VERSION 5.7 ;
BUSBITCHARS "[]" ;
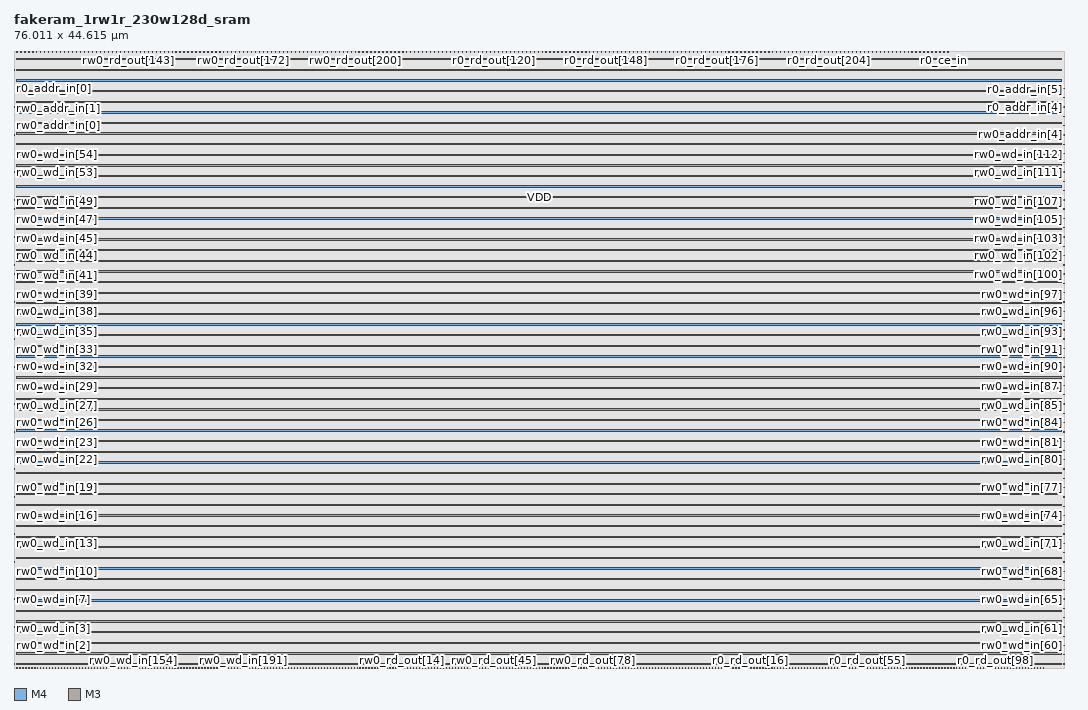
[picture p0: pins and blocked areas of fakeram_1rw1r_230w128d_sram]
MACRO fakeram_1rw1r_230w128d_sram
  FOREIGN fakeram_1rw1r_230w128d_sram 0 0 ;
  SYMMETRY X Y R90 ;
  SIZE 76.011 BY 44.615 ;
  CLASS BLOCK ;
  PIN rw0_wd_in[0]
    DIRECTION INPUT ;
    USE SIGNAL ;
    SHAPE ABUTMENT ;
    PORT
      LAYER M4 ;
      RECT 0.000 0.276 0.072 0.300 ;
    END
  END rw0_wd_in[0]
  PIN rw0_wd_in[1]
    DIRECTION INPUT ;
    USE SIGNAL ;
    SHAPE ABUTMENT ;
    PORT
      LAYER M4 ;
      RECT 0.000 0.948 0.072 0.972 ;
    END
  END rw0_wd_in[1]
  PIN rw0_wd_in[2]
    DIRECTION INPUT ;
    USE SIGNAL ;
    SHAPE ABUTMENT ;
    PORT
      LAYER M4 ;
      RECT 0.000 1.620 0.072 1.644 ;
    END
  END rw0_wd_in[2]
  PIN rw0_wd_in[3]
    DIRECTION INPUT ;
    USE SIGNAL ;
    SHAPE ABUTMENT ;
    PORT
      LAYER M4 ;
      RECT 0.000 2.292 0.072 2.316 ;
    END
  END rw0_wd_in[3]
  PIN rw0_wd_in[4]
    DIRECTION INPUT ;
    USE SIGNAL ;
    SHAPE ABUTMENT ;
    PORT
      LAYER M4 ;
      RECT 0.000 2.964 0.072 2.988 ;
    END
  END rw0_wd_in[4]
  PIN rw0_wd_in[5]
    DIRECTION INPUT ;
    USE SIGNAL ;
    SHAPE ABUTMENT ;
    PORT
      LAYER M4 ;
      RECT 0.000 3.636 0.072 3.660 ;
    END
  END rw0_wd_in[5]
  PIN rw0_wd_in[6]
    DIRECTION INPUT ;
    USE SIGNAL ;
    SHAPE ABUTMENT ;
    PORT
      LAYER M4 ;
      RECT 0.000 4.308 0.072 4.332 ;
    END
  END rw0_wd_in[6]
  PIN rw0_wd_in[7]
    DIRECTION INPUT ;
    USE SIGNAL ;
    SHAPE ABUTMENT ;
    PORT
      LAYER M4 ;
      RECT 0.000 4.980 0.072 5.004 ;
    END
  END rw0_wd_in[7]
  PIN rw0_wd_in[8]
    DIRECTION INPUT ;
    USE SIGNAL ;
    SHAPE ABUTMENT ;
    PORT
      LAYER M4 ;
      RECT 0.000 5.652 0.072 5.676 ;
    END
  END rw0_wd_in[8]
  PIN rw0_wd_in[9]
    DIRECTION INPUT ;
    USE SIGNAL ;
    SHAPE ABUTMENT ;
    PORT
      LAYER M4 ;
      RECT 0.000 6.324 0.072 6.348 ;
    END
  END rw0_wd_in[9]
  PIN rw0_wd_in[10]
    DIRECTION INPUT ;
    USE SIGNAL ;
    SHAPE ABUTMENT ;
    PORT
      LAYER M4 ;
      RECT 0.000 6.996 0.072 7.020 ;
    END
  END rw0_wd_in[10]
  PIN rw0_wd_in[11]
    DIRECTION INPUT ;
    USE SIGNAL ;
    SHAPE ABUTMENT ;
    PORT
      LAYER M4 ;
      RECT 0.000 7.668 0.072 7.692 ;
    END
  END rw0_wd_in[11]
  PIN rw0_wd_in[12]
    DIRECTION INPUT ;
    USE SIGNAL ;
    SHAPE ABUTMENT ;
    PORT
      LAYER M4 ;
      RECT 0.000 8.340 0.072 8.364 ;
    END
  END rw0_wd_in[12]
  PIN rw0_wd_in[13]
    DIRECTION INPUT ;
    USE SIGNAL ;
    SHAPE ABUTMENT ;
    PORT
      LAYER M4 ;
      RECT 0.000 9.012 0.072 9.036 ;
    END
  END rw0_wd_in[13]
  PIN rw0_wd_in[14]
    DIRECTION INPUT ;
    USE SIGNAL ;
    SHAPE ABUTMENT ;
    PORT
      LAYER M4 ;
      RECT 0.000 9.684 0.072 9.708 ;
    END
  END rw0_wd_in[14]
  PIN rw0_wd_in[15]
    DIRECTION INPUT ;
    USE SIGNAL ;
    SHAPE ABUTMENT ;
    PORT
      LAYER M4 ;
      RECT 0.000 10.356 0.072 10.380 ;
    END
  END rw0_wd_in[15]
  PIN rw0_wd_in[16]
    DIRECTION INPUT ;
    USE SIGNAL ;
    SHAPE ABUTMENT ;
    PORT
      LAYER M4 ;
      RECT 0.000 11.028 0.072 11.052 ;
    END
  END rw0_wd_in[16]
  PIN rw0_wd_in[17]
    DIRECTION INPUT ;
    USE SIGNAL ;
    SHAPE ABUTMENT ;
    PORT
      LAYER M4 ;
      RECT 0.000 11.700 0.072 11.724 ;
    END
  END rw0_wd_in[17]
  PIN rw0_wd_in[18]
    DIRECTION INPUT ;
    USE SIGNAL ;
    SHAPE ABUTMENT ;
    PORT
      LAYER M4 ;
      RECT 0.000 12.372 0.072 12.396 ;
    END
  END rw0_wd_in[18]
  PIN rw0_wd_in[19]
    DIRECTION INPUT ;
    USE SIGNAL ;
    SHAPE ABUTMENT ;
    PORT
      LAYER M4 ;
      RECT 0.000 13.044 0.072 13.068 ;
    END
  END rw0_wd_in[19]
  PIN rw0_wd_in[20]
    DIRECTION INPUT ;
    USE SIGNAL ;
    SHAPE ABUTMENT ;
    PORT
      LAYER M4 ;
      RECT 0.000 13.716 0.072 13.740 ;
    END
  END rw0_wd_in[20]
  PIN rw0_wd_in[21]
    DIRECTION INPUT ;
    USE SIGNAL ;
    SHAPE ABUTMENT ;
    PORT
      LAYER M4 ;
      RECT 0.000 14.388 0.072 14.412 ;
    END
  END rw0_wd_in[21]
  PIN rw0_wd_in[22]
    DIRECTION INPUT ;
    USE SIGNAL ;
    SHAPE ABUTMENT ;
    PORT
      LAYER M4 ;
      RECT 0.000 15.060 0.072 15.084 ;
    END
  END rw0_wd_in[22]
  PIN rw0_wd_in[23]
    DIRECTION INPUT ;
    USE SIGNAL ;
    SHAPE ABUTMENT ;
    PORT
      LAYER M4 ;
      RECT 0.000 15.732 0.072 15.756 ;
    END
  END rw0_wd_in[23]
  PIN rw0_wd_in[24]
    DIRECTION INPUT ;
    USE SIGNAL ;
    SHAPE ABUTMENT ;
    PORT
      LAYER M4 ;
      RECT 0.000 16.404 0.072 16.428 ;
    END
  END rw0_wd_in[24]
  PIN rw0_wd_in[25]
    DIRECTION INPUT ;
    USE SIGNAL ;
    SHAPE ABUTMENT ;
    PORT
      LAYER M4 ;
      RECT 0.000 17.076 0.072 17.100 ;
    END
  END rw0_wd_in[25]
  PIN rw0_wd_in[26]
    DIRECTION INPUT ;
    USE SIGNAL ;
    SHAPE ABUTMENT ;
    PORT
      LAYER M4 ;
      RECT 0.000 17.748 0.072 17.772 ;
    END
  END rw0_wd_in[26]
  PIN rw0_wd_in[27]
    DIRECTION INPUT ;
    USE SIGNAL ;
    SHAPE ABUTMENT ;
    PORT
      LAYER M4 ;
      RECT 0.000 18.420 0.072 18.444 ;
    END
  END rw0_wd_in[27]
  PIN rw0_wd_in[28]
    DIRECTION INPUT ;
    USE SIGNAL ;
    SHAPE ABUTMENT ;
    PORT
      LAYER M4 ;
      RECT 0.000 19.092 0.072 19.116 ;
    END
  END rw0_wd_in[28]
  PIN rw0_wd_in[29]
    DIRECTION INPUT ;
    USE SIGNAL ;
    SHAPE ABUTMENT ;
    PORT
      LAYER M4 ;
      RECT 0.000 19.764 0.072 19.788 ;
    END
  END rw0_wd_in[29]
  PIN rw0_wd_in[30]
    DIRECTION INPUT ;
    USE SIGNAL ;
    SHAPE ABUTMENT ;
    PORT
      LAYER M4 ;
      RECT 0.000 20.436 0.072 20.460 ;
    END
  END rw0_wd_in[30]
  PIN rw0_wd_in[31]
    DIRECTION INPUT ;
    USE SIGNAL ;
    SHAPE ABUTMENT ;
    PORT
      LAYER M4 ;
      RECT 0.000 21.108 0.072 21.132 ;
    END
  END rw0_wd_in[31]
  PIN rw0_wd_in[32]
    DIRECTION INPUT ;
    USE SIGNAL ;
    SHAPE ABUTMENT ;
    PORT
      LAYER M4 ;
      RECT 0.000 21.780 0.072 21.804 ;
    END
  END rw0_wd_in[32]
  PIN rw0_wd_in[33]
    DIRECTION INPUT ;
    USE SIGNAL ;
    SHAPE ABUTMENT ;
    PORT
      LAYER M4 ;
      RECT 0.000 22.452 0.072 22.476 ;
    END
  END rw0_wd_in[33]
  PIN rw0_wd_in[34]
    DIRECTION INPUT ;
    USE SIGNAL ;
    SHAPE ABUTMENT ;
    PORT
      LAYER M4 ;
      RECT 0.000 23.124 0.072 23.148 ;
    END
  END rw0_wd_in[34]
  PIN rw0_wd_in[35]
    DIRECTION INPUT ;
    USE SIGNAL ;
    SHAPE ABUTMENT ;
    PORT
      LAYER M4 ;
      RECT 0.000 23.796 0.072 23.820 ;
    END
  END rw0_wd_in[35]
  PIN rw0_wd_in[36]
    DIRECTION INPUT ;
    USE SIGNAL ;
    SHAPE ABUTMENT ;
    PORT
      LAYER M4 ;
      RECT 0.000 24.468 0.072 24.492 ;
    END
  END rw0_wd_in[36]
  PIN rw0_wd_in[37]
    DIRECTION INPUT ;
    USE SIGNAL ;
    SHAPE ABUTMENT ;
    PORT
      LAYER M4 ;
      RECT 0.000 25.140 0.072 25.164 ;
    END
  END rw0_wd_in[37]
  PIN rw0_wd_in[38]
    DIRECTION INPUT ;
    USE SIGNAL ;
    SHAPE ABUTMENT ;
    PORT
      LAYER M4 ;
      RECT 0.000 25.812 0.072 25.836 ;
    END
  END rw0_wd_in[38]
  PIN rw0_wd_in[39]
    DIRECTION INPUT ;
    USE SIGNAL ;
    SHAPE ABUTMENT ;
    PORT
      LAYER M4 ;
      RECT 0.000 26.484 0.072 26.508 ;
    END
  END rw0_wd_in[39]
  PIN rw0_wd_in[40]
    DIRECTION INPUT ;
    USE SIGNAL ;
    SHAPE ABUTMENT ;
    PORT
      LAYER M4 ;
      RECT 0.000 27.156 0.072 27.180 ;
    END
  END rw0_wd_in[40]
  PIN rw0_wd_in[41]
    DIRECTION INPUT ;
    USE SIGNAL ;
    SHAPE ABUTMENT ;
    PORT
      LAYER M4 ;
      RECT 0.000 27.828 0.072 27.852 ;
    END
  END rw0_wd_in[41]
  PIN rw0_wd_in[42]
    DIRECTION INPUT ;
    USE SIGNAL ;
    SHAPE ABUTMENT ;
    PORT
      LAYER M4 ;
      RECT 0.000 28.500 0.072 28.524 ;
    END
  END rw0_wd_in[42]
  PIN rw0_wd_in[43]
    DIRECTION INPUT ;
    USE SIGNAL ;
    SHAPE ABUTMENT ;
    PORT
      LAYER M4 ;
      RECT 0.000 29.172 0.072 29.196 ;
    END
  END rw0_wd_in[43]
  PIN rw0_wd_in[44]
    DIRECTION INPUT ;
    USE SIGNAL ;
    SHAPE ABUTMENT ;
    PORT
      LAYER M4 ;
      RECT 0.000 29.844 0.072 29.868 ;
    END
  END rw0_wd_in[44]
  PIN rw0_wd_in[45]
    DIRECTION INPUT ;
    USE SIGNAL ;
    SHAPE ABUTMENT ;
    PORT
      LAYER M4 ;
      RECT 0.000 30.516 0.072 30.540 ;
    END
  END rw0_wd_in[45]
  PIN rw0_wd_in[46]
    DIRECTION INPUT ;
    USE SIGNAL ;
    SHAPE ABUTMENT ;
    PORT
      LAYER M4 ;
      RECT 0.000 31.188 0.072 31.212 ;
    END
  END rw0_wd_in[46]
  PIN rw0_wd_in[47]
    DIRECTION INPUT ;
    USE SIGNAL ;
    SHAPE ABUTMENT ;
    PORT
      LAYER M4 ;
      RECT 0.000 31.860 0.072 31.884 ;
    END
  END rw0_wd_in[47]
  PIN rw0_wd_in[48]
    DIRECTION INPUT ;
    USE SIGNAL ;
    SHAPE ABUTMENT ;
    PORT
      LAYER M4 ;
      RECT 0.000 32.532 0.072 32.556 ;
    END
  END rw0_wd_in[48]
  PIN rw0_wd_in[49]
    DIRECTION INPUT ;
    USE SIGNAL ;
    SHAPE ABUTMENT ;
    PORT
      LAYER M4 ;
      RECT 0.000 33.204 0.072 33.228 ;
    END
  END rw0_wd_in[49]
  PIN rw0_wd_in[50]
    DIRECTION INPUT ;
    USE SIGNAL ;
    SHAPE ABUTMENT ;
    PORT
      LAYER M4 ;
      RECT 0.000 33.876 0.072 33.900 ;
    END
  END rw0_wd_in[50]
  PIN rw0_wd_in[51]
    DIRECTION INPUT ;
    USE SIGNAL ;
    SHAPE ABUTMENT ;
    PORT
      LAYER M4 ;
      RECT 0.000 34.548 0.072 34.572 ;
    END
  END rw0_wd_in[51]
  PIN rw0_wd_in[52]
    DIRECTION INPUT ;
    USE SIGNAL ;
    SHAPE ABUTMENT ;
    PORT
      LAYER M4 ;
      RECT 0.000 35.220 0.072 35.244 ;
    END
  END rw0_wd_in[52]
  PIN rw0_wd_in[53]
    DIRECTION INPUT ;
    USE SIGNAL ;
    SHAPE ABUTMENT ;
    PORT
      LAYER M4 ;
      RECT 0.000 35.892 0.072 35.916 ;
    END
  END rw0_wd_in[53]
  PIN rw0_wd_in[54]
    DIRECTION INPUT ;
    USE SIGNAL ;
    SHAPE ABUTMENT ;
    PORT
      LAYER M4 ;
      RECT 0.000 36.564 0.072 36.588 ;
    END
  END rw0_wd_in[54]
  PIN rw0_wd_in[55]
    DIRECTION INPUT ;
    USE SIGNAL ;
    SHAPE ABUTMENT ;
    PORT
      LAYER M4 ;
      RECT 0.000 37.236 0.072 37.260 ;
    END
  END rw0_wd_in[55]
  PIN rw0_wd_in[56]
    DIRECTION INPUT ;
    USE SIGNAL ;
    SHAPE ABUTMENT ;
    PORT
      LAYER M4 ;
      RECT 0.000 37.908 0.072 37.932 ;
    END
  END rw0_wd_in[56]
  PIN rw0_wd_in[57]
    DIRECTION INPUT ;
    USE SIGNAL ;
    SHAPE ABUTMENT ;
    PORT
      LAYER M4 ;
      RECT 0.000 38.580 0.072 38.604 ;
    END
  END rw0_wd_in[57]
  PIN rw0_wd_in[58]
    DIRECTION INPUT ;
    USE SIGNAL ;
    SHAPE ABUTMENT ;
    PORT
      LAYER M4 ;
      RECT 75.939 0.276 76.011 0.300 ;
    END
  END rw0_wd_in[58]
  PIN rw0_wd_in[59]
    DIRECTION INPUT ;
    USE SIGNAL ;
    SHAPE ABUTMENT ;
    PORT
      LAYER M4 ;
      RECT 75.939 0.948 76.011 0.972 ;
    END
  END rw0_wd_in[59]
  PIN rw0_wd_in[60]
    DIRECTION INPUT ;
    USE SIGNAL ;
    SHAPE ABUTMENT ;
    PORT
      LAYER M4 ;
      RECT 75.939 1.620 76.011 1.644 ;
    END
  END rw0_wd_in[60]
  PIN rw0_wd_in[61]
    DIRECTION INPUT ;
    USE SIGNAL ;
    SHAPE ABUTMENT ;
    PORT
      LAYER M4 ;
      RECT 75.939 2.292 76.011 2.316 ;
    END
  END rw0_wd_in[61]
  PIN rw0_wd_in[62]
    DIRECTION INPUT ;
    USE SIGNAL ;
    SHAPE ABUTMENT ;
    PORT
      LAYER M4 ;
      RECT 75.939 2.964 76.011 2.988 ;
    END
  END rw0_wd_in[62]
  PIN rw0_wd_in[63]
    DIRECTION INPUT ;
    USE SIGNAL ;
    SHAPE ABUTMENT ;
    PORT
      LAYER M4 ;
      RECT 75.939 3.636 76.011 3.660 ;
    END
  END rw0_wd_in[63]
  PIN rw0_wd_in[64]
    DIRECTION INPUT ;
    USE SIGNAL ;
    SHAPE ABUTMENT ;
    PORT
      LAYER M4 ;
      RECT 75.939 4.308 76.011 4.332 ;
    END
  END rw0_wd_in[64]
  PIN rw0_wd_in[65]
    DIRECTION INPUT ;
    USE SIGNAL ;
    SHAPE ABUTMENT ;
    PORT
      LAYER M4 ;
      RECT 75.939 4.980 76.011 5.004 ;
    END
  END rw0_wd_in[65]
  PIN rw0_wd_in[66]
    DIRECTION INPUT ;
    USE SIGNAL ;
    SHAPE ABUTMENT ;
    PORT
      LAYER M4 ;
      RECT 75.939 5.652 76.011 5.676 ;
    END
  END rw0_wd_in[66]
  PIN rw0_wd_in[67]
    DIRECTION INPUT ;
    USE SIGNAL ;
    SHAPE ABUTMENT ;
    PORT
      LAYER M4 ;
      RECT 75.939 6.324 76.011 6.348 ;
    END
  END rw0_wd_in[67]
  PIN rw0_wd_in[68]
    DIRECTION INPUT ;
    USE SIGNAL ;
    SHAPE ABUTMENT ;
    PORT
      LAYER M4 ;
      RECT 75.939 6.996 76.011 7.020 ;
    END
  END rw0_wd_in[68]
  PIN rw0_wd_in[69]
    DIRECTION INPUT ;
    USE SIGNAL ;
    SHAPE ABUTMENT ;
    PORT
      LAYER M4 ;
      RECT 75.939 7.668 76.011 7.692 ;
    END
  END rw0_wd_in[69]
  PIN rw0_wd_in[70]
    DIRECTION INPUT ;
    USE SIGNAL ;
    SHAPE ABUTMENT ;
    PORT
      LAYER M4 ;
      RECT 75.939 8.340 76.011 8.364 ;
    END
  END rw0_wd_in[70]
  PIN rw0_wd_in[71]
    DIRECTION INPUT ;
    USE SIGNAL ;
    SHAPE ABUTMENT ;
    PORT
      LAYER M4 ;
      RECT 75.939 9.012 76.011 9.036 ;
    END
  END rw0_wd_in[71]
  PIN rw0_wd_in[72]
    DIRECTION INPUT ;
    USE SIGNAL ;
    SHAPE ABUTMENT ;
    PORT
      LAYER M4 ;
      RECT 75.939 9.684 76.011 9.708 ;
    END
  END rw0_wd_in[72]
  PIN rw0_wd_in[73]
    DIRECTION INPUT ;
    USE SIGNAL ;
    SHAPE ABUTMENT ;
    PORT
      LAYER M4 ;
      RECT 75.939 10.356 76.011 10.380 ;
    END
  END rw0_wd_in[73]
  PIN rw0_wd_in[74]
    DIRECTION INPUT ;
    USE SIGNAL ;
    SHAPE ABUTMENT ;
    PORT
      LAYER M4 ;
      RECT 75.939 11.028 76.011 11.052 ;
    END
  END rw0_wd_in[74]
  PIN rw0_wd_in[75]
    DIRECTION INPUT ;
    USE SIGNAL ;
    SHAPE ABUTMENT ;
    PORT
      LAYER M4 ;
      RECT 75.939 11.700 76.011 11.724 ;
    END
  END rw0_wd_in[75]
  PIN rw0_wd_in[76]
    DIRECTION INPUT ;
    USE SIGNAL ;
    SHAPE ABUTMENT ;
    PORT
      LAYER M4 ;
      RECT 75.939 12.372 76.011 12.396 ;
    END
  END rw0_wd_in[76]
  PIN rw0_wd_in[77]
    DIRECTION INPUT ;
    USE SIGNAL ;
    SHAPE ABUTMENT ;
    PORT
      LAYER M4 ;
      RECT 75.939 13.044 76.011 13.068 ;
    END
  END rw0_wd_in[77]
  PIN rw0_wd_in[78]
    DIRECTION INPUT ;
    USE SIGNAL ;
    SHAPE ABUTMENT ;
    PORT
      LAYER M4 ;
      RECT 75.939 13.716 76.011 13.740 ;
    END
  END rw0_wd_in[78]
  PIN rw0_wd_in[79]
    DIRECTION INPUT ;
    USE SIGNAL ;
    SHAPE ABUTMENT ;
    PORT
      LAYER M4 ;
      RECT 75.939 14.388 76.011 14.412 ;
    END
  END rw0_wd_in[79]
  PIN rw0_wd_in[80]
    DIRECTION INPUT ;
    USE SIGNAL ;
    SHAPE ABUTMENT ;
    PORT
      LAYER M4 ;
      RECT 75.939 15.060 76.011 15.084 ;
    END
  END rw0_wd_in[80]
  PIN rw0_wd_in[81]
    DIRECTION INPUT ;
    USE SIGNAL ;
    SHAPE ABUTMENT ;
    PORT
      LAYER M4 ;
      RECT 75.939 15.732 76.011 15.756 ;
    END
  END rw0_wd_in[81]
  PIN rw0_wd_in[82]
    DIRECTION INPUT ;
    USE SIGNAL ;
    SHAPE ABUTMENT ;
    PORT
      LAYER M4 ;
      RECT 75.939 16.404 76.011 16.428 ;
    END
  END rw0_wd_in[82]
  PIN rw0_wd_in[83]
    DIRECTION INPUT ;
    USE SIGNAL ;
    SHAPE ABUTMENT ;
    PORT
      LAYER M4 ;
      RECT 75.939 17.076 76.011 17.100 ;
    END
  END rw0_wd_in[83]
  PIN rw0_wd_in[84]
    DIRECTION INPUT ;
    USE SIGNAL ;
    SHAPE ABUTMENT ;
    PORT
      LAYER M4 ;
      RECT 75.939 17.748 76.011 17.772 ;
    END
  END rw0_wd_in[84]
  PIN rw0_wd_in[85]
    DIRECTION INPUT ;
    USE SIGNAL ;
    SHAPE ABUTMENT ;
    PORT
      LAYER M4 ;
      RECT 75.939 18.420 76.011 18.444 ;
    END
  END rw0_wd_in[85]
  PIN rw0_wd_in[86]
    DIRECTION INPUT ;
    USE SIGNAL ;
    SHAPE ABUTMENT ;
    PORT
      LAYER M4 ;
      RECT 75.939 19.092 76.011 19.116 ;
    END
  END rw0_wd_in[86]
  PIN rw0_wd_in[87]
    DIRECTION INPUT ;
    USE SIGNAL ;
    SHAPE ABUTMENT ;
    PORT
      LAYER M4 ;
      RECT 75.939 19.764 76.011 19.788 ;
    END
  END rw0_wd_in[87]
  PIN rw0_wd_in[88]
    DIRECTION INPUT ;
    USE SIGNAL ;
    SHAPE ABUTMENT ;
    PORT
      LAYER M4 ;
      RECT 75.939 20.436 76.011 20.460 ;
    END
  END rw0_wd_in[88]
  PIN rw0_wd_in[89]
    DIRECTION INPUT ;
    USE SIGNAL ;
    SHAPE ABUTMENT ;
    PORT
      LAYER M4 ;
      RECT 75.939 21.108 76.011 21.132 ;
    END
  END rw0_wd_in[89]
  PIN rw0_wd_in[90]
    DIRECTION INPUT ;
    USE SIGNAL ;
    SHAPE ABUTMENT ;
    PORT
      LAYER M4 ;
      RECT 75.939 21.780 76.011 21.804 ;
    END
  END rw0_wd_in[90]
  PIN rw0_wd_in[91]
    DIRECTION INPUT ;
    USE SIGNAL ;
    SHAPE ABUTMENT ;
    PORT
      LAYER M4 ;
      RECT 75.939 22.452 76.011 22.476 ;
    END
  END rw0_wd_in[91]
  PIN rw0_wd_in[92]
    DIRECTION INPUT ;
    USE SIGNAL ;
    SHAPE ABUTMENT ;
    PORT
      LAYER M4 ;
      RECT 75.939 23.124 76.011 23.148 ;
    END
  END rw0_wd_in[92]
  PIN rw0_wd_in[93]
    DIRECTION INPUT ;
    USE SIGNAL ;
    SHAPE ABUTMENT ;
    PORT
      LAYER M4 ;
      RECT 75.939 23.796 76.011 23.820 ;
    END
  END rw0_wd_in[93]
  PIN rw0_wd_in[94]
    DIRECTION INPUT ;
    USE SIGNAL ;
    SHAPE ABUTMENT ;
    PORT
      LAYER M4 ;
      RECT 75.939 24.468 76.011 24.492 ;
    END
  END rw0_wd_in[94]
  PIN rw0_wd_in[95]
    DIRECTION INPUT ;
    USE SIGNAL ;
    SHAPE ABUTMENT ;
    PORT
      LAYER M4 ;
      RECT 75.939 25.140 76.011 25.164 ;
    END
  END rw0_wd_in[95]
  PIN rw0_wd_in[96]
    DIRECTION INPUT ;
    USE SIGNAL ;
    SHAPE ABUTMENT ;
    PORT
      LAYER M4 ;
      RECT 75.939 25.812 76.011 25.836 ;
    END
  END rw0_wd_in[96]
  PIN rw0_wd_in[97]
    DIRECTION INPUT ;
    USE SIGNAL ;
    SHAPE ABUTMENT ;
    PORT
      LAYER M4 ;
      RECT 75.939 26.484 76.011 26.508 ;
    END
  END rw0_wd_in[97]
  PIN rw0_wd_in[98]
    DIRECTION INPUT ;
    USE SIGNAL ;
    SHAPE ABUTMENT ;
    PORT
      LAYER M4 ;
      RECT 75.939 27.156 76.011 27.180 ;
    END
  END rw0_wd_in[98]
  PIN rw0_wd_in[99]
    DIRECTION INPUT ;
    USE SIGNAL ;
    SHAPE ABUTMENT ;
    PORT
      LAYER M4 ;
      RECT 75.939 27.828 76.011 27.852 ;
    END
  END rw0_wd_in[99]
  PIN rw0_wd_in[100]
    DIRECTION INPUT ;
    USE SIGNAL ;
    SHAPE ABUTMENT ;
    PORT
      LAYER M4 ;
      RECT 75.939 28.500 76.011 28.524 ;
    END
  END rw0_wd_in[100]
  PIN rw0_wd_in[101]
    DIRECTION INPUT ;
    USE SIGNAL ;
    SHAPE ABUTMENT ;
    PORT
      LAYER M4 ;
      RECT 75.939 29.172 76.011 29.196 ;
    END
  END rw0_wd_in[101]
  PIN rw0_wd_in[102]
    DIRECTION INPUT ;
    USE SIGNAL ;
    SHAPE ABUTMENT ;
    PORT
      LAYER M4 ;
      RECT 75.939 29.844 76.011 29.868 ;
    END
  END rw0_wd_in[102]
  PIN rw0_wd_in[103]
    DIRECTION INPUT ;
    USE SIGNAL ;
    SHAPE ABUTMENT ;
    PORT
      LAYER M4 ;
      RECT 75.939 30.516 76.011 30.540 ;
    END
  END rw0_wd_in[103]
  PIN rw0_wd_in[104]
    DIRECTION INPUT ;
    USE SIGNAL ;
    SHAPE ABUTMENT ;
    PORT
      LAYER M4 ;
      RECT 75.939 31.188 76.011 31.212 ;
    END
  END rw0_wd_in[104]
  PIN rw0_wd_in[105]
    DIRECTION INPUT ;
    USE SIGNAL ;
    SHAPE ABUTMENT ;
    PORT
      LAYER M4 ;
      RECT 75.939 31.860 76.011 31.884 ;
    END
  END rw0_wd_in[105]
  PIN rw0_wd_in[106]
    DIRECTION INPUT ;
    USE SIGNAL ;
    SHAPE ABUTMENT ;
    PORT
      LAYER M4 ;
      RECT 75.939 32.532 76.011 32.556 ;
    END
  END rw0_wd_in[106]
  PIN rw0_wd_in[107]
    DIRECTION INPUT ;
    USE SIGNAL ;
    SHAPE ABUTMENT ;
    PORT
      LAYER M4 ;
      RECT 75.939 33.204 76.011 33.228 ;
    END
  END rw0_wd_in[107]
  PIN rw0_wd_in[108]
    DIRECTION INPUT ;
    USE SIGNAL ;
    SHAPE ABUTMENT ;
    PORT
      LAYER M4 ;
      RECT 75.939 33.876 76.011 33.900 ;
    END
  END rw0_wd_in[108]
  PIN rw0_wd_in[109]
    DIRECTION INPUT ;
    USE SIGNAL ;
    SHAPE ABUTMENT ;
    PORT
      LAYER M4 ;
      RECT 75.939 34.548 76.011 34.572 ;
    END
  END rw0_wd_in[109]
  PIN rw0_wd_in[110]
    DIRECTION INPUT ;
    USE SIGNAL ;
    SHAPE ABUTMENT ;
    PORT
      LAYER M4 ;
      RECT 75.939 35.220 76.011 35.244 ;
    END
  END rw0_wd_in[110]
  PIN rw0_wd_in[111]
    DIRECTION INPUT ;
    USE SIGNAL ;
    SHAPE ABUTMENT ;
    PORT
      LAYER M4 ;
      RECT 75.939 35.892 76.011 35.916 ;
    END
  END rw0_wd_in[111]
  PIN rw0_wd_in[112]
    DIRECTION INPUT ;
    USE SIGNAL ;
    SHAPE ABUTMENT ;
    PORT
      LAYER M4 ;
      RECT 75.939 36.564 76.011 36.588 ;
    END
  END rw0_wd_in[112]
  PIN rw0_wd_in[113]
    DIRECTION INPUT ;
    USE SIGNAL ;
    SHAPE ABUTMENT ;
    PORT
      LAYER M4 ;
      RECT 75.939 37.236 76.011 37.260 ;
    END
  END rw0_wd_in[113]
  PIN rw0_wd_in[114]
    DIRECTION INPUT ;
    USE SIGNAL ;
    SHAPE ABUTMENT ;
    PORT
      LAYER M4 ;
      RECT 75.939 37.908 76.011 37.932 ;
    END
  END rw0_wd_in[114]
  PIN rw0_wd_in[115]
    DIRECTION OUTPUT ;
    USE SIGNAL ;
    SHAPE ABUTMENT ;
    PORT
      LAYER M3 ;
      RECT 0.207 0.000 0.225 0.054 ;
    END
  END rw0_wd_in[115]
  PIN rw0_wd_in[116]
    DIRECTION OUTPUT ;
    USE SIGNAL ;
    SHAPE ABUTMENT ;
    PORT
      LAYER M3 ;
      RECT 0.423 0.000 0.441 0.054 ;
    END
  END rw0_wd_in[116]
  PIN rw0_wd_in[117]
    DIRECTION OUTPUT ;
    USE SIGNAL ;
    SHAPE ABUTMENT ;
    PORT
      LAYER M3 ;
      RECT 0.639 0.000 0.657 0.054 ;
    END
  END rw0_wd_in[117]
  PIN rw0_wd_in[118]
    DIRECTION OUTPUT ;
    USE SIGNAL ;
    SHAPE ABUTMENT ;
    PORT
      LAYER M3 ;
      RECT 0.855 0.000 0.873 0.054 ;
    END
  END rw0_wd_in[118]
  PIN rw0_wd_in[119]
    DIRECTION OUTPUT ;
    USE SIGNAL ;
    SHAPE ABUTMENT ;
    PORT
      LAYER M3 ;
      RECT 1.071 0.000 1.089 0.054 ;
    END
  END rw0_wd_in[119]
  PIN rw0_wd_in[120]
    DIRECTION OUTPUT ;
    USE SIGNAL ;
    SHAPE ABUTMENT ;
    PORT
      LAYER M3 ;
      RECT 1.287 0.000 1.305 0.054 ;
    END
  END rw0_wd_in[120]
  PIN rw0_wd_in[121]
    DIRECTION OUTPUT ;
    USE SIGNAL ;
    SHAPE ABUTMENT ;
    PORT
      LAYER M3 ;
      RECT 1.503 0.000 1.521 0.054 ;
    END
  END rw0_wd_in[121]
  PIN rw0_wd_in[122]
    DIRECTION OUTPUT ;
    USE SIGNAL ;
    SHAPE ABUTMENT ;
    PORT
      LAYER M3 ;
      RECT 1.719 0.000 1.737 0.054 ;
    END
  END rw0_wd_in[122]
  PIN rw0_wd_in[123]
    DIRECTION OUTPUT ;
    USE SIGNAL ;
    SHAPE ABUTMENT ;
    PORT
      LAYER M3 ;
      RECT 1.935 0.000 1.953 0.054 ;
    END
  END rw0_wd_in[123]
  PIN rw0_wd_in[124]
    DIRECTION OUTPUT ;
    USE SIGNAL ;
    SHAPE ABUTMENT ;
    PORT
      LAYER M3 ;
      RECT 2.151 0.000 2.169 0.054 ;
    END
  END rw0_wd_in[124]
  PIN rw0_wd_in[125]
    DIRECTION OUTPUT ;
    USE SIGNAL ;
    SHAPE ABUTMENT ;
    PORT
      LAYER M3 ;
      RECT 2.367 0.000 2.385 0.054 ;
    END
  END rw0_wd_in[125]
  PIN rw0_wd_in[126]
    DIRECTION OUTPUT ;
    USE SIGNAL ;
    SHAPE ABUTMENT ;
    PORT
      LAYER M3 ;
      RECT 2.583 0.000 2.601 0.054 ;
    END
  END rw0_wd_in[126]
  PIN rw0_wd_in[127]
    DIRECTION OUTPUT ;
    USE SIGNAL ;
    SHAPE ABUTMENT ;
    PORT
      LAYER M3 ;
      RECT 2.799 0.000 2.817 0.054 ;
    END
  END rw0_wd_in[127]
  PIN rw0_wd_in[128]
    DIRECTION OUTPUT ;
    USE SIGNAL ;
    SHAPE ABUTMENT ;
    PORT
      LAYER M3 ;
      RECT 3.015 0.000 3.033 0.054 ;
    END
  END rw0_wd_in[128]
  PIN rw0_wd_in[129]
    DIRECTION OUTPUT ;
    USE SIGNAL ;
    SHAPE ABUTMENT ;
    PORT
      LAYER M3 ;
      RECT 3.231 0.000 3.249 0.054 ;
    END
  END rw0_wd_in[129]
  PIN rw0_wd_in[130]
    DIRECTION OUTPUT ;
    USE SIGNAL ;
    SHAPE ABUTMENT ;
    PORT
      LAYER M3 ;
      RECT 3.447 0.000 3.465 0.054 ;
    END
  END rw0_wd_in[130]
  PIN rw0_wd_in[131]
    DIRECTION OUTPUT ;
    USE SIGNAL ;
    SHAPE ABUTMENT ;
    PORT
      LAYER M3 ;
      RECT 3.663 0.000 3.681 0.054 ;
    END
  END rw0_wd_in[131]
  PIN rw0_wd_in[132]
    DIRECTION OUTPUT ;
    USE SIGNAL ;
    SHAPE ABUTMENT ;
    PORT
      LAYER M3 ;
      RECT 3.879 0.000 3.897 0.054 ;
    END
  END rw0_wd_in[132]
  PIN rw0_wd_in[133]
    DIRECTION OUTPUT ;
    USE SIGNAL ;
    SHAPE ABUTMENT ;
    PORT
      LAYER M3 ;
      RECT 4.095 0.000 4.113 0.054 ;
    END
  END rw0_wd_in[133]
  PIN rw0_wd_in[134]
    DIRECTION OUTPUT ;
    USE SIGNAL ;
    SHAPE ABUTMENT ;
    PORT
      LAYER M3 ;
      RECT 4.311 0.000 4.329 0.054 ;
    END
  END rw0_wd_in[134]
  PIN rw0_wd_in[135]
    DIRECTION OUTPUT ;
    USE SIGNAL ;
    SHAPE ABUTMENT ;
    PORT
      LAYER M3 ;
      RECT 4.527 0.000 4.545 0.054 ;
    END
  END rw0_wd_in[135]
  PIN rw0_wd_in[136]
    DIRECTION OUTPUT ;
    USE SIGNAL ;
    SHAPE ABUTMENT ;
    PORT
      LAYER M3 ;
      RECT 4.743 0.000 4.761 0.054 ;
    END
  END rw0_wd_in[136]
  PIN rw0_wd_in[137]
    DIRECTION OUTPUT ;
    USE SIGNAL ;
    SHAPE ABUTMENT ;
    PORT
      LAYER M3 ;
      RECT 4.959 0.000 4.977 0.054 ;
    END
  END rw0_wd_in[137]
  PIN rw0_wd_in[138]
    DIRECTION OUTPUT ;
    USE SIGNAL ;
    SHAPE ABUTMENT ;
    PORT
      LAYER M3 ;
      RECT 5.175 0.000 5.193 0.054 ;
    END
  END rw0_wd_in[138]
  PIN rw0_wd_in[139]
    DIRECTION OUTPUT ;
    USE SIGNAL ;
    SHAPE ABUTMENT ;
    PORT
      LAYER M3 ;
      RECT 5.391 0.000 5.409 0.054 ;
    END
  END rw0_wd_in[139]
  PIN rw0_wd_in[140]
    DIRECTION OUTPUT ;
    USE SIGNAL ;
    SHAPE ABUTMENT ;
    PORT
      LAYER M3 ;
      RECT 5.607 0.000 5.625 0.054 ;
    END
  END rw0_wd_in[140]
  PIN rw0_wd_in[141]
    DIRECTION OUTPUT ;
    USE SIGNAL ;
    SHAPE ABUTMENT ;
    PORT
      LAYER M3 ;
      RECT 5.823 0.000 5.841 0.054 ;
    END
  END rw0_wd_in[141]
  PIN rw0_wd_in[142]
    DIRECTION OUTPUT ;
    USE SIGNAL ;
    SHAPE ABUTMENT ;
    PORT
      LAYER M3 ;
      RECT 6.039 0.000 6.057 0.054 ;
    END
  END rw0_wd_in[142]
  PIN rw0_wd_in[143]
    DIRECTION OUTPUT ;
    USE SIGNAL ;
    SHAPE ABUTMENT ;
    PORT
      LAYER M3 ;
      RECT 6.255 0.000 6.273 0.054 ;
    END
  END rw0_wd_in[143]
  PIN rw0_wd_in[144]
    DIRECTION OUTPUT ;
    USE SIGNAL ;
    SHAPE ABUTMENT ;
    PORT
      LAYER M3 ;
      RECT 6.471 0.000 6.489 0.054 ;
    END
  END rw0_wd_in[144]
  PIN rw0_wd_in[145]
    DIRECTION OUTPUT ;
    USE SIGNAL ;
    SHAPE ABUTMENT ;
    PORT
      LAYER M3 ;
      RECT 6.687 0.000 6.705 0.054 ;
    END
  END rw0_wd_in[145]
  PIN rw0_wd_in[146]
    DIRECTION OUTPUT ;
    USE SIGNAL ;
    SHAPE ABUTMENT ;
    PORT
      LAYER M3 ;
      RECT 6.903 0.000 6.921 0.054 ;
    END
  END rw0_wd_in[146]
  PIN rw0_wd_in[147]
    DIRECTION OUTPUT ;
    USE SIGNAL ;
    SHAPE ABUTMENT ;
    PORT
      LAYER M3 ;
      RECT 7.119 0.000 7.137 0.054 ;
    END
  END rw0_wd_in[147]
  PIN rw0_wd_in[148]
    DIRECTION OUTPUT ;
    USE SIGNAL ;
    SHAPE ABUTMENT ;
    PORT
      LAYER M3 ;
      RECT 7.335 0.000 7.353 0.054 ;
    END
  END rw0_wd_in[148]
  PIN rw0_wd_in[149]
    DIRECTION OUTPUT ;
    USE SIGNAL ;
    SHAPE ABUTMENT ;
    PORT
      LAYER M3 ;
      RECT 7.551 0.000 7.569 0.054 ;
    END
  END rw0_wd_in[149]
  PIN rw0_wd_in[150]
    DIRECTION OUTPUT ;
    USE SIGNAL ;
    SHAPE ABUTMENT ;
    PORT
      LAYER M3 ;
      RECT 7.767 0.000 7.785 0.054 ;
    END
  END rw0_wd_in[150]
  PIN rw0_wd_in[151]
    DIRECTION OUTPUT ;
    USE SIGNAL ;
    SHAPE ABUTMENT ;
    PORT
      LAYER M3 ;
      RECT 7.983 0.000 8.001 0.054 ;
    END
  END rw0_wd_in[151]
  PIN rw0_wd_in[152]
    DIRECTION OUTPUT ;
    USE SIGNAL ;
    SHAPE ABUTMENT ;
    PORT
      LAYER M3 ;
      RECT 8.199 0.000 8.217 0.054 ;
    END
  END rw0_wd_in[152]
  PIN rw0_wd_in[153]
    DIRECTION OUTPUT ;
    USE SIGNAL ;
    SHAPE ABUTMENT ;
    PORT
      LAYER M3 ;
      RECT 8.415 0.000 8.433 0.054 ;
    END
  END rw0_wd_in[153]
  PIN rw0_wd_in[154]
    DIRECTION OUTPUT ;
    USE SIGNAL ;
    SHAPE ABUTMENT ;
    PORT
      LAYER M3 ;
      RECT 8.631 0.000 8.649 0.054 ;
    END
  END rw0_wd_in[154]
  PIN rw0_wd_in[155]
    DIRECTION OUTPUT ;
    USE SIGNAL ;
    SHAPE ABUTMENT ;
    PORT
      LAYER M3 ;
      RECT 8.847 0.000 8.865 0.054 ;
    END
  END rw0_wd_in[155]
  PIN rw0_wd_in[156]
    DIRECTION OUTPUT ;
    USE SIGNAL ;
    SHAPE ABUTMENT ;
    PORT
      LAYER M3 ;
      RECT 9.063 0.000 9.081 0.054 ;
    END
  END rw0_wd_in[156]
  PIN rw0_wd_in[157]
    DIRECTION OUTPUT ;
    USE SIGNAL ;
    SHAPE ABUTMENT ;
    PORT
      LAYER M3 ;
      RECT 9.279 0.000 9.297 0.054 ;
    END
  END rw0_wd_in[157]
  PIN rw0_wd_in[158]
    DIRECTION OUTPUT ;
    USE SIGNAL ;
    SHAPE ABUTMENT ;
    PORT
      LAYER M3 ;
      RECT 9.495 0.000 9.513 0.054 ;
    END
  END rw0_wd_in[158]
  PIN rw0_wd_in[159]
    DIRECTION OUTPUT ;
    USE SIGNAL ;
    SHAPE ABUTMENT ;
    PORT
      LAYER M3 ;
      RECT 9.711 0.000 9.729 0.054 ;
    END
  END rw0_wd_in[159]
  PIN rw0_wd_in[160]
    DIRECTION OUTPUT ;
    USE SIGNAL ;
    SHAPE ABUTMENT ;
    PORT
      LAYER M3 ;
      RECT 9.927 0.000 9.945 0.054 ;
    END
  END rw0_wd_in[160]
  PIN rw0_wd_in[161]
    DIRECTION OUTPUT ;
    USE SIGNAL ;
    SHAPE ABUTMENT ;
    PORT
      LAYER M3 ;
      RECT 10.143 0.000 10.161 0.054 ;
    END
  END rw0_wd_in[161]
  PIN rw0_wd_in[162]
    DIRECTION OUTPUT ;
    USE SIGNAL ;
    SHAPE ABUTMENT ;
    PORT
      LAYER M3 ;
      RECT 10.359 0.000 10.377 0.054 ;
    END
  END rw0_wd_in[162]
  PIN rw0_wd_in[163]
    DIRECTION OUTPUT ;
    USE SIGNAL ;
    SHAPE ABUTMENT ;
    PORT
      LAYER M3 ;
      RECT 10.575 0.000 10.593 0.054 ;
    END
  END rw0_wd_in[163]
  PIN rw0_wd_in[164]
    DIRECTION OUTPUT ;
    USE SIGNAL ;
    SHAPE ABUTMENT ;
    PORT
      LAYER M3 ;
      RECT 10.791 0.000 10.809 0.054 ;
    END
  END rw0_wd_in[164]
  PIN rw0_wd_in[165]
    DIRECTION OUTPUT ;
    USE SIGNAL ;
    SHAPE ABUTMENT ;
    PORT
      LAYER M3 ;
      RECT 11.007 0.000 11.025 0.054 ;
    END
  END rw0_wd_in[165]
  PIN rw0_wd_in[166]
    DIRECTION OUTPUT ;
    USE SIGNAL ;
    SHAPE ABUTMENT ;
    PORT
      LAYER M3 ;
      RECT 11.223 0.000 11.241 0.054 ;
    END
  END rw0_wd_in[166]
  PIN rw0_wd_in[167]
    DIRECTION OUTPUT ;
    USE SIGNAL ;
    SHAPE ABUTMENT ;
    PORT
      LAYER M3 ;
      RECT 11.439 0.000 11.457 0.054 ;
    END
  END rw0_wd_in[167]
  PIN rw0_wd_in[168]
    DIRECTION OUTPUT ;
    USE SIGNAL ;
    SHAPE ABUTMENT ;
    PORT
      LAYER M3 ;
      RECT 11.655 0.000 11.673 0.054 ;
    END
  END rw0_wd_in[168]
  PIN rw0_wd_in[169]
    DIRECTION OUTPUT ;
    USE SIGNAL ;
    SHAPE ABUTMENT ;
    PORT
      LAYER M3 ;
      RECT 11.871 0.000 11.889 0.054 ;
    END
  END rw0_wd_in[169]
  PIN rw0_wd_in[170]
    DIRECTION OUTPUT ;
    USE SIGNAL ;
    SHAPE ABUTMENT ;
    PORT
      LAYER M3 ;
      RECT 12.087 0.000 12.105 0.054 ;
    END
  END rw0_wd_in[170]
  PIN rw0_wd_in[171]
    DIRECTION OUTPUT ;
    USE SIGNAL ;
    SHAPE ABUTMENT ;
    PORT
      LAYER M3 ;
      RECT 12.303 0.000 12.321 0.054 ;
    END
  END rw0_wd_in[171]
  PIN rw0_wd_in[172]
    DIRECTION OUTPUT ;
    USE SIGNAL ;
    SHAPE ABUTMENT ;
    PORT
      LAYER M3 ;
      RECT 12.519 0.000 12.537 0.054 ;
    END
  END rw0_wd_in[172]
  PIN rw0_wd_in[173]
    DIRECTION OUTPUT ;
    USE SIGNAL ;
    SHAPE ABUTMENT ;
    PORT
      LAYER M3 ;
      RECT 12.735 0.000 12.753 0.054 ;
    END
  END rw0_wd_in[173]
  PIN rw0_wd_in[174]
    DIRECTION OUTPUT ;
    USE SIGNAL ;
    SHAPE ABUTMENT ;
    PORT
      LAYER M3 ;
      RECT 12.951 0.000 12.969 0.054 ;
    END
  END rw0_wd_in[174]
  PIN rw0_wd_in[175]
    DIRECTION OUTPUT ;
    USE SIGNAL ;
    SHAPE ABUTMENT ;
    PORT
      LAYER M3 ;
      RECT 13.167 0.000 13.185 0.054 ;
    END
  END rw0_wd_in[175]
  PIN rw0_wd_in[176]
    DIRECTION OUTPUT ;
    USE SIGNAL ;
    SHAPE ABUTMENT ;
    PORT
      LAYER M3 ;
      RECT 13.383 0.000 13.401 0.054 ;
    END
  END rw0_wd_in[176]
  PIN rw0_wd_in[177]
    DIRECTION OUTPUT ;
    USE SIGNAL ;
    SHAPE ABUTMENT ;
    PORT
      LAYER M3 ;
      RECT 13.599 0.000 13.617 0.054 ;
    END
  END rw0_wd_in[177]
  PIN rw0_wd_in[178]
    DIRECTION OUTPUT ;
    USE SIGNAL ;
    SHAPE ABUTMENT ;
    PORT
      LAYER M3 ;
      RECT 13.815 0.000 13.833 0.054 ;
    END
  END rw0_wd_in[178]
  PIN rw0_wd_in[179]
    DIRECTION OUTPUT ;
    USE SIGNAL ;
    SHAPE ABUTMENT ;
    PORT
      LAYER M3 ;
      RECT 14.031 0.000 14.049 0.054 ;
    END
  END rw0_wd_in[179]
  PIN rw0_wd_in[180]
    DIRECTION OUTPUT ;
    USE SIGNAL ;
    SHAPE ABUTMENT ;
    PORT
      LAYER M3 ;
      RECT 14.247 0.000 14.265 0.054 ;
    END
  END rw0_wd_in[180]
  PIN rw0_wd_in[181]
    DIRECTION OUTPUT ;
    USE SIGNAL ;
    SHAPE ABUTMENT ;
    PORT
      LAYER M3 ;
      RECT 14.463 0.000 14.481 0.054 ;
    END
  END rw0_wd_in[181]
  PIN rw0_wd_in[182]
    DIRECTION OUTPUT ;
    USE SIGNAL ;
    SHAPE ABUTMENT ;
    PORT
      LAYER M3 ;
      RECT 14.679 0.000 14.697 0.054 ;
    END
  END rw0_wd_in[182]
  PIN rw0_wd_in[183]
    DIRECTION OUTPUT ;
    USE SIGNAL ;
    SHAPE ABUTMENT ;
    PORT
      LAYER M3 ;
      RECT 14.895 0.000 14.913 0.054 ;
    END
  END rw0_wd_in[183]
  PIN rw0_wd_in[184]
    DIRECTION OUTPUT ;
    USE SIGNAL ;
    SHAPE ABUTMENT ;
    PORT
      LAYER M3 ;
      RECT 15.111 0.000 15.129 0.054 ;
    END
  END rw0_wd_in[184]
  PIN rw0_wd_in[185]
    DIRECTION OUTPUT ;
    USE SIGNAL ;
    SHAPE ABUTMENT ;
    PORT
      LAYER M3 ;
      RECT 15.327 0.000 15.345 0.054 ;
    END
  END rw0_wd_in[185]
  PIN rw0_wd_in[186]
    DIRECTION OUTPUT ;
    USE SIGNAL ;
    SHAPE ABUTMENT ;
    PORT
      LAYER M3 ;
      RECT 15.543 0.000 15.561 0.054 ;
    END
  END rw0_wd_in[186]
  PIN rw0_wd_in[187]
    DIRECTION OUTPUT ;
    USE SIGNAL ;
    SHAPE ABUTMENT ;
    PORT
      LAYER M3 ;
      RECT 15.759 0.000 15.777 0.054 ;
    END
  END rw0_wd_in[187]
  PIN rw0_wd_in[188]
    DIRECTION OUTPUT ;
    USE SIGNAL ;
    SHAPE ABUTMENT ;
    PORT
      LAYER M3 ;
      RECT 15.975 0.000 15.993 0.054 ;
    END
  END rw0_wd_in[188]
  PIN rw0_wd_in[189]
    DIRECTION OUTPUT ;
    USE SIGNAL ;
    SHAPE ABUTMENT ;
    PORT
      LAYER M3 ;
      RECT 16.191 0.000 16.209 0.054 ;
    END
  END rw0_wd_in[189]
  PIN rw0_wd_in[190]
    DIRECTION OUTPUT ;
    USE SIGNAL ;
    SHAPE ABUTMENT ;
    PORT
      LAYER M3 ;
      RECT 16.407 0.000 16.425 0.054 ;
    END
  END rw0_wd_in[190]
  PIN rw0_wd_in[191]
    DIRECTION OUTPUT ;
    USE SIGNAL ;
    SHAPE ABUTMENT ;
    PORT
      LAYER M3 ;
      RECT 16.623 0.000 16.641 0.054 ;
    END
  END rw0_wd_in[191]
  PIN rw0_wd_in[192]
    DIRECTION OUTPUT ;
    USE SIGNAL ;
    SHAPE ABUTMENT ;
    PORT
      LAYER M3 ;
      RECT 16.839 0.000 16.857 0.054 ;
    END
  END rw0_wd_in[192]
  PIN rw0_wd_in[193]
    DIRECTION OUTPUT ;
    USE SIGNAL ;
    SHAPE ABUTMENT ;
    PORT
      LAYER M3 ;
      RECT 17.055 0.000 17.073 0.054 ;
    END
  END rw0_wd_in[193]
  PIN rw0_wd_in[194]
    DIRECTION OUTPUT ;
    USE SIGNAL ;
    SHAPE ABUTMENT ;
    PORT
      LAYER M3 ;
      RECT 17.271 0.000 17.289 0.054 ;
    END
  END rw0_wd_in[194]
  PIN rw0_wd_in[195]
    DIRECTION OUTPUT ;
    USE SIGNAL ;
    SHAPE ABUTMENT ;
    PORT
      LAYER M3 ;
      RECT 17.487 0.000 17.505 0.054 ;
    END
  END rw0_wd_in[195]
  PIN rw0_wd_in[196]
    DIRECTION OUTPUT ;
    USE SIGNAL ;
    SHAPE ABUTMENT ;
    PORT
      LAYER M3 ;
      RECT 17.703 0.000 17.721 0.054 ;
    END
  END rw0_wd_in[196]
  PIN rw0_wd_in[197]
    DIRECTION OUTPUT ;
    USE SIGNAL ;
    SHAPE ABUTMENT ;
    PORT
      LAYER M3 ;
      RECT 17.919 0.000 17.937 0.054 ;
    END
  END rw0_wd_in[197]
  PIN rw0_wd_in[198]
    DIRECTION OUTPUT ;
    USE SIGNAL ;
    SHAPE ABUTMENT ;
    PORT
      LAYER M3 ;
      RECT 18.135 0.000 18.153 0.054 ;
    END
  END rw0_wd_in[198]
  PIN rw0_wd_in[199]
    DIRECTION OUTPUT ;
    USE SIGNAL ;
    SHAPE ABUTMENT ;
    PORT
      LAYER M3 ;
      RECT 18.351 0.000 18.369 0.054 ;
    END
  END rw0_wd_in[199]
  PIN rw0_wd_in[200]
    DIRECTION OUTPUT ;
    USE SIGNAL ;
    SHAPE ABUTMENT ;
    PORT
      LAYER M3 ;
      RECT 18.567 0.000 18.585 0.054 ;
    END
  END rw0_wd_in[200]
  PIN rw0_wd_in[201]
    DIRECTION OUTPUT ;
    USE SIGNAL ;
    SHAPE ABUTMENT ;
    PORT
      LAYER M3 ;
      RECT 18.783 0.000 18.801 0.054 ;
    END
  END rw0_wd_in[201]
  PIN rw0_wd_in[202]
    DIRECTION OUTPUT ;
    USE SIGNAL ;
    SHAPE ABUTMENT ;
    PORT
      LAYER M3 ;
      RECT 18.999 0.000 19.017 0.054 ;
    END
  END rw0_wd_in[202]
  PIN rw0_wd_in[203]
    DIRECTION OUTPUT ;
    USE SIGNAL ;
    SHAPE ABUTMENT ;
    PORT
      LAYER M3 ;
      RECT 19.215 0.000 19.233 0.054 ;
    END
  END rw0_wd_in[203]
  PIN rw0_wd_in[204]
    DIRECTION OUTPUT ;
    USE SIGNAL ;
    SHAPE ABUTMENT ;
    PORT
      LAYER M3 ;
      RECT 19.431 0.000 19.449 0.054 ;
    END
  END rw0_wd_in[204]
  PIN rw0_wd_in[205]
    DIRECTION OUTPUT ;
    USE SIGNAL ;
    SHAPE ABUTMENT ;
    PORT
      LAYER M3 ;
      RECT 19.647 0.000 19.665 0.054 ;
    END
  END rw0_wd_in[205]
  PIN rw0_wd_in[206]
    DIRECTION OUTPUT ;
    USE SIGNAL ;
    SHAPE ABUTMENT ;
    PORT
      LAYER M3 ;
      RECT 19.863 0.000 19.881 0.054 ;
    END
  END rw0_wd_in[206]
  PIN rw0_wd_in[207]
    DIRECTION OUTPUT ;
    USE SIGNAL ;
    SHAPE ABUTMENT ;
    PORT
      LAYER M3 ;
      RECT 20.079 0.000 20.097 0.054 ;
    END
  END rw0_wd_in[207]
  PIN rw0_wd_in[208]
    DIRECTION OUTPUT ;
    USE SIGNAL ;
    SHAPE ABUTMENT ;
    PORT
      LAYER M3 ;
      RECT 20.295 0.000 20.313 0.054 ;
    END
  END rw0_wd_in[208]
  PIN rw0_wd_in[209]
    DIRECTION OUTPUT ;
    USE SIGNAL ;
    SHAPE ABUTMENT ;
    PORT
      LAYER M3 ;
      RECT 20.511 0.000 20.529 0.054 ;
    END
  END rw0_wd_in[209]
  PIN rw0_wd_in[210]
    DIRECTION OUTPUT ;
    USE SIGNAL ;
    SHAPE ABUTMENT ;
    PORT
      LAYER M3 ;
      RECT 20.727 0.000 20.745 0.054 ;
    END
  END rw0_wd_in[210]
  PIN rw0_wd_in[211]
    DIRECTION OUTPUT ;
    USE SIGNAL ;
    SHAPE ABUTMENT ;
    PORT
      LAYER M3 ;
      RECT 20.943 0.000 20.961 0.054 ;
    END
  END rw0_wd_in[211]
  PIN rw0_wd_in[212]
    DIRECTION OUTPUT ;
    USE SIGNAL ;
    SHAPE ABUTMENT ;
    PORT
      LAYER M3 ;
      RECT 21.159 0.000 21.177 0.054 ;
    END
  END rw0_wd_in[212]
  PIN rw0_wd_in[213]
    DIRECTION OUTPUT ;
    USE SIGNAL ;
    SHAPE ABUTMENT ;
    PORT
      LAYER M3 ;
      RECT 21.375 0.000 21.393 0.054 ;
    END
  END rw0_wd_in[213]
  PIN rw0_wd_in[214]
    DIRECTION OUTPUT ;
    USE SIGNAL ;
    SHAPE ABUTMENT ;
    PORT
      LAYER M3 ;
      RECT 21.591 0.000 21.609 0.054 ;
    END
  END rw0_wd_in[214]
  PIN rw0_wd_in[215]
    DIRECTION OUTPUT ;
    USE SIGNAL ;
    SHAPE ABUTMENT ;
    PORT
      LAYER M3 ;
      RECT 21.807 0.000 21.825 0.054 ;
    END
  END rw0_wd_in[215]
  PIN rw0_wd_in[216]
    DIRECTION OUTPUT ;
    USE SIGNAL ;
    SHAPE ABUTMENT ;
    PORT
      LAYER M3 ;
      RECT 22.023 0.000 22.041 0.054 ;
    END
  END rw0_wd_in[216]
  PIN rw0_wd_in[217]
    DIRECTION OUTPUT ;
    USE SIGNAL ;
    SHAPE ABUTMENT ;
    PORT
      LAYER M3 ;
      RECT 22.239 0.000 22.257 0.054 ;
    END
  END rw0_wd_in[217]
  PIN rw0_wd_in[218]
    DIRECTION OUTPUT ;
    USE SIGNAL ;
    SHAPE ABUTMENT ;
    PORT
      LAYER M3 ;
      RECT 22.455 0.000 22.473 0.054 ;
    END
  END rw0_wd_in[218]
  PIN rw0_wd_in[219]
    DIRECTION OUTPUT ;
    USE SIGNAL ;
    SHAPE ABUTMENT ;
    PORT
      LAYER M3 ;
      RECT 22.671 0.000 22.689 0.054 ;
    END
  END rw0_wd_in[219]
  PIN rw0_wd_in[220]
    DIRECTION OUTPUT ;
    USE SIGNAL ;
    SHAPE ABUTMENT ;
    PORT
      LAYER M3 ;
      RECT 22.887 0.000 22.905 0.054 ;
    END
  END rw0_wd_in[220]
  PIN rw0_wd_in[221]
    DIRECTION OUTPUT ;
    USE SIGNAL ;
    SHAPE ABUTMENT ;
    PORT
      LAYER M3 ;
      RECT 23.103 0.000 23.121 0.054 ;
    END
  END rw0_wd_in[221]
  PIN rw0_wd_in[222]
    DIRECTION OUTPUT ;
    USE SIGNAL ;
    SHAPE ABUTMENT ;
    PORT
      LAYER M3 ;
      RECT 23.319 0.000 23.337 0.054 ;
    END
  END rw0_wd_in[222]
  PIN rw0_wd_in[223]
    DIRECTION OUTPUT ;
    USE SIGNAL ;
    SHAPE ABUTMENT ;
    PORT
      LAYER M3 ;
      RECT 23.535 0.000 23.553 0.054 ;
    END
  END rw0_wd_in[223]
  PIN rw0_wd_in[224]
    DIRECTION OUTPUT ;
    USE SIGNAL ;
    SHAPE ABUTMENT ;
    PORT
      LAYER M3 ;
      RECT 23.751 0.000 23.769 0.054 ;
    END
  END rw0_wd_in[224]
  PIN rw0_wd_in[225]
    DIRECTION OUTPUT ;
    USE SIGNAL ;
    SHAPE ABUTMENT ;
    PORT
      LAYER M3 ;
      RECT 23.967 0.000 23.985 0.054 ;
    END
  END rw0_wd_in[225]
  PIN rw0_wd_in[226]
    DIRECTION OUTPUT ;
    USE SIGNAL ;
    SHAPE ABUTMENT ;
    PORT
      LAYER M3 ;
      RECT 24.183 0.000 24.201 0.054 ;
    END
  END rw0_wd_in[226]
  PIN rw0_wd_in[227]
    DIRECTION OUTPUT ;
    USE SIGNAL ;
    SHAPE ABUTMENT ;
    PORT
      LAYER M3 ;
      RECT 24.399 0.000 24.417 0.054 ;
    END
  END rw0_wd_in[227]
  PIN rw0_wd_in[228]
    DIRECTION OUTPUT ;
    USE SIGNAL ;
    SHAPE ABUTMENT ;
    PORT
      LAYER M3 ;
      RECT 24.615 0.000 24.633 0.054 ;
    END
  END rw0_wd_in[228]
  PIN rw0_wd_in[229]
    DIRECTION OUTPUT ;
    USE SIGNAL ;
    SHAPE ABUTMENT ;
    PORT
      LAYER M3 ;
      RECT 24.831 0.000 24.849 0.054 ;
    END
  END rw0_wd_in[229]
  PIN rw0_rd_out[0]
    DIRECTION OUTPUT ;
    USE SIGNAL ;
    SHAPE ABUTMENT ;
    PORT
      LAYER M3 ;
      RECT 25.047 0.000 25.065 0.054 ;
    END
  END rw0_rd_out[0]
  PIN rw0_rd_out[1]
    DIRECTION OUTPUT ;
    USE SIGNAL ;
    SHAPE ABUTMENT ;
    PORT
      LAYER M3 ;
      RECT 25.263 0.000 25.281 0.054 ;
    END
  END rw0_rd_out[1]
  PIN rw0_rd_out[2]
    DIRECTION OUTPUT ;
    USE SIGNAL ;
    SHAPE ABUTMENT ;
    PORT
      LAYER M3 ;
      RECT 25.479 0.000 25.497 0.054 ;
    END
  END rw0_rd_out[2]
  PIN rw0_rd_out[3]
    DIRECTION OUTPUT ;
    USE SIGNAL ;
    SHAPE ABUTMENT ;
    PORT
      LAYER M3 ;
      RECT 25.695 0.000 25.713 0.054 ;
    END
  END rw0_rd_out[3]
  PIN rw0_rd_out[4]
    DIRECTION OUTPUT ;
    USE SIGNAL ;
    SHAPE ABUTMENT ;
    PORT
      LAYER M3 ;
      RECT 25.911 0.000 25.929 0.054 ;
    END
  END rw0_rd_out[4]
  PIN rw0_rd_out[5]
    DIRECTION OUTPUT ;
    USE SIGNAL ;
    SHAPE ABUTMENT ;
    PORT
      LAYER M3 ;
      RECT 26.127 0.000 26.145 0.054 ;
    END
  END rw0_rd_out[5]
  PIN rw0_rd_out[6]
    DIRECTION OUTPUT ;
    USE SIGNAL ;
    SHAPE ABUTMENT ;
    PORT
      LAYER M3 ;
      RECT 26.343 0.000 26.361 0.054 ;
    END
  END rw0_rd_out[6]
  PIN rw0_rd_out[7]
    DIRECTION OUTPUT ;
    USE SIGNAL ;
    SHAPE ABUTMENT ;
    PORT
      LAYER M3 ;
      RECT 26.559 0.000 26.577 0.054 ;
    END
  END rw0_rd_out[7]
  PIN rw0_rd_out[8]
    DIRECTION OUTPUT ;
    USE SIGNAL ;
    SHAPE ABUTMENT ;
    PORT
      LAYER M3 ;
      RECT 26.775 0.000 26.793 0.054 ;
    END
  END rw0_rd_out[8]
  PIN rw0_rd_out[9]
    DIRECTION OUTPUT ;
    USE SIGNAL ;
    SHAPE ABUTMENT ;
    PORT
      LAYER M3 ;
      RECT 26.991 0.000 27.009 0.054 ;
    END
  END rw0_rd_out[9]
  PIN rw0_rd_out[10]
    DIRECTION OUTPUT ;
    USE SIGNAL ;
    SHAPE ABUTMENT ;
    PORT
      LAYER M3 ;
      RECT 27.207 0.000 27.225 0.054 ;
    END
  END rw0_rd_out[10]
  PIN rw0_rd_out[11]
    DIRECTION OUTPUT ;
    USE SIGNAL ;
    SHAPE ABUTMENT ;
    PORT
      LAYER M3 ;
      RECT 27.423 0.000 27.441 0.054 ;
    END
  END rw0_rd_out[11]
  PIN rw0_rd_out[12]
    DIRECTION OUTPUT ;
    USE SIGNAL ;
    SHAPE ABUTMENT ;
    PORT
      LAYER M3 ;
      RECT 27.639 0.000 27.657 0.054 ;
    END
  END rw0_rd_out[12]
  PIN rw0_rd_out[13]
    DIRECTION OUTPUT ;
    USE SIGNAL ;
    SHAPE ABUTMENT ;
    PORT
      LAYER M3 ;
      RECT 27.855 0.000 27.873 0.054 ;
    END
  END rw0_rd_out[13]
  PIN rw0_rd_out[14]
    DIRECTION OUTPUT ;
    USE SIGNAL ;
    SHAPE ABUTMENT ;
    PORT
      LAYER M3 ;
      RECT 28.071 0.000 28.089 0.054 ;
    END
  END rw0_rd_out[14]
  PIN rw0_rd_out[15]
    DIRECTION OUTPUT ;
    USE SIGNAL ;
    SHAPE ABUTMENT ;
    PORT
      LAYER M3 ;
      RECT 28.287 0.000 28.305 0.054 ;
    END
  END rw0_rd_out[15]
  PIN rw0_rd_out[16]
    DIRECTION OUTPUT ;
    USE SIGNAL ;
    SHAPE ABUTMENT ;
    PORT
      LAYER M3 ;
      RECT 28.503 0.000 28.521 0.054 ;
    END
  END rw0_rd_out[16]
  PIN rw0_rd_out[17]
    DIRECTION OUTPUT ;
    USE SIGNAL ;
    SHAPE ABUTMENT ;
    PORT
      LAYER M3 ;
      RECT 28.719 0.000 28.737 0.054 ;
    END
  END rw0_rd_out[17]
  PIN rw0_rd_out[18]
    DIRECTION OUTPUT ;
    USE SIGNAL ;
    SHAPE ABUTMENT ;
    PORT
      LAYER M3 ;
      RECT 28.935 0.000 28.953 0.054 ;
    END
  END rw0_rd_out[18]
  PIN rw0_rd_out[19]
    DIRECTION OUTPUT ;
    USE SIGNAL ;
    SHAPE ABUTMENT ;
    PORT
      LAYER M3 ;
      RECT 29.151 0.000 29.169 0.054 ;
    END
  END rw0_rd_out[19]
  PIN rw0_rd_out[20]
    DIRECTION OUTPUT ;
    USE SIGNAL ;
    SHAPE ABUTMENT ;
    PORT
      LAYER M3 ;
      RECT 29.367 0.000 29.385 0.054 ;
    END
  END rw0_rd_out[20]
  PIN rw0_rd_out[21]
    DIRECTION OUTPUT ;
    USE SIGNAL ;
    SHAPE ABUTMENT ;
    PORT
      LAYER M3 ;
      RECT 29.583 0.000 29.601 0.054 ;
    END
  END rw0_rd_out[21]
  PIN rw0_rd_out[22]
    DIRECTION OUTPUT ;
    USE SIGNAL ;
    SHAPE ABUTMENT ;
    PORT
      LAYER M3 ;
      RECT 29.799 0.000 29.817 0.054 ;
    END
  END rw0_rd_out[22]
  PIN rw0_rd_out[23]
    DIRECTION OUTPUT ;
    USE SIGNAL ;
    SHAPE ABUTMENT ;
    PORT
      LAYER M3 ;
      RECT 30.015 0.000 30.033 0.054 ;
    END
  END rw0_rd_out[23]
  PIN rw0_rd_out[24]
    DIRECTION OUTPUT ;
    USE SIGNAL ;
    SHAPE ABUTMENT ;
    PORT
      LAYER M3 ;
      RECT 30.231 0.000 30.249 0.054 ;
    END
  END rw0_rd_out[24]
  PIN rw0_rd_out[25]
    DIRECTION OUTPUT ;
    USE SIGNAL ;
    SHAPE ABUTMENT ;
    PORT
      LAYER M3 ;
      RECT 30.447 0.000 30.465 0.054 ;
    END
  END rw0_rd_out[25]
  PIN rw0_rd_out[26]
    DIRECTION OUTPUT ;
    USE SIGNAL ;
    SHAPE ABUTMENT ;
    PORT
      LAYER M3 ;
      RECT 30.663 0.000 30.681 0.054 ;
    END
  END rw0_rd_out[26]
  PIN rw0_rd_out[27]
    DIRECTION OUTPUT ;
    USE SIGNAL ;
    SHAPE ABUTMENT ;
    PORT
      LAYER M3 ;
      RECT 30.879 0.000 30.897 0.054 ;
    END
  END rw0_rd_out[27]
  PIN rw0_rd_out[28]
    DIRECTION OUTPUT ;
    USE SIGNAL ;
    SHAPE ABUTMENT ;
    PORT
      LAYER M3 ;
      RECT 31.095 0.000 31.113 0.054 ;
    END
  END rw0_rd_out[28]
  PIN rw0_rd_out[29]
    DIRECTION OUTPUT ;
    USE SIGNAL ;
    SHAPE ABUTMENT ;
    PORT
      LAYER M3 ;
      RECT 31.311 0.000 31.329 0.054 ;
    END
  END rw0_rd_out[29]
  PIN rw0_rd_out[30]
    DIRECTION OUTPUT ;
    USE SIGNAL ;
    SHAPE ABUTMENT ;
    PORT
      LAYER M3 ;
      RECT 31.527 0.000 31.545 0.054 ;
    END
  END rw0_rd_out[30]
  PIN rw0_rd_out[31]
    DIRECTION OUTPUT ;
    USE SIGNAL ;
    SHAPE ABUTMENT ;
    PORT
      LAYER M3 ;
      RECT 31.743 0.000 31.761 0.054 ;
    END
  END rw0_rd_out[31]
  PIN rw0_rd_out[32]
    DIRECTION OUTPUT ;
    USE SIGNAL ;
    SHAPE ABUTMENT ;
    PORT
      LAYER M3 ;
      RECT 31.959 0.000 31.977 0.054 ;
    END
  END rw0_rd_out[32]
  PIN rw0_rd_out[33]
    DIRECTION OUTPUT ;
    USE SIGNAL ;
    SHAPE ABUTMENT ;
    PORT
      LAYER M3 ;
      RECT 32.175 0.000 32.193 0.054 ;
    END
  END rw0_rd_out[33]
  PIN rw0_rd_out[34]
    DIRECTION OUTPUT ;
    USE SIGNAL ;
    SHAPE ABUTMENT ;
    PORT
      LAYER M3 ;
      RECT 32.391 0.000 32.409 0.054 ;
    END
  END rw0_rd_out[34]
  PIN rw0_rd_out[35]
    DIRECTION OUTPUT ;
    USE SIGNAL ;
    SHAPE ABUTMENT ;
    PORT
      LAYER M3 ;
      RECT 32.607 0.000 32.625 0.054 ;
    END
  END rw0_rd_out[35]
  PIN rw0_rd_out[36]
    DIRECTION OUTPUT ;
    USE SIGNAL ;
    SHAPE ABUTMENT ;
    PORT
      LAYER M3 ;
      RECT 32.823 0.000 32.841 0.054 ;
    END
  END rw0_rd_out[36]
  PIN rw0_rd_out[37]
    DIRECTION OUTPUT ;
    USE SIGNAL ;
    SHAPE ABUTMENT ;
    PORT
      LAYER M3 ;
      RECT 33.039 0.000 33.057 0.054 ;
    END
  END rw0_rd_out[37]
  PIN rw0_rd_out[38]
    DIRECTION OUTPUT ;
    USE SIGNAL ;
    SHAPE ABUTMENT ;
    PORT
      LAYER M3 ;
      RECT 33.255 0.000 33.273 0.054 ;
    END
  END rw0_rd_out[38]
  PIN rw0_rd_out[39]
    DIRECTION OUTPUT ;
    USE SIGNAL ;
    SHAPE ABUTMENT ;
    PORT
      LAYER M3 ;
      RECT 33.471 0.000 33.489 0.054 ;
    END
  END rw0_rd_out[39]
  PIN rw0_rd_out[40]
    DIRECTION OUTPUT ;
    USE SIGNAL ;
    SHAPE ABUTMENT ;
    PORT
      LAYER M3 ;
      RECT 33.687 0.000 33.705 0.054 ;
    END
  END rw0_rd_out[40]
  PIN rw0_rd_out[41]
    DIRECTION OUTPUT ;
    USE SIGNAL ;
    SHAPE ABUTMENT ;
    PORT
      LAYER M3 ;
      RECT 33.903 0.000 33.921 0.054 ;
    END
  END rw0_rd_out[41]
  PIN rw0_rd_out[42]
    DIRECTION OUTPUT ;
    USE SIGNAL ;
    SHAPE ABUTMENT ;
    PORT
      LAYER M3 ;
      RECT 34.119 0.000 34.137 0.054 ;
    END
  END rw0_rd_out[42]
  PIN rw0_rd_out[43]
    DIRECTION OUTPUT ;
    USE SIGNAL ;
    SHAPE ABUTMENT ;
    PORT
      LAYER M3 ;
      RECT 34.335 0.000 34.353 0.054 ;
    END
  END rw0_rd_out[43]
  PIN rw0_rd_out[44]
    DIRECTION OUTPUT ;
    USE SIGNAL ;
    SHAPE ABUTMENT ;
    PORT
      LAYER M3 ;
      RECT 34.551 0.000 34.569 0.054 ;
    END
  END rw0_rd_out[44]
  PIN rw0_rd_out[45]
    DIRECTION OUTPUT ;
    USE SIGNAL ;
    SHAPE ABUTMENT ;
    PORT
      LAYER M3 ;
      RECT 34.767 0.000 34.785 0.054 ;
    END
  END rw0_rd_out[45]
  PIN rw0_rd_out[46]
    DIRECTION OUTPUT ;
    USE SIGNAL ;
    SHAPE ABUTMENT ;
    PORT
      LAYER M3 ;
      RECT 34.983 0.000 35.001 0.054 ;
    END
  END rw0_rd_out[46]
  PIN rw0_rd_out[47]
    DIRECTION OUTPUT ;
    USE SIGNAL ;
    SHAPE ABUTMENT ;
    PORT
      LAYER M3 ;
      RECT 35.199 0.000 35.217 0.054 ;
    END
  END rw0_rd_out[47]
  PIN rw0_rd_out[48]
    DIRECTION OUTPUT ;
    USE SIGNAL ;
    SHAPE ABUTMENT ;
    PORT
      LAYER M3 ;
      RECT 35.415 0.000 35.433 0.054 ;
    END
  END rw0_rd_out[48]
  PIN rw0_rd_out[49]
    DIRECTION OUTPUT ;
    USE SIGNAL ;
    SHAPE ABUTMENT ;
    PORT
      LAYER M3 ;
      RECT 35.631 0.000 35.649 0.054 ;
    END
  END rw0_rd_out[49]
  PIN rw0_rd_out[50]
    DIRECTION OUTPUT ;
    USE SIGNAL ;
    SHAPE ABUTMENT ;
    PORT
      LAYER M3 ;
      RECT 35.847 0.000 35.865 0.054 ;
    END
  END rw0_rd_out[50]
  PIN rw0_rd_out[51]
    DIRECTION OUTPUT ;
    USE SIGNAL ;
    SHAPE ABUTMENT ;
    PORT
      LAYER M3 ;
      RECT 36.063 0.000 36.081 0.054 ;
    END
  END rw0_rd_out[51]
  PIN rw0_rd_out[52]
    DIRECTION OUTPUT ;
    USE SIGNAL ;
    SHAPE ABUTMENT ;
    PORT
      LAYER M3 ;
      RECT 36.279 0.000 36.297 0.054 ;
    END
  END rw0_rd_out[52]
  PIN rw0_rd_out[53]
    DIRECTION OUTPUT ;
    USE SIGNAL ;
    SHAPE ABUTMENT ;
    PORT
      LAYER M3 ;
      RECT 36.495 0.000 36.513 0.054 ;
    END
  END rw0_rd_out[53]
  PIN rw0_rd_out[54]
    DIRECTION OUTPUT ;
    USE SIGNAL ;
    SHAPE ABUTMENT ;
    PORT
      LAYER M3 ;
      RECT 36.711 0.000 36.729 0.054 ;
    END
  END rw0_rd_out[54]
  PIN rw0_rd_out[55]
    DIRECTION OUTPUT ;
    USE SIGNAL ;
    SHAPE ABUTMENT ;
    PORT
      LAYER M3 ;
      RECT 36.927 0.000 36.945 0.054 ;
    END
  END rw0_rd_out[55]
  PIN rw0_rd_out[56]
    DIRECTION OUTPUT ;
    USE SIGNAL ;
    SHAPE ABUTMENT ;
    PORT
      LAYER M3 ;
      RECT 37.143 0.000 37.161 0.054 ;
    END
  END rw0_rd_out[56]
  PIN rw0_rd_out[57]
    DIRECTION OUTPUT ;
    USE SIGNAL ;
    SHAPE ABUTMENT ;
    PORT
      LAYER M3 ;
      RECT 37.359 0.000 37.377 0.054 ;
    END
  END rw0_rd_out[57]
  PIN rw0_rd_out[58]
    DIRECTION OUTPUT ;
    USE SIGNAL ;
    SHAPE ABUTMENT ;
    PORT
      LAYER M3 ;
      RECT 37.575 0.000 37.593 0.054 ;
    END
  END rw0_rd_out[58]
  PIN rw0_rd_out[59]
    DIRECTION OUTPUT ;
    USE SIGNAL ;
    SHAPE ABUTMENT ;
    PORT
      LAYER M3 ;
      RECT 37.791 0.000 37.809 0.054 ;
    END
  END rw0_rd_out[59]
  PIN rw0_rd_out[60]
    DIRECTION OUTPUT ;
    USE SIGNAL ;
    SHAPE ABUTMENT ;
    PORT
      LAYER M3 ;
      RECT 38.007 0.000 38.025 0.054 ;
    END
  END rw0_rd_out[60]
  PIN rw0_rd_out[61]
    DIRECTION OUTPUT ;
    USE SIGNAL ;
    SHAPE ABUTMENT ;
    PORT
      LAYER M3 ;
      RECT 38.223 0.000 38.241 0.054 ;
    END
  END rw0_rd_out[61]
  PIN rw0_rd_out[62]
    DIRECTION OUTPUT ;
    USE SIGNAL ;
    SHAPE ABUTMENT ;
    PORT
      LAYER M3 ;
      RECT 38.439 0.000 38.457 0.054 ;
    END
  END rw0_rd_out[62]
  PIN rw0_rd_out[63]
    DIRECTION OUTPUT ;
    USE SIGNAL ;
    SHAPE ABUTMENT ;
    PORT
      LAYER M3 ;
      RECT 38.655 0.000 38.673 0.054 ;
    END
  END rw0_rd_out[63]
  PIN rw0_rd_out[64]
    DIRECTION OUTPUT ;
    USE SIGNAL ;
    SHAPE ABUTMENT ;
    PORT
      LAYER M3 ;
      RECT 38.871 0.000 38.889 0.054 ;
    END
  END rw0_rd_out[64]
  PIN rw0_rd_out[65]
    DIRECTION OUTPUT ;
    USE SIGNAL ;
    SHAPE ABUTMENT ;
    PORT
      LAYER M3 ;
      RECT 39.087 0.000 39.105 0.054 ;
    END
  END rw0_rd_out[65]
  PIN rw0_rd_out[66]
    DIRECTION OUTPUT ;
    USE SIGNAL ;
    SHAPE ABUTMENT ;
    PORT
      LAYER M3 ;
      RECT 39.303 0.000 39.321 0.054 ;
    END
  END rw0_rd_out[66]
  PIN rw0_rd_out[67]
    DIRECTION OUTPUT ;
    USE SIGNAL ;
    SHAPE ABUTMENT ;
    PORT
      LAYER M3 ;
      RECT 39.519 0.000 39.537 0.054 ;
    END
  END rw0_rd_out[67]
  PIN rw0_rd_out[68]
    DIRECTION OUTPUT ;
    USE SIGNAL ;
    SHAPE ABUTMENT ;
    PORT
      LAYER M3 ;
      RECT 39.735 0.000 39.753 0.054 ;
    END
  END rw0_rd_out[68]
  PIN rw0_rd_out[69]
    DIRECTION OUTPUT ;
    USE SIGNAL ;
    SHAPE ABUTMENT ;
    PORT
      LAYER M3 ;
      RECT 39.951 0.000 39.969 0.054 ;
    END
  END rw0_rd_out[69]
  PIN rw0_rd_out[70]
    DIRECTION OUTPUT ;
    USE SIGNAL ;
    SHAPE ABUTMENT ;
    PORT
      LAYER M3 ;
      RECT 40.167 0.000 40.185 0.054 ;
    END
  END rw0_rd_out[70]
  PIN rw0_rd_out[71]
    DIRECTION OUTPUT ;
    USE SIGNAL ;
    SHAPE ABUTMENT ;
    PORT
      LAYER M3 ;
      RECT 40.383 0.000 40.401 0.054 ;
    END
  END rw0_rd_out[71]
  PIN rw0_rd_out[72]
    DIRECTION OUTPUT ;
    USE SIGNAL ;
    SHAPE ABUTMENT ;
    PORT
      LAYER M3 ;
      RECT 40.599 0.000 40.617 0.054 ;
    END
  END rw0_rd_out[72]
  PIN rw0_rd_out[73]
    DIRECTION OUTPUT ;
    USE SIGNAL ;
    SHAPE ABUTMENT ;
    PORT
      LAYER M3 ;
      RECT 40.815 0.000 40.833 0.054 ;
    END
  END rw0_rd_out[73]
  PIN rw0_rd_out[74]
    DIRECTION OUTPUT ;
    USE SIGNAL ;
    SHAPE ABUTMENT ;
    PORT
      LAYER M3 ;
      RECT 41.031 0.000 41.049 0.054 ;
    END
  END rw0_rd_out[74]
  PIN rw0_rd_out[75]
    DIRECTION OUTPUT ;
    USE SIGNAL ;
    SHAPE ABUTMENT ;
    PORT
      LAYER M3 ;
      RECT 41.247 0.000 41.265 0.054 ;
    END
  END rw0_rd_out[75]
  PIN rw0_rd_out[76]
    DIRECTION OUTPUT ;
    USE SIGNAL ;
    SHAPE ABUTMENT ;
    PORT
      LAYER M3 ;
      RECT 41.463 0.000 41.481 0.054 ;
    END
  END rw0_rd_out[76]
  PIN rw0_rd_out[77]
    DIRECTION OUTPUT ;
    USE SIGNAL ;
    SHAPE ABUTMENT ;
    PORT
      LAYER M3 ;
      RECT 41.679 0.000 41.697 0.054 ;
    END
  END rw0_rd_out[77]
  PIN rw0_rd_out[78]
    DIRECTION OUTPUT ;
    USE SIGNAL ;
    SHAPE ABUTMENT ;
    PORT
      LAYER M3 ;
      RECT 41.895 0.000 41.913 0.054 ;
    END
  END rw0_rd_out[78]
  PIN rw0_rd_out[79]
    DIRECTION OUTPUT ;
    USE SIGNAL ;
    SHAPE ABUTMENT ;
    PORT
      LAYER M3 ;
      RECT 42.111 0.000 42.129 0.054 ;
    END
  END rw0_rd_out[79]
  PIN rw0_rd_out[80]
    DIRECTION OUTPUT ;
    USE SIGNAL ;
    SHAPE ABUTMENT ;
    PORT
      LAYER M3 ;
      RECT 42.327 0.000 42.345 0.054 ;
    END
  END rw0_rd_out[80]
  PIN rw0_rd_out[81]
    DIRECTION OUTPUT ;
    USE SIGNAL ;
    SHAPE ABUTMENT ;
    PORT
      LAYER M3 ;
      RECT 42.543 0.000 42.561 0.054 ;
    END
  END rw0_rd_out[81]
  PIN rw0_rd_out[82]
    DIRECTION OUTPUT ;
    USE SIGNAL ;
    SHAPE ABUTMENT ;
    PORT
      LAYER M3 ;
      RECT 42.759 0.000 42.777 0.054 ;
    END
  END rw0_rd_out[82]
  PIN rw0_rd_out[83]
    DIRECTION OUTPUT ;
    USE SIGNAL ;
    SHAPE ABUTMENT ;
    PORT
      LAYER M3 ;
      RECT 42.975 0.000 42.993 0.054 ;
    END
  END rw0_rd_out[83]
  PIN rw0_rd_out[84]
    DIRECTION OUTPUT ;
    USE SIGNAL ;
    SHAPE ABUTMENT ;
    PORT
      LAYER M3 ;
      RECT 43.191 0.000 43.209 0.054 ;
    END
  END rw0_rd_out[84]
  PIN rw0_rd_out[85]
    DIRECTION OUTPUT ;
    USE SIGNAL ;
    SHAPE ABUTMENT ;
    PORT
      LAYER M3 ;
      RECT 43.407 0.000 43.425 0.054 ;
    END
  END rw0_rd_out[85]
  PIN rw0_rd_out[86]
    DIRECTION OUTPUT ;
    USE SIGNAL ;
    SHAPE ABUTMENT ;
    PORT
      LAYER M3 ;
      RECT 43.623 0.000 43.641 0.054 ;
    END
  END rw0_rd_out[86]
  PIN rw0_rd_out[87]
    DIRECTION OUTPUT ;
    USE SIGNAL ;
    SHAPE ABUTMENT ;
    PORT
      LAYER M3 ;
      RECT 43.839 0.000 43.857 0.054 ;
    END
  END rw0_rd_out[87]
  PIN rw0_rd_out[88]
    DIRECTION OUTPUT ;
    USE SIGNAL ;
    SHAPE ABUTMENT ;
    PORT
      LAYER M3 ;
      RECT 44.055 0.000 44.073 0.054 ;
    END
  END rw0_rd_out[88]
  PIN rw0_rd_out[89]
    DIRECTION OUTPUT ;
    USE SIGNAL ;
    SHAPE ABUTMENT ;
    PORT
      LAYER M3 ;
      RECT 44.271 0.000 44.289 0.054 ;
    END
  END rw0_rd_out[89]
  PIN rw0_rd_out[90]
    DIRECTION OUTPUT ;
    USE SIGNAL ;
    SHAPE ABUTMENT ;
    PORT
      LAYER M3 ;
      RECT 44.487 0.000 44.505 0.054 ;
    END
  END rw0_rd_out[90]
  PIN rw0_rd_out[91]
    DIRECTION OUTPUT ;
    USE SIGNAL ;
    SHAPE ABUTMENT ;
    PORT
      LAYER M3 ;
      RECT 44.703 0.000 44.721 0.054 ;
    END
  END rw0_rd_out[91]
  PIN rw0_rd_out[92]
    DIRECTION OUTPUT ;
    USE SIGNAL ;
    SHAPE ABUTMENT ;
    PORT
      LAYER M3 ;
      RECT 44.919 0.000 44.937 0.054 ;
    END
  END rw0_rd_out[92]
  PIN rw0_rd_out[93]
    DIRECTION OUTPUT ;
    USE SIGNAL ;
    SHAPE ABUTMENT ;
    PORT
      LAYER M3 ;
      RECT 45.135 0.000 45.153 0.054 ;
    END
  END rw0_rd_out[93]
  PIN rw0_rd_out[94]
    DIRECTION OUTPUT ;
    USE SIGNAL ;
    SHAPE ABUTMENT ;
    PORT
      LAYER M3 ;
      RECT 45.351 0.000 45.369 0.054 ;
    END
  END rw0_rd_out[94]
  PIN rw0_rd_out[95]
    DIRECTION OUTPUT ;
    USE SIGNAL ;
    SHAPE ABUTMENT ;
    PORT
      LAYER M3 ;
      RECT 45.567 0.000 45.585 0.054 ;
    END
  END rw0_rd_out[95]
  PIN rw0_rd_out[96]
    DIRECTION OUTPUT ;
    USE SIGNAL ;
    SHAPE ABUTMENT ;
    PORT
      LAYER M3 ;
      RECT 45.783 0.000 45.801 0.054 ;
    END
  END rw0_rd_out[96]
  PIN rw0_rd_out[97]
    DIRECTION OUTPUT ;
    USE SIGNAL ;
    SHAPE ABUTMENT ;
    PORT
      LAYER M3 ;
      RECT 45.999 0.000 46.017 0.054 ;
    END
  END rw0_rd_out[97]
  PIN rw0_rd_out[98]
    DIRECTION OUTPUT ;
    USE SIGNAL ;
    SHAPE ABUTMENT ;
    PORT
      LAYER M3 ;
      RECT 46.215 0.000 46.233 0.054 ;
    END
  END rw0_rd_out[98]
  PIN rw0_rd_out[99]
    DIRECTION OUTPUT ;
    USE SIGNAL ;
    SHAPE ABUTMENT ;
    PORT
      LAYER M3 ;
      RECT 46.431 0.000 46.449 0.054 ;
    END
  END rw0_rd_out[99]
  PIN rw0_rd_out[100]
    DIRECTION OUTPUT ;
    USE SIGNAL ;
    SHAPE ABUTMENT ;
    PORT
      LAYER M3 ;
      RECT 46.647 0.000 46.665 0.054 ;
    END
  END rw0_rd_out[100]
  PIN rw0_rd_out[101]
    DIRECTION OUTPUT ;
    USE SIGNAL ;
    SHAPE ABUTMENT ;
    PORT
      LAYER M3 ;
      RECT 46.863 0.000 46.881 0.054 ;
    END
  END rw0_rd_out[101]
  PIN rw0_rd_out[102]
    DIRECTION OUTPUT ;
    USE SIGNAL ;
    SHAPE ABUTMENT ;
    PORT
      LAYER M3 ;
      RECT 47.079 0.000 47.097 0.054 ;
    END
  END rw0_rd_out[102]
  PIN rw0_rd_out[103]
    DIRECTION OUTPUT ;
    USE SIGNAL ;
    SHAPE ABUTMENT ;
    PORT
      LAYER M3 ;
      RECT 47.295 0.000 47.313 0.054 ;
    END
  END rw0_rd_out[103]
  PIN rw0_rd_out[104]
    DIRECTION OUTPUT ;
    USE SIGNAL ;
    SHAPE ABUTMENT ;
    PORT
      LAYER M3 ;
      RECT 47.511 0.000 47.529 0.054 ;
    END
  END rw0_rd_out[104]
  PIN rw0_rd_out[105]
    DIRECTION OUTPUT ;
    USE SIGNAL ;
    SHAPE ABUTMENT ;
    PORT
      LAYER M3 ;
      RECT 47.727 0.000 47.745 0.054 ;
    END
  END rw0_rd_out[105]
  PIN rw0_rd_out[106]
    DIRECTION OUTPUT ;
    USE SIGNAL ;
    SHAPE ABUTMENT ;
    PORT
      LAYER M3 ;
      RECT 47.943 0.000 47.961 0.054 ;
    END
  END rw0_rd_out[106]
  PIN rw0_rd_out[107]
    DIRECTION OUTPUT ;
    USE SIGNAL ;
    SHAPE ABUTMENT ;
    PORT
      LAYER M3 ;
      RECT 48.159 0.000 48.177 0.054 ;
    END
  END rw0_rd_out[107]
  PIN rw0_rd_out[108]
    DIRECTION OUTPUT ;
    USE SIGNAL ;
    SHAPE ABUTMENT ;
    PORT
      LAYER M3 ;
      RECT 48.375 0.000 48.393 0.054 ;
    END
  END rw0_rd_out[108]
  PIN rw0_rd_out[109]
    DIRECTION OUTPUT ;
    USE SIGNAL ;
    SHAPE ABUTMENT ;
    PORT
      LAYER M3 ;
      RECT 48.591 0.000 48.609 0.054 ;
    END
  END rw0_rd_out[109]
  PIN rw0_rd_out[110]
    DIRECTION OUTPUT ;
    USE SIGNAL ;
    SHAPE ABUTMENT ;
    PORT
      LAYER M3 ;
      RECT 48.807 0.000 48.825 0.054 ;
    END
  END rw0_rd_out[110]
  PIN rw0_rd_out[111]
    DIRECTION OUTPUT ;
    USE SIGNAL ;
    SHAPE ABUTMENT ;
    PORT
      LAYER M3 ;
      RECT 49.023 0.000 49.041 0.054 ;
    END
  END rw0_rd_out[111]
  PIN rw0_rd_out[112]
    DIRECTION OUTPUT ;
    USE SIGNAL ;
    SHAPE ABUTMENT ;
    PORT
      LAYER M3 ;
      RECT 49.239 0.000 49.257 0.054 ;
    END
  END rw0_rd_out[112]
  PIN rw0_rd_out[113]
    DIRECTION OUTPUT ;
    USE SIGNAL ;
    SHAPE ABUTMENT ;
    PORT
      LAYER M3 ;
      RECT 49.455 0.000 49.473 0.054 ;
    END
  END rw0_rd_out[113]
  PIN rw0_rd_out[114]
    DIRECTION OUTPUT ;
    USE SIGNAL ;
    SHAPE ABUTMENT ;
    PORT
      LAYER M3 ;
      RECT 49.671 0.000 49.689 0.054 ;
    END
  END rw0_rd_out[114]
  PIN rw0_rd_out[115]
    DIRECTION OUTPUT ;
    USE SIGNAL ;
    SHAPE ABUTMENT ;
    PORT
      LAYER M3 ;
      RECT 0.207 44.561 0.225 44.615 ;
    END
  END rw0_rd_out[115]
  PIN rw0_rd_out[116]
    DIRECTION OUTPUT ;
    USE SIGNAL ;
    SHAPE ABUTMENT ;
    PORT
      LAYER M3 ;
      RECT 0.495 44.561 0.513 44.615 ;
    END
  END rw0_rd_out[116]
  PIN rw0_rd_out[117]
    DIRECTION OUTPUT ;
    USE SIGNAL ;
    SHAPE ABUTMENT ;
    PORT
      LAYER M3 ;
      RECT 0.783 44.561 0.801 44.615 ;
    END
  END rw0_rd_out[117]
  PIN rw0_rd_out[118]
    DIRECTION OUTPUT ;
    USE SIGNAL ;
    SHAPE ABUTMENT ;
    PORT
      LAYER M3 ;
      RECT 1.071 44.561 1.089 44.615 ;
    END
  END rw0_rd_out[118]
  PIN rw0_rd_out[119]
    DIRECTION OUTPUT ;
    USE SIGNAL ;
    SHAPE ABUTMENT ;
    PORT
      LAYER M3 ;
      RECT 1.359 44.561 1.377 44.615 ;
    END
  END rw0_rd_out[119]
  PIN rw0_rd_out[120]
    DIRECTION OUTPUT ;
    USE SIGNAL ;
    SHAPE ABUTMENT ;
    PORT
      LAYER M3 ;
      RECT 1.647 44.561 1.665 44.615 ;
    END
  END rw0_rd_out[120]
  PIN rw0_rd_out[121]
    DIRECTION OUTPUT ;
    USE SIGNAL ;
    SHAPE ABUTMENT ;
    PORT
      LAYER M3 ;
      RECT 1.935 44.561 1.953 44.615 ;
    END
  END rw0_rd_out[121]
  PIN rw0_rd_out[122]
    DIRECTION OUTPUT ;
    USE SIGNAL ;
    SHAPE ABUTMENT ;
    PORT
      LAYER M3 ;
      RECT 2.223 44.561 2.241 44.615 ;
    END
  END rw0_rd_out[122]
  PIN rw0_rd_out[123]
    DIRECTION OUTPUT ;
    USE SIGNAL ;
    SHAPE ABUTMENT ;
    PORT
      LAYER M3 ;
      RECT 2.511 44.561 2.529 44.615 ;
    END
  END rw0_rd_out[123]
  PIN rw0_rd_out[124]
    DIRECTION OUTPUT ;
    USE SIGNAL ;
    SHAPE ABUTMENT ;
    PORT
      LAYER M3 ;
      RECT 2.799 44.561 2.817 44.615 ;
    END
  END rw0_rd_out[124]
  PIN rw0_rd_out[125]
    DIRECTION OUTPUT ;
    USE SIGNAL ;
    SHAPE ABUTMENT ;
    PORT
      LAYER M3 ;
      RECT 3.087 44.561 3.105 44.615 ;
    END
  END rw0_rd_out[125]
  PIN rw0_rd_out[126]
    DIRECTION OUTPUT ;
    USE SIGNAL ;
    SHAPE ABUTMENT ;
    PORT
      LAYER M3 ;
      RECT 3.375 44.561 3.393 44.615 ;
    END
  END rw0_rd_out[126]
  PIN rw0_rd_out[127]
    DIRECTION OUTPUT ;
    USE SIGNAL ;
    SHAPE ABUTMENT ;
    PORT
      LAYER M3 ;
      RECT 3.663 44.561 3.681 44.615 ;
    END
  END rw0_rd_out[127]
  PIN rw0_rd_out[128]
    DIRECTION OUTPUT ;
    USE SIGNAL ;
    SHAPE ABUTMENT ;
    PORT
      LAYER M3 ;
      RECT 3.951 44.561 3.969 44.615 ;
    END
  END rw0_rd_out[128]
  PIN rw0_rd_out[129]
    DIRECTION OUTPUT ;
    USE SIGNAL ;
    SHAPE ABUTMENT ;
    PORT
      LAYER M3 ;
      RECT 4.239 44.561 4.257 44.615 ;
    END
  END rw0_rd_out[129]
  PIN rw0_rd_out[130]
    DIRECTION OUTPUT ;
    USE SIGNAL ;
    SHAPE ABUTMENT ;
    PORT
      LAYER M3 ;
      RECT 4.527 44.561 4.545 44.615 ;
    END
  END rw0_rd_out[130]
  PIN rw0_rd_out[131]
    DIRECTION OUTPUT ;
    USE SIGNAL ;
    SHAPE ABUTMENT ;
    PORT
      LAYER M3 ;
      RECT 4.815 44.561 4.833 44.615 ;
    END
  END rw0_rd_out[131]
  PIN rw0_rd_out[132]
    DIRECTION OUTPUT ;
    USE SIGNAL ;
    SHAPE ABUTMENT ;
    PORT
      LAYER M3 ;
      RECT 5.103 44.561 5.121 44.615 ;
    END
  END rw0_rd_out[132]
  PIN rw0_rd_out[133]
    DIRECTION OUTPUT ;
    USE SIGNAL ;
    SHAPE ABUTMENT ;
    PORT
      LAYER M3 ;
      RECT 5.391 44.561 5.409 44.615 ;
    END
  END rw0_rd_out[133]
  PIN rw0_rd_out[134]
    DIRECTION OUTPUT ;
    USE SIGNAL ;
    SHAPE ABUTMENT ;
    PORT
      LAYER M3 ;
      RECT 5.679 44.561 5.697 44.615 ;
    END
  END rw0_rd_out[134]
  PIN rw0_rd_out[135]
    DIRECTION OUTPUT ;
    USE SIGNAL ;
    SHAPE ABUTMENT ;
    PORT
      LAYER M3 ;
      RECT 5.967 44.561 5.985 44.615 ;
    END
  END rw0_rd_out[135]
  PIN rw0_rd_out[136]
    DIRECTION OUTPUT ;
    USE SIGNAL ;
    SHAPE ABUTMENT ;
    PORT
      LAYER M3 ;
      RECT 6.255 44.561 6.273 44.615 ;
    END
  END rw0_rd_out[136]
  PIN rw0_rd_out[137]
    DIRECTION OUTPUT ;
    USE SIGNAL ;
    SHAPE ABUTMENT ;
    PORT
      LAYER M3 ;
      RECT 6.543 44.561 6.561 44.615 ;
    END
  END rw0_rd_out[137]
  PIN rw0_rd_out[138]
    DIRECTION OUTPUT ;
    USE SIGNAL ;
    SHAPE ABUTMENT ;
    PORT
      LAYER M3 ;
      RECT 6.831 44.561 6.849 44.615 ;
    END
  END rw0_rd_out[138]
  PIN rw0_rd_out[139]
    DIRECTION OUTPUT ;
    USE SIGNAL ;
    SHAPE ABUTMENT ;
    PORT
      LAYER M3 ;
      RECT 7.119 44.561 7.137 44.615 ;
    END
  END rw0_rd_out[139]
  PIN rw0_rd_out[140]
    DIRECTION OUTPUT ;
    USE SIGNAL ;
    SHAPE ABUTMENT ;
    PORT
      LAYER M3 ;
      RECT 7.407 44.561 7.425 44.615 ;
    END
  END rw0_rd_out[140]
  PIN rw0_rd_out[141]
    DIRECTION OUTPUT ;
    USE SIGNAL ;
    SHAPE ABUTMENT ;
    PORT
      LAYER M3 ;
      RECT 7.695 44.561 7.713 44.615 ;
    END
  END rw0_rd_out[141]
  PIN rw0_rd_out[142]
    DIRECTION OUTPUT ;
    USE SIGNAL ;
    SHAPE ABUTMENT ;
    PORT
      LAYER M3 ;
      RECT 7.983 44.561 8.001 44.615 ;
    END
  END rw0_rd_out[142]
  PIN rw0_rd_out[143]
    DIRECTION OUTPUT ;
    USE SIGNAL ;
    SHAPE ABUTMENT ;
    PORT
      LAYER M3 ;
      RECT 8.271 44.561 8.289 44.615 ;
    END
  END rw0_rd_out[143]
  PIN rw0_rd_out[144]
    DIRECTION OUTPUT ;
    USE SIGNAL ;
    SHAPE ABUTMENT ;
    PORT
      LAYER M3 ;
      RECT 8.559 44.561 8.577 44.615 ;
    END
  END rw0_rd_out[144]
  PIN rw0_rd_out[145]
    DIRECTION OUTPUT ;
    USE SIGNAL ;
    SHAPE ABUTMENT ;
    PORT
      LAYER M3 ;
      RECT 8.847 44.561 8.865 44.615 ;
    END
  END rw0_rd_out[145]
  PIN rw0_rd_out[146]
    DIRECTION OUTPUT ;
    USE SIGNAL ;
    SHAPE ABUTMENT ;
    PORT
      LAYER M3 ;
      RECT 9.135 44.561 9.153 44.615 ;
    END
  END rw0_rd_out[146]
  PIN rw0_rd_out[147]
    DIRECTION OUTPUT ;
    USE SIGNAL ;
    SHAPE ABUTMENT ;
    PORT
      LAYER M3 ;
      RECT 9.423 44.561 9.441 44.615 ;
    END
  END rw0_rd_out[147]
  PIN rw0_rd_out[148]
    DIRECTION OUTPUT ;
    USE SIGNAL ;
    SHAPE ABUTMENT ;
    PORT
      LAYER M3 ;
      RECT 9.711 44.561 9.729 44.615 ;
    END
  END rw0_rd_out[148]
  PIN rw0_rd_out[149]
    DIRECTION OUTPUT ;
    USE SIGNAL ;
    SHAPE ABUTMENT ;
    PORT
      LAYER M3 ;
      RECT 9.999 44.561 10.017 44.615 ;
    END
  END rw0_rd_out[149]
  PIN rw0_rd_out[150]
    DIRECTION OUTPUT ;
    USE SIGNAL ;
    SHAPE ABUTMENT ;
    PORT
      LAYER M3 ;
      RECT 10.287 44.561 10.305 44.615 ;
    END
  END rw0_rd_out[150]
  PIN rw0_rd_out[151]
    DIRECTION OUTPUT ;
    USE SIGNAL ;
    SHAPE ABUTMENT ;
    PORT
      LAYER M3 ;
      RECT 10.575 44.561 10.593 44.615 ;
    END
  END rw0_rd_out[151]
  PIN rw0_rd_out[152]
    DIRECTION OUTPUT ;
    USE SIGNAL ;
    SHAPE ABUTMENT ;
    PORT
      LAYER M3 ;
      RECT 10.863 44.561 10.881 44.615 ;
    END
  END rw0_rd_out[152]
  PIN rw0_rd_out[153]
    DIRECTION OUTPUT ;
    USE SIGNAL ;
    SHAPE ABUTMENT ;
    PORT
      LAYER M3 ;
      RECT 11.151 44.561 11.169 44.615 ;
    END
  END rw0_rd_out[153]
  PIN rw0_rd_out[154]
    DIRECTION OUTPUT ;
    USE SIGNAL ;
    SHAPE ABUTMENT ;
    PORT
      LAYER M3 ;
      RECT 11.439 44.561 11.457 44.615 ;
    END
  END rw0_rd_out[154]
  PIN rw0_rd_out[155]
    DIRECTION OUTPUT ;
    USE SIGNAL ;
    SHAPE ABUTMENT ;
    PORT
      LAYER M3 ;
      RECT 11.727 44.561 11.745 44.615 ;
    END
  END rw0_rd_out[155]
  PIN rw0_rd_out[156]
    DIRECTION OUTPUT ;
    USE SIGNAL ;
    SHAPE ABUTMENT ;
    PORT
      LAYER M3 ;
      RECT 12.015 44.561 12.033 44.615 ;
    END
  END rw0_rd_out[156]
  PIN rw0_rd_out[157]
    DIRECTION OUTPUT ;
    USE SIGNAL ;
    SHAPE ABUTMENT ;
    PORT
      LAYER M3 ;
      RECT 12.303 44.561 12.321 44.615 ;
    END
  END rw0_rd_out[157]
  PIN rw0_rd_out[158]
    DIRECTION OUTPUT ;
    USE SIGNAL ;
    SHAPE ABUTMENT ;
    PORT
      LAYER M3 ;
      RECT 12.591 44.561 12.609 44.615 ;
    END
  END rw0_rd_out[158]
  PIN rw0_rd_out[159]
    DIRECTION OUTPUT ;
    USE SIGNAL ;
    SHAPE ABUTMENT ;
    PORT
      LAYER M3 ;
      RECT 12.879 44.561 12.897 44.615 ;
    END
  END rw0_rd_out[159]
  PIN rw0_rd_out[160]
    DIRECTION OUTPUT ;
    USE SIGNAL ;
    SHAPE ABUTMENT ;
    PORT
      LAYER M3 ;
      RECT 13.167 44.561 13.185 44.615 ;
    END
  END rw0_rd_out[160]
  PIN rw0_rd_out[161]
    DIRECTION OUTPUT ;
    USE SIGNAL ;
    SHAPE ABUTMENT ;
    PORT
      LAYER M3 ;
      RECT 13.455 44.561 13.473 44.615 ;
    END
  END rw0_rd_out[161]
  PIN rw0_rd_out[162]
    DIRECTION OUTPUT ;
    USE SIGNAL ;
    SHAPE ABUTMENT ;
    PORT
      LAYER M3 ;
      RECT 13.743 44.561 13.761 44.615 ;
    END
  END rw0_rd_out[162]
  PIN rw0_rd_out[163]
    DIRECTION OUTPUT ;
    USE SIGNAL ;
    SHAPE ABUTMENT ;
    PORT
      LAYER M3 ;
      RECT 14.031 44.561 14.049 44.615 ;
    END
  END rw0_rd_out[163]
  PIN rw0_rd_out[164]
    DIRECTION OUTPUT ;
    USE SIGNAL ;
    SHAPE ABUTMENT ;
    PORT
      LAYER M3 ;
      RECT 14.319 44.561 14.337 44.615 ;
    END
  END rw0_rd_out[164]
  PIN rw0_rd_out[165]
    DIRECTION OUTPUT ;
    USE SIGNAL ;
    SHAPE ABUTMENT ;
    PORT
      LAYER M3 ;
      RECT 14.607 44.561 14.625 44.615 ;
    END
  END rw0_rd_out[165]
  PIN rw0_rd_out[166]
    DIRECTION OUTPUT ;
    USE SIGNAL ;
    SHAPE ABUTMENT ;
    PORT
      LAYER M3 ;
      RECT 14.895 44.561 14.913 44.615 ;
    END
  END rw0_rd_out[166]
  PIN rw0_rd_out[167]
    DIRECTION OUTPUT ;
    USE SIGNAL ;
    SHAPE ABUTMENT ;
    PORT
      LAYER M3 ;
      RECT 15.183 44.561 15.201 44.615 ;
    END
  END rw0_rd_out[167]
  PIN rw0_rd_out[168]
    DIRECTION OUTPUT ;
    USE SIGNAL ;
    SHAPE ABUTMENT ;
    PORT
      LAYER M3 ;
      RECT 15.471 44.561 15.489 44.615 ;
    END
  END rw0_rd_out[168]
  PIN rw0_rd_out[169]
    DIRECTION OUTPUT ;
    USE SIGNAL ;
    SHAPE ABUTMENT ;
    PORT
      LAYER M3 ;
      RECT 15.759 44.561 15.777 44.615 ;
    END
  END rw0_rd_out[169]
  PIN rw0_rd_out[170]
    DIRECTION OUTPUT ;
    USE SIGNAL ;
    SHAPE ABUTMENT ;
    PORT
      LAYER M3 ;
      RECT 16.047 44.561 16.065 44.615 ;
    END
  END rw0_rd_out[170]
  PIN rw0_rd_out[171]
    DIRECTION OUTPUT ;
    USE SIGNAL ;
    SHAPE ABUTMENT ;
    PORT
      LAYER M3 ;
      RECT 16.335 44.561 16.353 44.615 ;
    END
  END rw0_rd_out[171]
  PIN rw0_rd_out[172]
    DIRECTION OUTPUT ;
    USE SIGNAL ;
    SHAPE ABUTMENT ;
    PORT
      LAYER M3 ;
      RECT 16.623 44.561 16.641 44.615 ;
    END
  END rw0_rd_out[172]
  PIN rw0_rd_out[173]
    DIRECTION OUTPUT ;
    USE SIGNAL ;
    SHAPE ABUTMENT ;
    PORT
      LAYER M3 ;
      RECT 16.911 44.561 16.929 44.615 ;
    END
  END rw0_rd_out[173]
  PIN rw0_rd_out[174]
    DIRECTION OUTPUT ;
    USE SIGNAL ;
    SHAPE ABUTMENT ;
    PORT
      LAYER M3 ;
      RECT 17.199 44.561 17.217 44.615 ;
    END
  END rw0_rd_out[174]
  PIN rw0_rd_out[175]
    DIRECTION OUTPUT ;
    USE SIGNAL ;
    SHAPE ABUTMENT ;
    PORT
      LAYER M3 ;
      RECT 17.487 44.561 17.505 44.615 ;
    END
  END rw0_rd_out[175]
  PIN rw0_rd_out[176]
    DIRECTION OUTPUT ;
    USE SIGNAL ;
    SHAPE ABUTMENT ;
    PORT
      LAYER M3 ;
      RECT 17.775 44.561 17.793 44.615 ;
    END
  END rw0_rd_out[176]
  PIN rw0_rd_out[177]
    DIRECTION OUTPUT ;
    USE SIGNAL ;
    SHAPE ABUTMENT ;
    PORT
      LAYER M3 ;
      RECT 18.063 44.561 18.081 44.615 ;
    END
  END rw0_rd_out[177]
  PIN rw0_rd_out[178]
    DIRECTION OUTPUT ;
    USE SIGNAL ;
    SHAPE ABUTMENT ;
    PORT
      LAYER M3 ;
      RECT 18.351 44.561 18.369 44.615 ;
    END
  END rw0_rd_out[178]
  PIN rw0_rd_out[179]
    DIRECTION OUTPUT ;
    USE SIGNAL ;
    SHAPE ABUTMENT ;
    PORT
      LAYER M3 ;
      RECT 18.639 44.561 18.657 44.615 ;
    END
  END rw0_rd_out[179]
  PIN rw0_rd_out[180]
    DIRECTION OUTPUT ;
    USE SIGNAL ;
    SHAPE ABUTMENT ;
    PORT
      LAYER M3 ;
      RECT 18.927 44.561 18.945 44.615 ;
    END
  END rw0_rd_out[180]
  PIN rw0_rd_out[181]
    DIRECTION OUTPUT ;
    USE SIGNAL ;
    SHAPE ABUTMENT ;
    PORT
      LAYER M3 ;
      RECT 19.215 44.561 19.233 44.615 ;
    END
  END rw0_rd_out[181]
  PIN rw0_rd_out[182]
    DIRECTION OUTPUT ;
    USE SIGNAL ;
    SHAPE ABUTMENT ;
    PORT
      LAYER M3 ;
      RECT 19.503 44.561 19.521 44.615 ;
    END
  END rw0_rd_out[182]
  PIN rw0_rd_out[183]
    DIRECTION OUTPUT ;
    USE SIGNAL ;
    SHAPE ABUTMENT ;
    PORT
      LAYER M3 ;
      RECT 19.791 44.561 19.809 44.615 ;
    END
  END rw0_rd_out[183]
  PIN rw0_rd_out[184]
    DIRECTION OUTPUT ;
    USE SIGNAL ;
    SHAPE ABUTMENT ;
    PORT
      LAYER M3 ;
      RECT 20.079 44.561 20.097 44.615 ;
    END
  END rw0_rd_out[184]
  PIN rw0_rd_out[185]
    DIRECTION OUTPUT ;
    USE SIGNAL ;
    SHAPE ABUTMENT ;
    PORT
      LAYER M3 ;
      RECT 20.367 44.561 20.385 44.615 ;
    END
  END rw0_rd_out[185]
  PIN rw0_rd_out[186]
    DIRECTION OUTPUT ;
    USE SIGNAL ;
    SHAPE ABUTMENT ;
    PORT
      LAYER M3 ;
      RECT 20.655 44.561 20.673 44.615 ;
    END
  END rw0_rd_out[186]
  PIN rw0_rd_out[187]
    DIRECTION OUTPUT ;
    USE SIGNAL ;
    SHAPE ABUTMENT ;
    PORT
      LAYER M3 ;
      RECT 20.943 44.561 20.961 44.615 ;
    END
  END rw0_rd_out[187]
  PIN rw0_rd_out[188]
    DIRECTION OUTPUT ;
    USE SIGNAL ;
    SHAPE ABUTMENT ;
    PORT
      LAYER M3 ;
      RECT 21.231 44.561 21.249 44.615 ;
    END
  END rw0_rd_out[188]
  PIN rw0_rd_out[189]
    DIRECTION OUTPUT ;
    USE SIGNAL ;
    SHAPE ABUTMENT ;
    PORT
      LAYER M3 ;
      RECT 21.519 44.561 21.537 44.615 ;
    END
  END rw0_rd_out[189]
  PIN rw0_rd_out[190]
    DIRECTION OUTPUT ;
    USE SIGNAL ;
    SHAPE ABUTMENT ;
    PORT
      LAYER M3 ;
      RECT 21.807 44.561 21.825 44.615 ;
    END
  END rw0_rd_out[190]
  PIN rw0_rd_out[191]
    DIRECTION OUTPUT ;
    USE SIGNAL ;
    SHAPE ABUTMENT ;
    PORT
      LAYER M3 ;
      RECT 22.095 44.561 22.113 44.615 ;
    END
  END rw0_rd_out[191]
  PIN rw0_rd_out[192]
    DIRECTION OUTPUT ;
    USE SIGNAL ;
    SHAPE ABUTMENT ;
    PORT
      LAYER M3 ;
      RECT 22.383 44.561 22.401 44.615 ;
    END
  END rw0_rd_out[192]
  PIN rw0_rd_out[193]
    DIRECTION OUTPUT ;
    USE SIGNAL ;
    SHAPE ABUTMENT ;
    PORT
      LAYER M3 ;
      RECT 22.671 44.561 22.689 44.615 ;
    END
  END rw0_rd_out[193]
  PIN rw0_rd_out[194]
    DIRECTION OUTPUT ;
    USE SIGNAL ;
    SHAPE ABUTMENT ;
    PORT
      LAYER M3 ;
      RECT 22.959 44.561 22.977 44.615 ;
    END
  END rw0_rd_out[194]
  PIN rw0_rd_out[195]
    DIRECTION OUTPUT ;
    USE SIGNAL ;
    SHAPE ABUTMENT ;
    PORT
      LAYER M3 ;
      RECT 23.247 44.561 23.265 44.615 ;
    END
  END rw0_rd_out[195]
  PIN rw0_rd_out[196]
    DIRECTION OUTPUT ;
    USE SIGNAL ;
    SHAPE ABUTMENT ;
    PORT
      LAYER M3 ;
      RECT 23.535 44.561 23.553 44.615 ;
    END
  END rw0_rd_out[196]
  PIN rw0_rd_out[197]
    DIRECTION OUTPUT ;
    USE SIGNAL ;
    SHAPE ABUTMENT ;
    PORT
      LAYER M3 ;
      RECT 23.823 44.561 23.841 44.615 ;
    END
  END rw0_rd_out[197]
  PIN rw0_rd_out[198]
    DIRECTION OUTPUT ;
    USE SIGNAL ;
    SHAPE ABUTMENT ;
    PORT
      LAYER M3 ;
      RECT 24.111 44.561 24.129 44.615 ;
    END
  END rw0_rd_out[198]
  PIN rw0_rd_out[199]
    DIRECTION OUTPUT ;
    USE SIGNAL ;
    SHAPE ABUTMENT ;
    PORT
      LAYER M3 ;
      RECT 24.399 44.561 24.417 44.615 ;
    END
  END rw0_rd_out[199]
  PIN rw0_rd_out[200]
    DIRECTION OUTPUT ;
    USE SIGNAL ;
    SHAPE ABUTMENT ;
    PORT
      LAYER M3 ;
      RECT 24.687 44.561 24.705 44.615 ;
    END
  END rw0_rd_out[200]
  PIN rw0_rd_out[201]
    DIRECTION OUTPUT ;
    USE SIGNAL ;
    SHAPE ABUTMENT ;
    PORT
      LAYER M3 ;
      RECT 24.975 44.561 24.993 44.615 ;
    END
  END rw0_rd_out[201]
  PIN rw0_rd_out[202]
    DIRECTION OUTPUT ;
    USE SIGNAL ;
    SHAPE ABUTMENT ;
    PORT
      LAYER M3 ;
      RECT 25.263 44.561 25.281 44.615 ;
    END
  END rw0_rd_out[202]
  PIN rw0_rd_out[203]
    DIRECTION OUTPUT ;
    USE SIGNAL ;
    SHAPE ABUTMENT ;
    PORT
      LAYER M3 ;
      RECT 25.551 44.561 25.569 44.615 ;
    END
  END rw0_rd_out[203]
  PIN rw0_rd_out[204]
    DIRECTION OUTPUT ;
    USE SIGNAL ;
    SHAPE ABUTMENT ;
    PORT
      LAYER M3 ;
      RECT 25.839 44.561 25.857 44.615 ;
    END
  END rw0_rd_out[204]
  PIN rw0_rd_out[205]
    DIRECTION OUTPUT ;
    USE SIGNAL ;
    SHAPE ABUTMENT ;
    PORT
      LAYER M3 ;
      RECT 26.127 44.561 26.145 44.615 ;
    END
  END rw0_rd_out[205]
  PIN rw0_rd_out[206]
    DIRECTION OUTPUT ;
    USE SIGNAL ;
    SHAPE ABUTMENT ;
    PORT
      LAYER M3 ;
      RECT 26.415 44.561 26.433 44.615 ;
    END
  END rw0_rd_out[206]
  PIN rw0_rd_out[207]
    DIRECTION OUTPUT ;
    USE SIGNAL ;
    SHAPE ABUTMENT ;
    PORT
      LAYER M3 ;
      RECT 26.703 44.561 26.721 44.615 ;
    END
  END rw0_rd_out[207]
  PIN rw0_rd_out[208]
    DIRECTION OUTPUT ;
    USE SIGNAL ;
    SHAPE ABUTMENT ;
    PORT
      LAYER M3 ;
      RECT 26.991 44.561 27.009 44.615 ;
    END
  END rw0_rd_out[208]
  PIN rw0_rd_out[209]
    DIRECTION OUTPUT ;
    USE SIGNAL ;
    SHAPE ABUTMENT ;
    PORT
      LAYER M3 ;
      RECT 27.279 44.561 27.297 44.615 ;
    END
  END rw0_rd_out[209]
  PIN rw0_rd_out[210]
    DIRECTION OUTPUT ;
    USE SIGNAL ;
    SHAPE ABUTMENT ;
    PORT
      LAYER M3 ;
      RECT 27.567 44.561 27.585 44.615 ;
    END
  END rw0_rd_out[210]
  PIN rw0_rd_out[211]
    DIRECTION OUTPUT ;
    USE SIGNAL ;
    SHAPE ABUTMENT ;
    PORT
      LAYER M3 ;
      RECT 27.855 44.561 27.873 44.615 ;
    END
  END rw0_rd_out[211]
  PIN rw0_rd_out[212]
    DIRECTION OUTPUT ;
    USE SIGNAL ;
    SHAPE ABUTMENT ;
    PORT
      LAYER M3 ;
      RECT 28.143 44.561 28.161 44.615 ;
    END
  END rw0_rd_out[212]
  PIN rw0_rd_out[213]
    DIRECTION OUTPUT ;
    USE SIGNAL ;
    SHAPE ABUTMENT ;
    PORT
      LAYER M3 ;
      RECT 28.431 44.561 28.449 44.615 ;
    END
  END rw0_rd_out[213]
  PIN rw0_rd_out[214]
    DIRECTION OUTPUT ;
    USE SIGNAL ;
    SHAPE ABUTMENT ;
    PORT
      LAYER M3 ;
      RECT 28.719 44.561 28.737 44.615 ;
    END
  END rw0_rd_out[214]
  PIN rw0_rd_out[215]
    DIRECTION OUTPUT ;
    USE SIGNAL ;
    SHAPE ABUTMENT ;
    PORT
      LAYER M3 ;
      RECT 29.007 44.561 29.025 44.615 ;
    END
  END rw0_rd_out[215]
  PIN rw0_rd_out[216]
    DIRECTION OUTPUT ;
    USE SIGNAL ;
    SHAPE ABUTMENT ;
    PORT
      LAYER M3 ;
      RECT 29.295 44.561 29.313 44.615 ;
    END
  END rw0_rd_out[216]
  PIN rw0_rd_out[217]
    DIRECTION OUTPUT ;
    USE SIGNAL ;
    SHAPE ABUTMENT ;
    PORT
      LAYER M3 ;
      RECT 29.583 44.561 29.601 44.615 ;
    END
  END rw0_rd_out[217]
  PIN rw0_rd_out[218]
    DIRECTION OUTPUT ;
    USE SIGNAL ;
    SHAPE ABUTMENT ;
    PORT
      LAYER M3 ;
      RECT 29.871 44.561 29.889 44.615 ;
    END
  END rw0_rd_out[218]
  PIN rw0_rd_out[219]
    DIRECTION OUTPUT ;
    USE SIGNAL ;
    SHAPE ABUTMENT ;
    PORT
      LAYER M3 ;
      RECT 30.159 44.561 30.177 44.615 ;
    END
  END rw0_rd_out[219]
  PIN rw0_rd_out[220]
    DIRECTION OUTPUT ;
    USE SIGNAL ;
    SHAPE ABUTMENT ;
    PORT
      LAYER M3 ;
      RECT 30.447 44.561 30.465 44.615 ;
    END
  END rw0_rd_out[220]
  PIN rw0_rd_out[221]
    DIRECTION OUTPUT ;
    USE SIGNAL ;
    SHAPE ABUTMENT ;
    PORT
      LAYER M3 ;
      RECT 30.735 44.561 30.753 44.615 ;
    END
  END rw0_rd_out[221]
  PIN rw0_rd_out[222]
    DIRECTION OUTPUT ;
    USE SIGNAL ;
    SHAPE ABUTMENT ;
    PORT
      LAYER M3 ;
      RECT 31.023 44.561 31.041 44.615 ;
    END
  END rw0_rd_out[222]
  PIN rw0_rd_out[223]
    DIRECTION OUTPUT ;
    USE SIGNAL ;
    SHAPE ABUTMENT ;
    PORT
      LAYER M3 ;
      RECT 31.311 44.561 31.329 44.615 ;
    END
  END rw0_rd_out[223]
  PIN rw0_rd_out[224]
    DIRECTION OUTPUT ;
    USE SIGNAL ;
    SHAPE ABUTMENT ;
    PORT
      LAYER M3 ;
      RECT 31.599 44.561 31.617 44.615 ;
    END
  END rw0_rd_out[224]
  PIN rw0_rd_out[225]
    DIRECTION OUTPUT ;
    USE SIGNAL ;
    SHAPE ABUTMENT ;
    PORT
      LAYER M3 ;
      RECT 31.887 44.561 31.905 44.615 ;
    END
  END rw0_rd_out[225]
  PIN rw0_rd_out[226]
    DIRECTION OUTPUT ;
    USE SIGNAL ;
    SHAPE ABUTMENT ;
    PORT
      LAYER M3 ;
      RECT 32.175 44.561 32.193 44.615 ;
    END
  END rw0_rd_out[226]
  PIN rw0_rd_out[227]
    DIRECTION OUTPUT ;
    USE SIGNAL ;
    SHAPE ABUTMENT ;
    PORT
      LAYER M3 ;
      RECT 32.463 44.561 32.481 44.615 ;
    END
  END rw0_rd_out[227]
  PIN rw0_rd_out[228]
    DIRECTION OUTPUT ;
    USE SIGNAL ;
    SHAPE ABUTMENT ;
    PORT
      LAYER M3 ;
      RECT 32.751 44.561 32.769 44.615 ;
    END
  END rw0_rd_out[228]
  PIN rw0_rd_out[229]
    DIRECTION OUTPUT ;
    USE SIGNAL ;
    SHAPE ABUTMENT ;
    PORT
      LAYER M3 ;
      RECT 33.039 44.561 33.057 44.615 ;
    END
  END rw0_rd_out[229]
  PIN r0_rd_out[0]
    DIRECTION OUTPUT ;
    USE SIGNAL ;
    SHAPE ABUTMENT ;
    PORT
      LAYER M3 ;
      RECT 49.887 0.000 49.905 0.054 ;
    END
  END r0_rd_out[0]
  PIN r0_rd_out[1]
    DIRECTION OUTPUT ;
    USE SIGNAL ;
    SHAPE ABUTMENT ;
    PORT
      LAYER M3 ;
      RECT 50.103 0.000 50.121 0.054 ;
    END
  END r0_rd_out[1]
  PIN r0_rd_out[2]
    DIRECTION OUTPUT ;
    USE SIGNAL ;
    SHAPE ABUTMENT ;
    PORT
      LAYER M3 ;
      RECT 50.319 0.000 50.337 0.054 ;
    END
  END r0_rd_out[2]
  PIN r0_rd_out[3]
    DIRECTION OUTPUT ;
    USE SIGNAL ;
    SHAPE ABUTMENT ;
    PORT
      LAYER M3 ;
      RECT 50.535 0.000 50.553 0.054 ;
    END
  END r0_rd_out[3]
  PIN r0_rd_out[4]
    DIRECTION OUTPUT ;
    USE SIGNAL ;
    SHAPE ABUTMENT ;
    PORT
      LAYER M3 ;
      RECT 50.751 0.000 50.769 0.054 ;
    END
  END r0_rd_out[4]
  PIN r0_rd_out[5]
    DIRECTION OUTPUT ;
    USE SIGNAL ;
    SHAPE ABUTMENT ;
    PORT
      LAYER M3 ;
      RECT 50.967 0.000 50.985 0.054 ;
    END
  END r0_rd_out[5]
  PIN r0_rd_out[6]
    DIRECTION OUTPUT ;
    USE SIGNAL ;
    SHAPE ABUTMENT ;
    PORT
      LAYER M3 ;
      RECT 51.183 0.000 51.201 0.054 ;
    END
  END r0_rd_out[6]
  PIN r0_rd_out[7]
    DIRECTION OUTPUT ;
    USE SIGNAL ;
    SHAPE ABUTMENT ;
    PORT
      LAYER M3 ;
      RECT 51.399 0.000 51.417 0.054 ;
    END
  END r0_rd_out[7]
  PIN r0_rd_out[8]
    DIRECTION OUTPUT ;
    USE SIGNAL ;
    SHAPE ABUTMENT ;
    PORT
      LAYER M3 ;
      RECT 51.615 0.000 51.633 0.054 ;
    END
  END r0_rd_out[8]
  PIN r0_rd_out[9]
    DIRECTION OUTPUT ;
    USE SIGNAL ;
    SHAPE ABUTMENT ;
    PORT
      LAYER M3 ;
      RECT 51.831 0.000 51.849 0.054 ;
    END
  END r0_rd_out[9]
  PIN r0_rd_out[10]
    DIRECTION OUTPUT ;
    USE SIGNAL ;
    SHAPE ABUTMENT ;
    PORT
      LAYER M3 ;
      RECT 52.047 0.000 52.065 0.054 ;
    END
  END r0_rd_out[10]
  PIN r0_rd_out[11]
    DIRECTION OUTPUT ;
    USE SIGNAL ;
    SHAPE ABUTMENT ;
    PORT
      LAYER M3 ;
      RECT 52.263 0.000 52.281 0.054 ;
    END
  END r0_rd_out[11]
  PIN r0_rd_out[12]
    DIRECTION OUTPUT ;
    USE SIGNAL ;
    SHAPE ABUTMENT ;
    PORT
      LAYER M3 ;
      RECT 52.479 0.000 52.497 0.054 ;
    END
  END r0_rd_out[12]
  PIN r0_rd_out[13]
    DIRECTION OUTPUT ;
    USE SIGNAL ;
    SHAPE ABUTMENT ;
    PORT
      LAYER M3 ;
      RECT 52.695 0.000 52.713 0.054 ;
    END
  END r0_rd_out[13]
  PIN r0_rd_out[14]
    DIRECTION OUTPUT ;
    USE SIGNAL ;
    SHAPE ABUTMENT ;
    PORT
      LAYER M3 ;
      RECT 52.911 0.000 52.929 0.054 ;
    END
  END r0_rd_out[14]
  PIN r0_rd_out[15]
    DIRECTION OUTPUT ;
    USE SIGNAL ;
    SHAPE ABUTMENT ;
    PORT
      LAYER M3 ;
      RECT 53.127 0.000 53.145 0.054 ;
    END
  END r0_rd_out[15]
  PIN r0_rd_out[16]
    DIRECTION OUTPUT ;
    USE SIGNAL ;
    SHAPE ABUTMENT ;
    PORT
      LAYER M3 ;
      RECT 53.343 0.000 53.361 0.054 ;
    END
  END r0_rd_out[16]
  PIN r0_rd_out[17]
    DIRECTION OUTPUT ;
    USE SIGNAL ;
    SHAPE ABUTMENT ;
    PORT
      LAYER M3 ;
      RECT 53.559 0.000 53.577 0.054 ;
    END
  END r0_rd_out[17]
  PIN r0_rd_out[18]
    DIRECTION OUTPUT ;
    USE SIGNAL ;
    SHAPE ABUTMENT ;
    PORT
      LAYER M3 ;
      RECT 53.775 0.000 53.793 0.054 ;
    END
  END r0_rd_out[18]
  PIN r0_rd_out[19]
    DIRECTION OUTPUT ;
    USE SIGNAL ;
    SHAPE ABUTMENT ;
    PORT
      LAYER M3 ;
      RECT 53.991 0.000 54.009 0.054 ;
    END
  END r0_rd_out[19]
  PIN r0_rd_out[20]
    DIRECTION OUTPUT ;
    USE SIGNAL ;
    SHAPE ABUTMENT ;
    PORT
      LAYER M3 ;
      RECT 54.207 0.000 54.225 0.054 ;
    END
  END r0_rd_out[20]
  PIN r0_rd_out[21]
    DIRECTION OUTPUT ;
    USE SIGNAL ;
    SHAPE ABUTMENT ;
    PORT
      LAYER M3 ;
      RECT 54.423 0.000 54.441 0.054 ;
    END
  END r0_rd_out[21]
  PIN r0_rd_out[22]
    DIRECTION OUTPUT ;
    USE SIGNAL ;
    SHAPE ABUTMENT ;
    PORT
      LAYER M3 ;
      RECT 54.639 0.000 54.657 0.054 ;
    END
  END r0_rd_out[22]
  PIN r0_rd_out[23]
    DIRECTION OUTPUT ;
    USE SIGNAL ;
    SHAPE ABUTMENT ;
    PORT
      LAYER M3 ;
      RECT 54.855 0.000 54.873 0.054 ;
    END
  END r0_rd_out[23]
  PIN r0_rd_out[24]
    DIRECTION OUTPUT ;
    USE SIGNAL ;
    SHAPE ABUTMENT ;
    PORT
      LAYER M3 ;
      RECT 55.071 0.000 55.089 0.054 ;
    END
  END r0_rd_out[24]
  PIN r0_rd_out[25]
    DIRECTION OUTPUT ;
    USE SIGNAL ;
    SHAPE ABUTMENT ;
    PORT
      LAYER M3 ;
      RECT 55.287 0.000 55.305 0.054 ;
    END
  END r0_rd_out[25]
  PIN r0_rd_out[26]
    DIRECTION OUTPUT ;
    USE SIGNAL ;
    SHAPE ABUTMENT ;
    PORT
      LAYER M3 ;
      RECT 55.503 0.000 55.521 0.054 ;
    END
  END r0_rd_out[26]
  PIN r0_rd_out[27]
    DIRECTION OUTPUT ;
    USE SIGNAL ;
    SHAPE ABUTMENT ;
    PORT
      LAYER M3 ;
      RECT 55.719 0.000 55.737 0.054 ;
    END
  END r0_rd_out[27]
  PIN r0_rd_out[28]
    DIRECTION OUTPUT ;
    USE SIGNAL ;
    SHAPE ABUTMENT ;
    PORT
      LAYER M3 ;
      RECT 55.935 0.000 55.953 0.054 ;
    END
  END r0_rd_out[28]
  PIN r0_rd_out[29]
    DIRECTION OUTPUT ;
    USE SIGNAL ;
    SHAPE ABUTMENT ;
    PORT
      LAYER M3 ;
      RECT 56.151 0.000 56.169 0.054 ;
    END
  END r0_rd_out[29]
  PIN r0_rd_out[30]
    DIRECTION OUTPUT ;
    USE SIGNAL ;
    SHAPE ABUTMENT ;
    PORT
      LAYER M3 ;
      RECT 56.367 0.000 56.385 0.054 ;
    END
  END r0_rd_out[30]
  PIN r0_rd_out[31]
    DIRECTION OUTPUT ;
    USE SIGNAL ;
    SHAPE ABUTMENT ;
    PORT
      LAYER M3 ;
      RECT 56.583 0.000 56.601 0.054 ;
    END
  END r0_rd_out[31]
  PIN r0_rd_out[32]
    DIRECTION OUTPUT ;
    USE SIGNAL ;
    SHAPE ABUTMENT ;
    PORT
      LAYER M3 ;
      RECT 56.799 0.000 56.817 0.054 ;
    END
  END r0_rd_out[32]
  PIN r0_rd_out[33]
    DIRECTION OUTPUT ;
    USE SIGNAL ;
    SHAPE ABUTMENT ;
    PORT
      LAYER M3 ;
      RECT 57.015 0.000 57.033 0.054 ;
    END
  END r0_rd_out[33]
  PIN r0_rd_out[34]
    DIRECTION OUTPUT ;
    USE SIGNAL ;
    SHAPE ABUTMENT ;
    PORT
      LAYER M3 ;
      RECT 57.231 0.000 57.249 0.054 ;
    END
  END r0_rd_out[34]
  PIN r0_rd_out[35]
    DIRECTION OUTPUT ;
    USE SIGNAL ;
    SHAPE ABUTMENT ;
    PORT
      LAYER M3 ;
      RECT 57.447 0.000 57.465 0.054 ;
    END
  END r0_rd_out[35]
  PIN r0_rd_out[36]
    DIRECTION OUTPUT ;
    USE SIGNAL ;
    SHAPE ABUTMENT ;
    PORT
      LAYER M3 ;
      RECT 57.663 0.000 57.681 0.054 ;
    END
  END r0_rd_out[36]
  PIN r0_rd_out[37]
    DIRECTION OUTPUT ;
    USE SIGNAL ;
    SHAPE ABUTMENT ;
    PORT
      LAYER M3 ;
      RECT 57.879 0.000 57.897 0.054 ;
    END
  END r0_rd_out[37]
  PIN r0_rd_out[38]
    DIRECTION OUTPUT ;
    USE SIGNAL ;
    SHAPE ABUTMENT ;
    PORT
      LAYER M3 ;
      RECT 58.095 0.000 58.113 0.054 ;
    END
  END r0_rd_out[38]
  PIN r0_rd_out[39]
    DIRECTION OUTPUT ;
    USE SIGNAL ;
    SHAPE ABUTMENT ;
    PORT
      LAYER M3 ;
      RECT 58.311 0.000 58.329 0.054 ;
    END
  END r0_rd_out[39]
  PIN r0_rd_out[40]
    DIRECTION OUTPUT ;
    USE SIGNAL ;
    SHAPE ABUTMENT ;
    PORT
      LAYER M3 ;
      RECT 58.527 0.000 58.545 0.054 ;
    END
  END r0_rd_out[40]
  PIN r0_rd_out[41]
    DIRECTION OUTPUT ;
    USE SIGNAL ;
    SHAPE ABUTMENT ;
    PORT
      LAYER M3 ;
      RECT 58.743 0.000 58.761 0.054 ;
    END
  END r0_rd_out[41]
  PIN r0_rd_out[42]
    DIRECTION OUTPUT ;
    USE SIGNAL ;
    SHAPE ABUTMENT ;
    PORT
      LAYER M3 ;
      RECT 58.959 0.000 58.977 0.054 ;
    END
  END r0_rd_out[42]
  PIN r0_rd_out[43]
    DIRECTION OUTPUT ;
    USE SIGNAL ;
    SHAPE ABUTMENT ;
    PORT
      LAYER M3 ;
      RECT 59.175 0.000 59.193 0.054 ;
    END
  END r0_rd_out[43]
  PIN r0_rd_out[44]
    DIRECTION OUTPUT ;
    USE SIGNAL ;
    SHAPE ABUTMENT ;
    PORT
      LAYER M3 ;
      RECT 59.391 0.000 59.409 0.054 ;
    END
  END r0_rd_out[44]
  PIN r0_rd_out[45]
    DIRECTION OUTPUT ;
    USE SIGNAL ;
    SHAPE ABUTMENT ;
    PORT
      LAYER M3 ;
      RECT 59.607 0.000 59.625 0.054 ;
    END
  END r0_rd_out[45]
  PIN r0_rd_out[46]
    DIRECTION OUTPUT ;
    USE SIGNAL ;
    SHAPE ABUTMENT ;
    PORT
      LAYER M3 ;
      RECT 59.823 0.000 59.841 0.054 ;
    END
  END r0_rd_out[46]
  PIN r0_rd_out[47]
    DIRECTION OUTPUT ;
    USE SIGNAL ;
    SHAPE ABUTMENT ;
    PORT
      LAYER M3 ;
      RECT 60.039 0.000 60.057 0.054 ;
    END
  END r0_rd_out[47]
  PIN r0_rd_out[48]
    DIRECTION OUTPUT ;
    USE SIGNAL ;
    SHAPE ABUTMENT ;
    PORT
      LAYER M3 ;
      RECT 60.255 0.000 60.273 0.054 ;
    END
  END r0_rd_out[48]
  PIN r0_rd_out[49]
    DIRECTION OUTPUT ;
    USE SIGNAL ;
    SHAPE ABUTMENT ;
    PORT
      LAYER M3 ;
      RECT 60.471 0.000 60.489 0.054 ;
    END
  END r0_rd_out[49]
  PIN r0_rd_out[50]
    DIRECTION OUTPUT ;
    USE SIGNAL ;
    SHAPE ABUTMENT ;
    PORT
      LAYER M3 ;
      RECT 60.687 0.000 60.705 0.054 ;
    END
  END r0_rd_out[50]
  PIN r0_rd_out[51]
    DIRECTION OUTPUT ;
    USE SIGNAL ;
    SHAPE ABUTMENT ;
    PORT
      LAYER M3 ;
      RECT 60.903 0.000 60.921 0.054 ;
    END
  END r0_rd_out[51]
  PIN r0_rd_out[52]
    DIRECTION OUTPUT ;
    USE SIGNAL ;
    SHAPE ABUTMENT ;
    PORT
      LAYER M3 ;
      RECT 61.119 0.000 61.137 0.054 ;
    END
  END r0_rd_out[52]
  PIN r0_rd_out[53]
    DIRECTION OUTPUT ;
    USE SIGNAL ;
    SHAPE ABUTMENT ;
    PORT
      LAYER M3 ;
      RECT 61.335 0.000 61.353 0.054 ;
    END
  END r0_rd_out[53]
  PIN r0_rd_out[54]
    DIRECTION OUTPUT ;
    USE SIGNAL ;
    SHAPE ABUTMENT ;
    PORT
      LAYER M3 ;
      RECT 61.551 0.000 61.569 0.054 ;
    END
  END r0_rd_out[54]
  PIN r0_rd_out[55]
    DIRECTION OUTPUT ;
    USE SIGNAL ;
    SHAPE ABUTMENT ;
    PORT
      LAYER M3 ;
      RECT 61.767 0.000 61.785 0.054 ;
    END
  END r0_rd_out[55]
  PIN r0_rd_out[56]
    DIRECTION OUTPUT ;
    USE SIGNAL ;
    SHAPE ABUTMENT ;
    PORT
      LAYER M3 ;
      RECT 61.983 0.000 62.001 0.054 ;
    END
  END r0_rd_out[56]
  PIN r0_rd_out[57]
    DIRECTION OUTPUT ;
    USE SIGNAL ;
    SHAPE ABUTMENT ;
    PORT
      LAYER M3 ;
      RECT 62.199 0.000 62.217 0.054 ;
    END
  END r0_rd_out[57]
  PIN r0_rd_out[58]
    DIRECTION OUTPUT ;
    USE SIGNAL ;
    SHAPE ABUTMENT ;
    PORT
      LAYER M3 ;
      RECT 62.415 0.000 62.433 0.054 ;
    END
  END r0_rd_out[58]
  PIN r0_rd_out[59]
    DIRECTION OUTPUT ;
    USE SIGNAL ;
    SHAPE ABUTMENT ;
    PORT
      LAYER M3 ;
      RECT 62.631 0.000 62.649 0.054 ;
    END
  END r0_rd_out[59]
  PIN r0_rd_out[60]
    DIRECTION OUTPUT ;
    USE SIGNAL ;
    SHAPE ABUTMENT ;
    PORT
      LAYER M3 ;
      RECT 62.847 0.000 62.865 0.054 ;
    END
  END r0_rd_out[60]
  PIN r0_rd_out[61]
    DIRECTION OUTPUT ;
    USE SIGNAL ;
    SHAPE ABUTMENT ;
    PORT
      LAYER M3 ;
      RECT 63.063 0.000 63.081 0.054 ;
    END
  END r0_rd_out[61]
  PIN r0_rd_out[62]
    DIRECTION OUTPUT ;
    USE SIGNAL ;
    SHAPE ABUTMENT ;
    PORT
      LAYER M3 ;
      RECT 63.279 0.000 63.297 0.054 ;
    END
  END r0_rd_out[62]
  PIN r0_rd_out[63]
    DIRECTION OUTPUT ;
    USE SIGNAL ;
    SHAPE ABUTMENT ;
    PORT
      LAYER M3 ;
      RECT 63.495 0.000 63.513 0.054 ;
    END
  END r0_rd_out[63]
  PIN r0_rd_out[64]
    DIRECTION OUTPUT ;
    USE SIGNAL ;
    SHAPE ABUTMENT ;
    PORT
      LAYER M3 ;
      RECT 63.711 0.000 63.729 0.054 ;
    END
  END r0_rd_out[64]
  PIN r0_rd_out[65]
    DIRECTION OUTPUT ;
    USE SIGNAL ;
    SHAPE ABUTMENT ;
    PORT
      LAYER M3 ;
      RECT 63.927 0.000 63.945 0.054 ;
    END
  END r0_rd_out[65]
  PIN r0_rd_out[66]
    DIRECTION OUTPUT ;
    USE SIGNAL ;
    SHAPE ABUTMENT ;
    PORT
      LAYER M3 ;
      RECT 64.143 0.000 64.161 0.054 ;
    END
  END r0_rd_out[66]
  PIN r0_rd_out[67]
    DIRECTION OUTPUT ;
    USE SIGNAL ;
    SHAPE ABUTMENT ;
    PORT
      LAYER M3 ;
      RECT 64.359 0.000 64.377 0.054 ;
    END
  END r0_rd_out[67]
  PIN r0_rd_out[68]
    DIRECTION OUTPUT ;
    USE SIGNAL ;
    SHAPE ABUTMENT ;
    PORT
      LAYER M3 ;
      RECT 64.575 0.000 64.593 0.054 ;
    END
  END r0_rd_out[68]
  PIN r0_rd_out[69]
    DIRECTION OUTPUT ;
    USE SIGNAL ;
    SHAPE ABUTMENT ;
    PORT
      LAYER M3 ;
      RECT 64.791 0.000 64.809 0.054 ;
    END
  END r0_rd_out[69]
  PIN r0_rd_out[70]
    DIRECTION OUTPUT ;
    USE SIGNAL ;
    SHAPE ABUTMENT ;
    PORT
      LAYER M3 ;
      RECT 65.007 0.000 65.025 0.054 ;
    END
  END r0_rd_out[70]
  PIN r0_rd_out[71]
    DIRECTION OUTPUT ;
    USE SIGNAL ;
    SHAPE ABUTMENT ;
    PORT
      LAYER M3 ;
      RECT 65.223 0.000 65.241 0.054 ;
    END
  END r0_rd_out[71]
  PIN r0_rd_out[72]
    DIRECTION OUTPUT ;
    USE SIGNAL ;
    SHAPE ABUTMENT ;
    PORT
      LAYER M3 ;
      RECT 65.439 0.000 65.457 0.054 ;
    END
  END r0_rd_out[72]
  PIN r0_rd_out[73]
    DIRECTION OUTPUT ;
    USE SIGNAL ;
    SHAPE ABUTMENT ;
    PORT
      LAYER M3 ;
      RECT 65.655 0.000 65.673 0.054 ;
    END
  END r0_rd_out[73]
  PIN r0_rd_out[74]
    DIRECTION OUTPUT ;
    USE SIGNAL ;
    SHAPE ABUTMENT ;
    PORT
      LAYER M3 ;
      RECT 65.871 0.000 65.889 0.054 ;
    END
  END r0_rd_out[74]
  PIN r0_rd_out[75]
    DIRECTION OUTPUT ;
    USE SIGNAL ;
    SHAPE ABUTMENT ;
    PORT
      LAYER M3 ;
      RECT 66.087 0.000 66.105 0.054 ;
    END
  END r0_rd_out[75]
  PIN r0_rd_out[76]
    DIRECTION OUTPUT ;
    USE SIGNAL ;
    SHAPE ABUTMENT ;
    PORT
      LAYER M3 ;
      RECT 66.303 0.000 66.321 0.054 ;
    END
  END r0_rd_out[76]
  PIN r0_rd_out[77]
    DIRECTION OUTPUT ;
    USE SIGNAL ;
    SHAPE ABUTMENT ;
    PORT
      LAYER M3 ;
      RECT 66.519 0.000 66.537 0.054 ;
    END
  END r0_rd_out[77]
  PIN r0_rd_out[78]
    DIRECTION OUTPUT ;
    USE SIGNAL ;
    SHAPE ABUTMENT ;
    PORT
      LAYER M3 ;
      RECT 66.735 0.000 66.753 0.054 ;
    END
  END r0_rd_out[78]
  PIN r0_rd_out[79]
    DIRECTION OUTPUT ;
    USE SIGNAL ;
    SHAPE ABUTMENT ;
    PORT
      LAYER M3 ;
      RECT 66.951 0.000 66.969 0.054 ;
    END
  END r0_rd_out[79]
  PIN r0_rd_out[80]
    DIRECTION OUTPUT ;
    USE SIGNAL ;
    SHAPE ABUTMENT ;
    PORT
      LAYER M3 ;
      RECT 67.167 0.000 67.185 0.054 ;
    END
  END r0_rd_out[80]
  PIN r0_rd_out[81]
    DIRECTION OUTPUT ;
    USE SIGNAL ;
    SHAPE ABUTMENT ;
    PORT
      LAYER M3 ;
      RECT 67.383 0.000 67.401 0.054 ;
    END
  END r0_rd_out[81]
  PIN r0_rd_out[82]
    DIRECTION OUTPUT ;
    USE SIGNAL ;
    SHAPE ABUTMENT ;
    PORT
      LAYER M3 ;
      RECT 67.599 0.000 67.617 0.054 ;
    END
  END r0_rd_out[82]
  PIN r0_rd_out[83]
    DIRECTION OUTPUT ;
    USE SIGNAL ;
    SHAPE ABUTMENT ;
    PORT
      LAYER M3 ;
      RECT 67.815 0.000 67.833 0.054 ;
    END
  END r0_rd_out[83]
  PIN r0_rd_out[84]
    DIRECTION OUTPUT ;
    USE SIGNAL ;
    SHAPE ABUTMENT ;
    PORT
      LAYER M3 ;
      RECT 68.031 0.000 68.049 0.054 ;
    END
  END r0_rd_out[84]
  PIN r0_rd_out[85]
    DIRECTION OUTPUT ;
    USE SIGNAL ;
    SHAPE ABUTMENT ;
    PORT
      LAYER M3 ;
      RECT 68.247 0.000 68.265 0.054 ;
    END
  END r0_rd_out[85]
  PIN r0_rd_out[86]
    DIRECTION OUTPUT ;
    USE SIGNAL ;
    SHAPE ABUTMENT ;
    PORT
      LAYER M3 ;
      RECT 68.463 0.000 68.481 0.054 ;
    END
  END r0_rd_out[86]
  PIN r0_rd_out[87]
    DIRECTION OUTPUT ;
    USE SIGNAL ;
    SHAPE ABUTMENT ;
    PORT
      LAYER M3 ;
      RECT 68.679 0.000 68.697 0.054 ;
    END
  END r0_rd_out[87]
  PIN r0_rd_out[88]
    DIRECTION OUTPUT ;
    USE SIGNAL ;
    SHAPE ABUTMENT ;
    PORT
      LAYER M3 ;
      RECT 68.895 0.000 68.913 0.054 ;
    END
  END r0_rd_out[88]
  PIN r0_rd_out[89]
    DIRECTION OUTPUT ;
    USE SIGNAL ;
    SHAPE ABUTMENT ;
    PORT
      LAYER M3 ;
      RECT 69.111 0.000 69.129 0.054 ;
    END
  END r0_rd_out[89]
  PIN r0_rd_out[90]
    DIRECTION OUTPUT ;
    USE SIGNAL ;
    SHAPE ABUTMENT ;
    PORT
      LAYER M3 ;
      RECT 69.327 0.000 69.345 0.054 ;
    END
  END r0_rd_out[90]
  PIN r0_rd_out[91]
    DIRECTION OUTPUT ;
    USE SIGNAL ;
    SHAPE ABUTMENT ;
    PORT
      LAYER M3 ;
      RECT 69.543 0.000 69.561 0.054 ;
    END
  END r0_rd_out[91]
  PIN r0_rd_out[92]
    DIRECTION OUTPUT ;
    USE SIGNAL ;
    SHAPE ABUTMENT ;
    PORT
      LAYER M3 ;
      RECT 69.759 0.000 69.777 0.054 ;
    END
  END r0_rd_out[92]
  PIN r0_rd_out[93]
    DIRECTION OUTPUT ;
    USE SIGNAL ;
    SHAPE ABUTMENT ;
    PORT
      LAYER M3 ;
      RECT 69.975 0.000 69.993 0.054 ;
    END
  END r0_rd_out[93]
  PIN r0_rd_out[94]
    DIRECTION OUTPUT ;
    USE SIGNAL ;
    SHAPE ABUTMENT ;
    PORT
      LAYER M3 ;
      RECT 70.191 0.000 70.209 0.054 ;
    END
  END r0_rd_out[94]
  PIN r0_rd_out[95]
    DIRECTION OUTPUT ;
    USE SIGNAL ;
    SHAPE ABUTMENT ;
    PORT
      LAYER M3 ;
      RECT 70.407 0.000 70.425 0.054 ;
    END
  END r0_rd_out[95]
  PIN r0_rd_out[96]
    DIRECTION OUTPUT ;
    USE SIGNAL ;
    SHAPE ABUTMENT ;
    PORT
      LAYER M3 ;
      RECT 70.623 0.000 70.641 0.054 ;
    END
  END r0_rd_out[96]
  PIN r0_rd_out[97]
    DIRECTION OUTPUT ;
    USE SIGNAL ;
    SHAPE ABUTMENT ;
    PORT
      LAYER M3 ;
      RECT 70.839 0.000 70.857 0.054 ;
    END
  END r0_rd_out[97]
  PIN r0_rd_out[98]
    DIRECTION OUTPUT ;
    USE SIGNAL ;
    SHAPE ABUTMENT ;
    PORT
      LAYER M3 ;
      RECT 71.055 0.000 71.073 0.054 ;
    END
  END r0_rd_out[98]
  PIN r0_rd_out[99]
    DIRECTION OUTPUT ;
    USE SIGNAL ;
    SHAPE ABUTMENT ;
    PORT
      LAYER M3 ;
      RECT 71.271 0.000 71.289 0.054 ;
    END
  END r0_rd_out[99]
  PIN r0_rd_out[100]
    DIRECTION OUTPUT ;
    USE SIGNAL ;
    SHAPE ABUTMENT ;
    PORT
      LAYER M3 ;
      RECT 71.487 0.000 71.505 0.054 ;
    END
  END r0_rd_out[100]
  PIN r0_rd_out[101]
    DIRECTION OUTPUT ;
    USE SIGNAL ;
    SHAPE ABUTMENT ;
    PORT
      LAYER M3 ;
      RECT 71.703 0.000 71.721 0.054 ;
    END
  END r0_rd_out[101]
  PIN r0_rd_out[102]
    DIRECTION OUTPUT ;
    USE SIGNAL ;
    SHAPE ABUTMENT ;
    PORT
      LAYER M3 ;
      RECT 71.919 0.000 71.937 0.054 ;
    END
  END r0_rd_out[102]
  PIN r0_rd_out[103]
    DIRECTION OUTPUT ;
    USE SIGNAL ;
    SHAPE ABUTMENT ;
    PORT
      LAYER M3 ;
      RECT 72.135 0.000 72.153 0.054 ;
    END
  END r0_rd_out[103]
  PIN r0_rd_out[104]
    DIRECTION OUTPUT ;
    USE SIGNAL ;
    SHAPE ABUTMENT ;
    PORT
      LAYER M3 ;
      RECT 72.351 0.000 72.369 0.054 ;
    END
  END r0_rd_out[104]
  PIN r0_rd_out[105]
    DIRECTION OUTPUT ;
    USE SIGNAL ;
    SHAPE ABUTMENT ;
    PORT
      LAYER M3 ;
      RECT 72.567 0.000 72.585 0.054 ;
    END
  END r0_rd_out[105]
  PIN r0_rd_out[106]
    DIRECTION OUTPUT ;
    USE SIGNAL ;
    SHAPE ABUTMENT ;
    PORT
      LAYER M3 ;
      RECT 72.783 0.000 72.801 0.054 ;
    END
  END r0_rd_out[106]
  PIN r0_rd_out[107]
    DIRECTION OUTPUT ;
    USE SIGNAL ;
    SHAPE ABUTMENT ;
    PORT
      LAYER M3 ;
      RECT 72.999 0.000 73.017 0.054 ;
    END
  END r0_rd_out[107]
  PIN r0_rd_out[108]
    DIRECTION OUTPUT ;
    USE SIGNAL ;
    SHAPE ABUTMENT ;
    PORT
      LAYER M3 ;
      RECT 73.215 0.000 73.233 0.054 ;
    END
  END r0_rd_out[108]
  PIN r0_rd_out[109]
    DIRECTION OUTPUT ;
    USE SIGNAL ;
    SHAPE ABUTMENT ;
    PORT
      LAYER M3 ;
      RECT 73.431 0.000 73.449 0.054 ;
    END
  END r0_rd_out[109]
  PIN r0_rd_out[110]
    DIRECTION OUTPUT ;
    USE SIGNAL ;
    SHAPE ABUTMENT ;
    PORT
      LAYER M3 ;
      RECT 73.647 0.000 73.665 0.054 ;
    END
  END r0_rd_out[110]
  PIN r0_rd_out[111]
    DIRECTION OUTPUT ;
    USE SIGNAL ;
    SHAPE ABUTMENT ;
    PORT
      LAYER M3 ;
      RECT 73.863 0.000 73.881 0.054 ;
    END
  END r0_rd_out[111]
  PIN r0_rd_out[112]
    DIRECTION OUTPUT ;
    USE SIGNAL ;
    SHAPE ABUTMENT ;
    PORT
      LAYER M3 ;
      RECT 74.079 0.000 74.097 0.054 ;
    END
  END r0_rd_out[112]
  PIN r0_rd_out[113]
    DIRECTION OUTPUT ;
    USE SIGNAL ;
    SHAPE ABUTMENT ;
    PORT
      LAYER M3 ;
      RECT 74.295 0.000 74.313 0.054 ;
    END
  END r0_rd_out[113]
  PIN r0_rd_out[114]
    DIRECTION OUTPUT ;
    USE SIGNAL ;
    SHAPE ABUTMENT ;
    PORT
      LAYER M3 ;
      RECT 74.511 0.000 74.529 0.054 ;
    END
  END r0_rd_out[114]
  PIN r0_rd_out[115]
    DIRECTION OUTPUT ;
    USE SIGNAL ;
    SHAPE ABUTMENT ;
    PORT
      LAYER M3 ;
      RECT 33.327 44.561 33.345 44.615 ;
    END
  END r0_rd_out[115]
  PIN r0_rd_out[116]
    DIRECTION OUTPUT ;
    USE SIGNAL ;
    SHAPE ABUTMENT ;
    PORT
      LAYER M3 ;
      RECT 33.615 44.561 33.633 44.615 ;
    END
  END r0_rd_out[116]
  PIN r0_rd_out[117]
    DIRECTION OUTPUT ;
    USE SIGNAL ;
    SHAPE ABUTMENT ;
    PORT
      LAYER M3 ;
      RECT 33.903 44.561 33.921 44.615 ;
    END
  END r0_rd_out[117]
  PIN r0_rd_out[118]
    DIRECTION OUTPUT ;
    USE SIGNAL ;
    SHAPE ABUTMENT ;
    PORT
      LAYER M3 ;
      RECT 34.191 44.561 34.209 44.615 ;
    END
  END r0_rd_out[118]
  PIN r0_rd_out[119]
    DIRECTION OUTPUT ;
    USE SIGNAL ;
    SHAPE ABUTMENT ;
    PORT
      LAYER M3 ;
      RECT 34.479 44.561 34.497 44.615 ;
    END
  END r0_rd_out[119]
  PIN r0_rd_out[120]
    DIRECTION OUTPUT ;
    USE SIGNAL ;
    SHAPE ABUTMENT ;
    PORT
      LAYER M3 ;
      RECT 34.767 44.561 34.785 44.615 ;
    END
  END r0_rd_out[120]
  PIN r0_rd_out[121]
    DIRECTION OUTPUT ;
    USE SIGNAL ;
    SHAPE ABUTMENT ;
    PORT
      LAYER M3 ;
      RECT 35.055 44.561 35.073 44.615 ;
    END
  END r0_rd_out[121]
  PIN r0_rd_out[122]
    DIRECTION OUTPUT ;
    USE SIGNAL ;
    SHAPE ABUTMENT ;
    PORT
      LAYER M3 ;
      RECT 35.343 44.561 35.361 44.615 ;
    END
  END r0_rd_out[122]
  PIN r0_rd_out[123]
    DIRECTION OUTPUT ;
    USE SIGNAL ;
    SHAPE ABUTMENT ;
    PORT
      LAYER M3 ;
      RECT 35.631 44.561 35.649 44.615 ;
    END
  END r0_rd_out[123]
  PIN r0_rd_out[124]
    DIRECTION OUTPUT ;
    USE SIGNAL ;
    SHAPE ABUTMENT ;
    PORT
      LAYER M3 ;
      RECT 35.919 44.561 35.937 44.615 ;
    END
  END r0_rd_out[124]
  PIN r0_rd_out[125]
    DIRECTION OUTPUT ;
    USE SIGNAL ;
    SHAPE ABUTMENT ;
    PORT
      LAYER M3 ;
      RECT 36.207 44.561 36.225 44.615 ;
    END
  END r0_rd_out[125]
  PIN r0_rd_out[126]
    DIRECTION OUTPUT ;
    USE SIGNAL ;
    SHAPE ABUTMENT ;
    PORT
      LAYER M3 ;
      RECT 36.495 44.561 36.513 44.615 ;
    END
  END r0_rd_out[126]
  PIN r0_rd_out[127]
    DIRECTION OUTPUT ;
    USE SIGNAL ;
    SHAPE ABUTMENT ;
    PORT
      LAYER M3 ;
      RECT 36.783 44.561 36.801 44.615 ;
    END
  END r0_rd_out[127]
  PIN r0_rd_out[128]
    DIRECTION OUTPUT ;
    USE SIGNAL ;
    SHAPE ABUTMENT ;
    PORT
      LAYER M3 ;
      RECT 37.071 44.561 37.089 44.615 ;
    END
  END r0_rd_out[128]
  PIN r0_rd_out[129]
    DIRECTION OUTPUT ;
    USE SIGNAL ;
    SHAPE ABUTMENT ;
    PORT
      LAYER M3 ;
      RECT 37.359 44.561 37.377 44.615 ;
    END
  END r0_rd_out[129]
  PIN r0_rd_out[130]
    DIRECTION OUTPUT ;
    USE SIGNAL ;
    SHAPE ABUTMENT ;
    PORT
      LAYER M3 ;
      RECT 37.647 44.561 37.665 44.615 ;
    END
  END r0_rd_out[130]
  PIN r0_rd_out[131]
    DIRECTION OUTPUT ;
    USE SIGNAL ;
    SHAPE ABUTMENT ;
    PORT
      LAYER M3 ;
      RECT 37.935 44.561 37.953 44.615 ;
    END
  END r0_rd_out[131]
  PIN r0_rd_out[132]
    DIRECTION OUTPUT ;
    USE SIGNAL ;
    SHAPE ABUTMENT ;
    PORT
      LAYER M3 ;
      RECT 38.223 44.561 38.241 44.615 ;
    END
  END r0_rd_out[132]
  PIN r0_rd_out[133]
    DIRECTION OUTPUT ;
    USE SIGNAL ;
    SHAPE ABUTMENT ;
    PORT
      LAYER M3 ;
      RECT 38.511 44.561 38.529 44.615 ;
    END
  END r0_rd_out[133]
  PIN r0_rd_out[134]
    DIRECTION OUTPUT ;
    USE SIGNAL ;
    SHAPE ABUTMENT ;
    PORT
      LAYER M3 ;
      RECT 38.799 44.561 38.817 44.615 ;
    END
  END r0_rd_out[134]
  PIN r0_rd_out[135]
    DIRECTION OUTPUT ;
    USE SIGNAL ;
    SHAPE ABUTMENT ;
    PORT
      LAYER M3 ;
      RECT 39.087 44.561 39.105 44.615 ;
    END
  END r0_rd_out[135]
  PIN r0_rd_out[136]
    DIRECTION OUTPUT ;
    USE SIGNAL ;
    SHAPE ABUTMENT ;
    PORT
      LAYER M3 ;
      RECT 39.375 44.561 39.393 44.615 ;
    END
  END r0_rd_out[136]
  PIN r0_rd_out[137]
    DIRECTION OUTPUT ;
    USE SIGNAL ;
    SHAPE ABUTMENT ;
    PORT
      LAYER M3 ;
      RECT 39.663 44.561 39.681 44.615 ;
    END
  END r0_rd_out[137]
  PIN r0_rd_out[138]
    DIRECTION OUTPUT ;
    USE SIGNAL ;
    SHAPE ABUTMENT ;
    PORT
      LAYER M3 ;
      RECT 39.951 44.561 39.969 44.615 ;
    END
  END r0_rd_out[138]
  PIN r0_rd_out[139]
    DIRECTION OUTPUT ;
    USE SIGNAL ;
    SHAPE ABUTMENT ;
    PORT
      LAYER M3 ;
      RECT 40.239 44.561 40.257 44.615 ;
    END
  END r0_rd_out[139]
  PIN r0_rd_out[140]
    DIRECTION OUTPUT ;
    USE SIGNAL ;
    SHAPE ABUTMENT ;
    PORT
      LAYER M3 ;
      RECT 40.527 44.561 40.545 44.615 ;
    END
  END r0_rd_out[140]
  PIN r0_rd_out[141]
    DIRECTION OUTPUT ;
    USE SIGNAL ;
    SHAPE ABUTMENT ;
    PORT
      LAYER M3 ;
      RECT 40.815 44.561 40.833 44.615 ;
    END
  END r0_rd_out[141]
  PIN r0_rd_out[142]
    DIRECTION OUTPUT ;
    USE SIGNAL ;
    SHAPE ABUTMENT ;
    PORT
      LAYER M3 ;
      RECT 41.103 44.561 41.121 44.615 ;
    END
  END r0_rd_out[142]
  PIN r0_rd_out[143]
    DIRECTION OUTPUT ;
    USE SIGNAL ;
    SHAPE ABUTMENT ;
    PORT
      LAYER M3 ;
      RECT 41.391 44.561 41.409 44.615 ;
    END
  END r0_rd_out[143]
  PIN r0_rd_out[144]
    DIRECTION OUTPUT ;
    USE SIGNAL ;
    SHAPE ABUTMENT ;
    PORT
      LAYER M3 ;
      RECT 41.679 44.561 41.697 44.615 ;
    END
  END r0_rd_out[144]
  PIN r0_rd_out[145]
    DIRECTION OUTPUT ;
    USE SIGNAL ;
    SHAPE ABUTMENT ;
    PORT
      LAYER M3 ;
      RECT 41.967 44.561 41.985 44.615 ;
    END
  END r0_rd_out[145]
  PIN r0_rd_out[146]
    DIRECTION OUTPUT ;
    USE SIGNAL ;
    SHAPE ABUTMENT ;
    PORT
      LAYER M3 ;
      RECT 42.255 44.561 42.273 44.615 ;
    END
  END r0_rd_out[146]
  PIN r0_rd_out[147]
    DIRECTION OUTPUT ;
    USE SIGNAL ;
    SHAPE ABUTMENT ;
    PORT
      LAYER M3 ;
      RECT 42.543 44.561 42.561 44.615 ;
    END
  END r0_rd_out[147]
  PIN r0_rd_out[148]
    DIRECTION OUTPUT ;
    USE SIGNAL ;
    SHAPE ABUTMENT ;
    PORT
      LAYER M3 ;
      RECT 42.831 44.561 42.849 44.615 ;
    END
  END r0_rd_out[148]
  PIN r0_rd_out[149]
    DIRECTION OUTPUT ;
    USE SIGNAL ;
    SHAPE ABUTMENT ;
    PORT
      LAYER M3 ;
      RECT 43.119 44.561 43.137 44.615 ;
    END
  END r0_rd_out[149]
  PIN r0_rd_out[150]
    DIRECTION OUTPUT ;
    USE SIGNAL ;
    SHAPE ABUTMENT ;
    PORT
      LAYER M3 ;
      RECT 43.407 44.561 43.425 44.615 ;
    END
  END r0_rd_out[150]
  PIN r0_rd_out[151]
    DIRECTION OUTPUT ;
    USE SIGNAL ;
    SHAPE ABUTMENT ;
    PORT
      LAYER M3 ;
      RECT 43.695 44.561 43.713 44.615 ;
    END
  END r0_rd_out[151]
  PIN r0_rd_out[152]
    DIRECTION OUTPUT ;
    USE SIGNAL ;
    SHAPE ABUTMENT ;
    PORT
      LAYER M3 ;
      RECT 43.983 44.561 44.001 44.615 ;
    END
  END r0_rd_out[152]
  PIN r0_rd_out[153]
    DIRECTION OUTPUT ;
    USE SIGNAL ;
    SHAPE ABUTMENT ;
    PORT
      LAYER M3 ;
      RECT 44.271 44.561 44.289 44.615 ;
    END
  END r0_rd_out[153]
  PIN r0_rd_out[154]
    DIRECTION OUTPUT ;
    USE SIGNAL ;
    SHAPE ABUTMENT ;
    PORT
      LAYER M3 ;
      RECT 44.559 44.561 44.577 44.615 ;
    END
  END r0_rd_out[154]
  PIN r0_rd_out[155]
    DIRECTION OUTPUT ;
    USE SIGNAL ;
    SHAPE ABUTMENT ;
    PORT
      LAYER M3 ;
      RECT 44.847 44.561 44.865 44.615 ;
    END
  END r0_rd_out[155]
  PIN r0_rd_out[156]
    DIRECTION OUTPUT ;
    USE SIGNAL ;
    SHAPE ABUTMENT ;
    PORT
      LAYER M3 ;
      RECT 45.135 44.561 45.153 44.615 ;
    END
  END r0_rd_out[156]
  PIN r0_rd_out[157]
    DIRECTION OUTPUT ;
    USE SIGNAL ;
    SHAPE ABUTMENT ;
    PORT
      LAYER M3 ;
      RECT 45.423 44.561 45.441 44.615 ;
    END
  END r0_rd_out[157]
  PIN r0_rd_out[158]
    DIRECTION OUTPUT ;
    USE SIGNAL ;
    SHAPE ABUTMENT ;
    PORT
      LAYER M3 ;
      RECT 45.711 44.561 45.729 44.615 ;
    END
  END r0_rd_out[158]
  PIN r0_rd_out[159]
    DIRECTION OUTPUT ;
    USE SIGNAL ;
    SHAPE ABUTMENT ;
    PORT
      LAYER M3 ;
      RECT 45.999 44.561 46.017 44.615 ;
    END
  END r0_rd_out[159]
  PIN r0_rd_out[160]
    DIRECTION OUTPUT ;
    USE SIGNAL ;
    SHAPE ABUTMENT ;
    PORT
      LAYER M3 ;
      RECT 46.287 44.561 46.305 44.615 ;
    END
  END r0_rd_out[160]
  PIN r0_rd_out[161]
    DIRECTION OUTPUT ;
    USE SIGNAL ;
    SHAPE ABUTMENT ;
    PORT
      LAYER M3 ;
      RECT 46.575 44.561 46.593 44.615 ;
    END
  END r0_rd_out[161]
  PIN r0_rd_out[162]
    DIRECTION OUTPUT ;
    USE SIGNAL ;
    SHAPE ABUTMENT ;
    PORT
      LAYER M3 ;
      RECT 46.863 44.561 46.881 44.615 ;
    END
  END r0_rd_out[162]
  PIN r0_rd_out[163]
    DIRECTION OUTPUT ;
    USE SIGNAL ;
    SHAPE ABUTMENT ;
    PORT
      LAYER M3 ;
      RECT 47.151 44.561 47.169 44.615 ;
    END
  END r0_rd_out[163]
  PIN r0_rd_out[164]
    DIRECTION OUTPUT ;
    USE SIGNAL ;
    SHAPE ABUTMENT ;
    PORT
      LAYER M3 ;
      RECT 47.439 44.561 47.457 44.615 ;
    END
  END r0_rd_out[164]
  PIN r0_rd_out[165]
    DIRECTION OUTPUT ;
    USE SIGNAL ;
    SHAPE ABUTMENT ;
    PORT
      LAYER M3 ;
      RECT 47.727 44.561 47.745 44.615 ;
    END
  END r0_rd_out[165]
  PIN r0_rd_out[166]
    DIRECTION OUTPUT ;
    USE SIGNAL ;
    SHAPE ABUTMENT ;
    PORT
      LAYER M3 ;
      RECT 48.015 44.561 48.033 44.615 ;
    END
  END r0_rd_out[166]
  PIN r0_rd_out[167]
    DIRECTION OUTPUT ;
    USE SIGNAL ;
    SHAPE ABUTMENT ;
    PORT
      LAYER M3 ;
      RECT 48.303 44.561 48.321 44.615 ;
    END
  END r0_rd_out[167]
  PIN r0_rd_out[168]
    DIRECTION OUTPUT ;
    USE SIGNAL ;
    SHAPE ABUTMENT ;
    PORT
      LAYER M3 ;
      RECT 48.591 44.561 48.609 44.615 ;
    END
  END r0_rd_out[168]
  PIN r0_rd_out[169]
    DIRECTION OUTPUT ;
    USE SIGNAL ;
    SHAPE ABUTMENT ;
    PORT
      LAYER M3 ;
      RECT 48.879 44.561 48.897 44.615 ;
    END
  END r0_rd_out[169]
  PIN r0_rd_out[170]
    DIRECTION OUTPUT ;
    USE SIGNAL ;
    SHAPE ABUTMENT ;
    PORT
      LAYER M3 ;
      RECT 49.167 44.561 49.185 44.615 ;
    END
  END r0_rd_out[170]
  PIN r0_rd_out[171]
    DIRECTION OUTPUT ;
    USE SIGNAL ;
    SHAPE ABUTMENT ;
    PORT
      LAYER M3 ;
      RECT 49.455 44.561 49.473 44.615 ;
    END
  END r0_rd_out[171]
  PIN r0_rd_out[172]
    DIRECTION OUTPUT ;
    USE SIGNAL ;
    SHAPE ABUTMENT ;
    PORT
      LAYER M3 ;
      RECT 49.743 44.561 49.761 44.615 ;
    END
  END r0_rd_out[172]
  PIN r0_rd_out[173]
    DIRECTION OUTPUT ;
    USE SIGNAL ;
    SHAPE ABUTMENT ;
    PORT
      LAYER M3 ;
      RECT 50.031 44.561 50.049 44.615 ;
    END
  END r0_rd_out[173]
  PIN r0_rd_out[174]
    DIRECTION OUTPUT ;
    USE SIGNAL ;
    SHAPE ABUTMENT ;
    PORT
      LAYER M3 ;
      RECT 50.319 44.561 50.337 44.615 ;
    END
  END r0_rd_out[174]
  PIN r0_rd_out[175]
    DIRECTION OUTPUT ;
    USE SIGNAL ;
    SHAPE ABUTMENT ;
    PORT
      LAYER M3 ;
      RECT 50.607 44.561 50.625 44.615 ;
    END
  END r0_rd_out[175]
  PIN r0_rd_out[176]
    DIRECTION OUTPUT ;
    USE SIGNAL ;
    SHAPE ABUTMENT ;
    PORT
      LAYER M3 ;
      RECT 50.895 44.561 50.913 44.615 ;
    END
  END r0_rd_out[176]
  PIN r0_rd_out[177]
    DIRECTION OUTPUT ;
    USE SIGNAL ;
    SHAPE ABUTMENT ;
    PORT
      LAYER M3 ;
      RECT 51.183 44.561 51.201 44.615 ;
    END
  END r0_rd_out[177]
  PIN r0_rd_out[178]
    DIRECTION OUTPUT ;
    USE SIGNAL ;
    SHAPE ABUTMENT ;
    PORT
      LAYER M3 ;
      RECT 51.471 44.561 51.489 44.615 ;
    END
  END r0_rd_out[178]
  PIN r0_rd_out[179]
    DIRECTION OUTPUT ;
    USE SIGNAL ;
    SHAPE ABUTMENT ;
    PORT
      LAYER M3 ;
      RECT 51.759 44.561 51.777 44.615 ;
    END
  END r0_rd_out[179]
  PIN r0_rd_out[180]
    DIRECTION OUTPUT ;
    USE SIGNAL ;
    SHAPE ABUTMENT ;
    PORT
      LAYER M3 ;
      RECT 52.047 44.561 52.065 44.615 ;
    END
  END r0_rd_out[180]
  PIN r0_rd_out[181]
    DIRECTION OUTPUT ;
    USE SIGNAL ;
    SHAPE ABUTMENT ;
    PORT
      LAYER M3 ;
      RECT 52.335 44.561 52.353 44.615 ;
    END
  END r0_rd_out[181]
  PIN r0_rd_out[182]
    DIRECTION OUTPUT ;
    USE SIGNAL ;
    SHAPE ABUTMENT ;
    PORT
      LAYER M3 ;
      RECT 52.623 44.561 52.641 44.615 ;
    END
  END r0_rd_out[182]
  PIN r0_rd_out[183]
    DIRECTION OUTPUT ;
    USE SIGNAL ;
    SHAPE ABUTMENT ;
    PORT
      LAYER M3 ;
      RECT 52.911 44.561 52.929 44.615 ;
    END
  END r0_rd_out[183]
  PIN r0_rd_out[184]
    DIRECTION OUTPUT ;
    USE SIGNAL ;
    SHAPE ABUTMENT ;
    PORT
      LAYER M3 ;
      RECT 53.199 44.561 53.217 44.615 ;
    END
  END r0_rd_out[184]
  PIN r0_rd_out[185]
    DIRECTION OUTPUT ;
    USE SIGNAL ;
    SHAPE ABUTMENT ;
    PORT
      LAYER M3 ;
      RECT 53.487 44.561 53.505 44.615 ;
    END
  END r0_rd_out[185]
  PIN r0_rd_out[186]
    DIRECTION OUTPUT ;
    USE SIGNAL ;
    SHAPE ABUTMENT ;
    PORT
      LAYER M3 ;
      RECT 53.775 44.561 53.793 44.615 ;
    END
  END r0_rd_out[186]
  PIN r0_rd_out[187]
    DIRECTION OUTPUT ;
    USE SIGNAL ;
    SHAPE ABUTMENT ;
    PORT
      LAYER M3 ;
      RECT 54.063 44.561 54.081 44.615 ;
    END
  END r0_rd_out[187]
  PIN r0_rd_out[188]
    DIRECTION OUTPUT ;
    USE SIGNAL ;
    SHAPE ABUTMENT ;
    PORT
      LAYER M3 ;
      RECT 54.351 44.561 54.369 44.615 ;
    END
  END r0_rd_out[188]
  PIN r0_rd_out[189]
    DIRECTION OUTPUT ;
    USE SIGNAL ;
    SHAPE ABUTMENT ;
    PORT
      LAYER M3 ;
      RECT 54.639 44.561 54.657 44.615 ;
    END
  END r0_rd_out[189]
  PIN r0_rd_out[190]
    DIRECTION OUTPUT ;
    USE SIGNAL ;
    SHAPE ABUTMENT ;
    PORT
      LAYER M3 ;
      RECT 54.927 44.561 54.945 44.615 ;
    END
  END r0_rd_out[190]
  PIN r0_rd_out[191]
    DIRECTION OUTPUT ;
    USE SIGNAL ;
    SHAPE ABUTMENT ;
    PORT
      LAYER M3 ;
      RECT 55.215 44.561 55.233 44.615 ;
    END
  END r0_rd_out[191]
  PIN r0_rd_out[192]
    DIRECTION OUTPUT ;
    USE SIGNAL ;
    SHAPE ABUTMENT ;
    PORT
      LAYER M3 ;
      RECT 55.503 44.561 55.521 44.615 ;
    END
  END r0_rd_out[192]
  PIN r0_rd_out[193]
    DIRECTION OUTPUT ;
    USE SIGNAL ;
    SHAPE ABUTMENT ;
    PORT
      LAYER M3 ;
      RECT 55.791 44.561 55.809 44.615 ;
    END
  END r0_rd_out[193]
  PIN r0_rd_out[194]
    DIRECTION OUTPUT ;
    USE SIGNAL ;
    SHAPE ABUTMENT ;
    PORT
      LAYER M3 ;
      RECT 56.079 44.561 56.097 44.615 ;
    END
  END r0_rd_out[194]
  PIN r0_rd_out[195]
    DIRECTION OUTPUT ;
    USE SIGNAL ;
    SHAPE ABUTMENT ;
    PORT
      LAYER M3 ;
      RECT 56.367 44.561 56.385 44.615 ;
    END
  END r0_rd_out[195]
  PIN r0_rd_out[196]
    DIRECTION OUTPUT ;
    USE SIGNAL ;
    SHAPE ABUTMENT ;
    PORT
      LAYER M3 ;
      RECT 56.655 44.561 56.673 44.615 ;
    END
  END r0_rd_out[196]
  PIN r0_rd_out[197]
    DIRECTION OUTPUT ;
    USE SIGNAL ;
    SHAPE ABUTMENT ;
    PORT
      LAYER M3 ;
      RECT 56.943 44.561 56.961 44.615 ;
    END
  END r0_rd_out[197]
  PIN r0_rd_out[198]
    DIRECTION OUTPUT ;
    USE SIGNAL ;
    SHAPE ABUTMENT ;
    PORT
      LAYER M3 ;
      RECT 57.231 44.561 57.249 44.615 ;
    END
  END r0_rd_out[198]
  PIN r0_rd_out[199]
    DIRECTION OUTPUT ;
    USE SIGNAL ;
    SHAPE ABUTMENT ;
    PORT
      LAYER M3 ;
      RECT 57.519 44.561 57.537 44.615 ;
    END
  END r0_rd_out[199]
  PIN r0_rd_out[200]
    DIRECTION OUTPUT ;
    USE SIGNAL ;
    SHAPE ABUTMENT ;
    PORT
      LAYER M3 ;
      RECT 57.807 44.561 57.825 44.615 ;
    END
  END r0_rd_out[200]
  PIN r0_rd_out[201]
    DIRECTION OUTPUT ;
    USE SIGNAL ;
    SHAPE ABUTMENT ;
    PORT
      LAYER M3 ;
      RECT 58.095 44.561 58.113 44.615 ;
    END
  END r0_rd_out[201]
  PIN r0_rd_out[202]
    DIRECTION OUTPUT ;
    USE SIGNAL ;
    SHAPE ABUTMENT ;
    PORT
      LAYER M3 ;
      RECT 58.383 44.561 58.401 44.615 ;
    END
  END r0_rd_out[202]
  PIN r0_rd_out[203]
    DIRECTION OUTPUT ;
    USE SIGNAL ;
    SHAPE ABUTMENT ;
    PORT
      LAYER M3 ;
      RECT 58.671 44.561 58.689 44.615 ;
    END
  END r0_rd_out[203]
  PIN r0_rd_out[204]
    DIRECTION OUTPUT ;
    USE SIGNAL ;
    SHAPE ABUTMENT ;
    PORT
      LAYER M3 ;
      RECT 58.959 44.561 58.977 44.615 ;
    END
  END r0_rd_out[204]
  PIN r0_rd_out[205]
    DIRECTION OUTPUT ;
    USE SIGNAL ;
    SHAPE ABUTMENT ;
    PORT
      LAYER M3 ;
      RECT 59.247 44.561 59.265 44.615 ;
    END
  END r0_rd_out[205]
  PIN r0_rd_out[206]
    DIRECTION OUTPUT ;
    USE SIGNAL ;
    SHAPE ABUTMENT ;
    PORT
      LAYER M3 ;
      RECT 59.535 44.561 59.553 44.615 ;
    END
  END r0_rd_out[206]
  PIN r0_rd_out[207]
    DIRECTION OUTPUT ;
    USE SIGNAL ;
    SHAPE ABUTMENT ;
    PORT
      LAYER M3 ;
      RECT 59.823 44.561 59.841 44.615 ;
    END
  END r0_rd_out[207]
  PIN r0_rd_out[208]
    DIRECTION OUTPUT ;
    USE SIGNAL ;
    SHAPE ABUTMENT ;
    PORT
      LAYER M3 ;
      RECT 60.111 44.561 60.129 44.615 ;
    END
  END r0_rd_out[208]
  PIN r0_rd_out[209]
    DIRECTION OUTPUT ;
    USE SIGNAL ;
    SHAPE ABUTMENT ;
    PORT
      LAYER M3 ;
      RECT 60.399 44.561 60.417 44.615 ;
    END
  END r0_rd_out[209]
  PIN r0_rd_out[210]
    DIRECTION OUTPUT ;
    USE SIGNAL ;
    SHAPE ABUTMENT ;
    PORT
      LAYER M3 ;
      RECT 60.687 44.561 60.705 44.615 ;
    END
  END r0_rd_out[210]
  PIN r0_rd_out[211]
    DIRECTION OUTPUT ;
    USE SIGNAL ;
    SHAPE ABUTMENT ;
    PORT
      LAYER M3 ;
      RECT 60.975 44.561 60.993 44.615 ;
    END
  END r0_rd_out[211]
  PIN r0_rd_out[212]
    DIRECTION OUTPUT ;
    USE SIGNAL ;
    SHAPE ABUTMENT ;
    PORT
      LAYER M3 ;
      RECT 61.263 44.561 61.281 44.615 ;
    END
  END r0_rd_out[212]
  PIN r0_rd_out[213]
    DIRECTION OUTPUT ;
    USE SIGNAL ;
    SHAPE ABUTMENT ;
    PORT
      LAYER M3 ;
      RECT 61.551 44.561 61.569 44.615 ;
    END
  END r0_rd_out[213]
  PIN r0_rd_out[214]
    DIRECTION OUTPUT ;
    USE SIGNAL ;
    SHAPE ABUTMENT ;
    PORT
      LAYER M3 ;
      RECT 61.839 44.561 61.857 44.615 ;
    END
  END r0_rd_out[214]
  PIN r0_rd_out[215]
    DIRECTION OUTPUT ;
    USE SIGNAL ;
    SHAPE ABUTMENT ;
    PORT
      LAYER M3 ;
      RECT 62.127 44.561 62.145 44.615 ;
    END
  END r0_rd_out[215]
  PIN r0_rd_out[216]
    DIRECTION OUTPUT ;
    USE SIGNAL ;
    SHAPE ABUTMENT ;
    PORT
      LAYER M3 ;
      RECT 62.415 44.561 62.433 44.615 ;
    END
  END r0_rd_out[216]
  PIN r0_rd_out[217]
    DIRECTION OUTPUT ;
    USE SIGNAL ;
    SHAPE ABUTMENT ;
    PORT
      LAYER M3 ;
      RECT 62.703 44.561 62.721 44.615 ;
    END
  END r0_rd_out[217]
  PIN r0_rd_out[218]
    DIRECTION OUTPUT ;
    USE SIGNAL ;
    SHAPE ABUTMENT ;
    PORT
      LAYER M3 ;
      RECT 62.991 44.561 63.009 44.615 ;
    END
  END r0_rd_out[218]
  PIN r0_rd_out[219]
    DIRECTION OUTPUT ;
    USE SIGNAL ;
    SHAPE ABUTMENT ;
    PORT
      LAYER M3 ;
      RECT 63.279 44.561 63.297 44.615 ;
    END
  END r0_rd_out[219]
  PIN r0_rd_out[220]
    DIRECTION OUTPUT ;
    USE SIGNAL ;
    SHAPE ABUTMENT ;
    PORT
      LAYER M3 ;
      RECT 63.567 44.561 63.585 44.615 ;
    END
  END r0_rd_out[220]
  PIN r0_rd_out[221]
    DIRECTION OUTPUT ;
    USE SIGNAL ;
    SHAPE ABUTMENT ;
    PORT
      LAYER M3 ;
      RECT 63.855 44.561 63.873 44.615 ;
    END
  END r0_rd_out[221]
  PIN r0_rd_out[222]
    DIRECTION OUTPUT ;
    USE SIGNAL ;
    SHAPE ABUTMENT ;
    PORT
      LAYER M3 ;
      RECT 64.143 44.561 64.161 44.615 ;
    END
  END r0_rd_out[222]
  PIN r0_rd_out[223]
    DIRECTION OUTPUT ;
    USE SIGNAL ;
    SHAPE ABUTMENT ;
    PORT
      LAYER M3 ;
      RECT 64.431 44.561 64.449 44.615 ;
    END
  END r0_rd_out[223]
  PIN r0_rd_out[224]
    DIRECTION OUTPUT ;
    USE SIGNAL ;
    SHAPE ABUTMENT ;
    PORT
      LAYER M3 ;
      RECT 64.719 44.561 64.737 44.615 ;
    END
  END r0_rd_out[224]
  PIN r0_rd_out[225]
    DIRECTION OUTPUT ;
    USE SIGNAL ;
    SHAPE ABUTMENT ;
    PORT
      LAYER M3 ;
      RECT 65.007 44.561 65.025 44.615 ;
    END
  END r0_rd_out[225]
  PIN r0_rd_out[226]
    DIRECTION OUTPUT ;
    USE SIGNAL ;
    SHAPE ABUTMENT ;
    PORT
      LAYER M3 ;
      RECT 65.295 44.561 65.313 44.615 ;
    END
  END r0_rd_out[226]
  PIN r0_rd_out[227]
    DIRECTION OUTPUT ;
    USE SIGNAL ;
    SHAPE ABUTMENT ;
    PORT
      LAYER M3 ;
      RECT 65.583 44.561 65.601 44.615 ;
    END
  END r0_rd_out[227]
  PIN r0_rd_out[228]
    DIRECTION OUTPUT ;
    USE SIGNAL ;
    SHAPE ABUTMENT ;
    PORT
      LAYER M3 ;
      RECT 65.871 44.561 65.889 44.615 ;
    END
  END r0_rd_out[228]
  PIN r0_rd_out[229]
    DIRECTION OUTPUT ;
    USE SIGNAL ;
    SHAPE ABUTMENT ;
    PORT
      LAYER M3 ;
      RECT 66.159 44.561 66.177 44.615 ;
    END
  END r0_rd_out[229]
  PIN rw0_addr_in[0]
    DIRECTION INPUT ;
    USE SIGNAL ;
    SHAPE ABUTMENT ;
    PORT
      LAYER M4 ;
      RECT 0.000 39.252 0.072 39.276 ;
    END
  END rw0_addr_in[0]
  PIN rw0_addr_in[1]
    DIRECTION INPUT ;
    USE SIGNAL ;
    SHAPE ABUTMENT ;
    PORT
      LAYER M4 ;
      RECT 0.000 39.924 0.072 39.948 ;
    END
  END rw0_addr_in[1]
  PIN rw0_addr_in[2]
    DIRECTION INPUT ;
    USE SIGNAL ;
    SHAPE ABUTMENT ;
    PORT
      LAYER M4 ;
      RECT 0.000 40.596 0.072 40.620 ;
    END
  END rw0_addr_in[2]
  PIN rw0_addr_in[3]
    DIRECTION INPUT ;
    USE SIGNAL ;
    SHAPE ABUTMENT ;
    PORT
      LAYER M4 ;
      RECT 0.000 41.268 0.072 41.292 ;
    END
  END rw0_addr_in[3]
  PIN rw0_addr_in[4]
    DIRECTION INPUT ;
    USE SIGNAL ;
    SHAPE ABUTMENT ;
    PORT
      LAYER M4 ;
      RECT 75.939 38.580 76.011 38.604 ;
    END
  END rw0_addr_in[4]
  PIN rw0_addr_in[5]
    DIRECTION INPUT ;
    USE SIGNAL ;
    SHAPE ABUTMENT ;
    PORT
      LAYER M4 ;
      RECT 75.939 39.252 76.011 39.276 ;
    END
  END rw0_addr_in[5]
  PIN rw0_addr_in[6]
    DIRECTION INPUT ;
    USE SIGNAL ;
    SHAPE ABUTMENT ;
    PORT
      LAYER M4 ;
      RECT 75.939 39.924 76.011 39.948 ;
    END
  END rw0_addr_in[6]
  PIN r0_addr_in[0]
    DIRECTION INPUT ;
    USE SIGNAL ;
    SHAPE ABUTMENT ;
    PORT
      LAYER M4 ;
      RECT 0.000 41.940 0.072 41.964 ;
    END
  END r0_addr_in[0]
  PIN r0_addr_in[1]
    DIRECTION INPUT ;
    USE SIGNAL ;
    SHAPE ABUTMENT ;
    PORT
      LAYER M4 ;
      RECT 0.000 42.612 0.072 42.636 ;
    END
  END r0_addr_in[1]
  PIN r0_addr_in[2]
    DIRECTION INPUT ;
    USE SIGNAL ;
    SHAPE ABUTMENT ;
    PORT
      LAYER M4 ;
      RECT 0.000 43.284 0.072 43.308 ;
    END
  END r0_addr_in[2]
  PIN r0_addr_in[3]
    DIRECTION INPUT ;
    USE SIGNAL ;
    SHAPE ABUTMENT ;
    PORT
      LAYER M4 ;
      RECT 0.000 43.956 0.072 43.980 ;
    END
  END r0_addr_in[3]
  PIN r0_addr_in[4]
    DIRECTION INPUT ;
    USE SIGNAL ;
    SHAPE ABUTMENT ;
    PORT
      LAYER M4 ;
      RECT 75.939 40.596 76.011 40.620 ;
    END
  END r0_addr_in[4]
  PIN r0_addr_in[5]
    DIRECTION INPUT ;
    USE SIGNAL ;
    SHAPE ABUTMENT ;
    PORT
      LAYER M4 ;
      RECT 75.939 41.268 76.011 41.292 ;
    END
  END r0_addr_in[5]
  PIN r0_addr_in[6]
    DIRECTION INPUT ;
    USE SIGNAL ;
    SHAPE ABUTMENT ;
    PORT
      LAYER M4 ;
      RECT 75.939 41.940 76.011 41.964 ;
    END
  END r0_addr_in[6]
  PIN rw0_we_in
    DIRECTION INPUT ;
    USE SIGNAL ;
    SHAPE ABUTMENT ;
    PORT
      LAYER M3 ;
      RECT 66.447 44.561 66.465 44.615 ;
    END
  END rw0_we_in
  PIN rw0_ce_in
    DIRECTION INPUT ;
    USE SIGNAL ;
    SHAPE ABUTMENT ;
    PORT
      LAYER M3 ;
      RECT 66.735 44.561 66.753 44.615 ;
    END
  END rw0_ce_in
  PIN rw0_clk
    DIRECTION INPUT ;
    USE SIGNAL ;
    SHAPE ABUTMENT ;
    PORT
      LAYER M3 ;
      RECT 67.023 44.561 67.041 44.615 ;
    END
  END rw0_clk
  PIN r0_ce_in
    DIRECTION INPUT ;
    USE SIGNAL ;
    SHAPE ABUTMENT ;
    PORT
      LAYER M3 ;
      RECT 67.311 44.561 67.329 44.615 ;
    END
  END r0_ce_in
  PIN r0_clk
    DIRECTION INPUT ;
    USE SIGNAL ;
    SHAPE ABUTMENT ;
    PORT
      LAYER M3 ;
      RECT 67.599 44.561 67.617 44.615 ;
    END
  END r0_clk
  PIN VSS
    DIRECTION INOUT ;
    USE GROUND ;
    PORT
      LAYER M4 ;
      RECT 0.216 0.240 75.795 0.336 ;
      RECT 0.216 1.008 75.795 1.104 ;
      RECT 0.216 1.776 75.795 1.872 ;
      RECT 0.216 2.544 75.795 2.640 ;
      RECT 0.216 3.312 75.795 3.408 ;
      RECT 0.216 4.080 75.795 4.176 ;
      RECT 0.216 4.848 75.795 4.944 ;
      RECT 0.216 5.616 75.795 5.712 ;
      RECT 0.216 6.384 75.795 6.480 ;
      RECT 0.216 7.152 75.795 7.248 ;
      RECT 0.216 7.920 75.795 8.016 ;
      RECT 0.216 8.688 75.795 8.784 ;
      RECT 0.216 9.456 75.795 9.552 ;
      RECT 0.216 10.224 75.795 10.320 ;
      RECT 0.216 10.992 75.795 11.088 ;
      RECT 0.216 11.760 75.795 11.856 ;
      RECT 0.216 12.528 75.795 12.624 ;
      RECT 0.216 13.296 75.795 13.392 ;
      RECT 0.216 14.064 75.795 14.160 ;
      RECT 0.216 14.832 75.795 14.928 ;
      RECT 0.216 15.600 75.795 15.696 ;
      RECT 0.216 16.368 75.795 16.464 ;
      RECT 0.216 17.136 75.795 17.232 ;
      RECT 0.216 17.904 75.795 18.000 ;
      RECT 0.216 18.672 75.795 18.768 ;
      RECT 0.216 19.440 75.795 19.536 ;
      RECT 0.216 20.208 75.795 20.304 ;
      RECT 0.216 20.976 75.795 21.072 ;
      RECT 0.216 21.744 75.795 21.840 ;
      RECT 0.216 22.512 75.795 22.608 ;
      RECT 0.216 23.280 75.795 23.376 ;
      RECT 0.216 24.048 75.795 24.144 ;
      RECT 0.216 24.816 75.795 24.912 ;
      RECT 0.216 25.584 75.795 25.680 ;
      RECT 0.216 26.352 75.795 26.448 ;
      RECT 0.216 27.120 75.795 27.216 ;
      RECT 0.216 27.888 75.795 27.984 ;
      RECT 0.216 28.656 75.795 28.752 ;
      RECT 0.216 29.424 75.795 29.520 ;
      RECT 0.216 30.192 75.795 30.288 ;
      RECT 0.216 30.960 75.795 31.056 ;
      RECT 0.216 31.728 75.795 31.824 ;
      RECT 0.216 32.496 75.795 32.592 ;
      RECT 0.216 33.264 75.795 33.360 ;
      RECT 0.216 34.032 75.795 34.128 ;
      RECT 0.216 34.800 75.795 34.896 ;
      RECT 0.216 35.568 75.795 35.664 ;
      RECT 0.216 36.336 75.795 36.432 ;
      RECT 0.216 37.104 75.795 37.200 ;
      RECT 0.216 37.872 75.795 37.968 ;
      RECT 0.216 38.640 75.795 38.736 ;
      RECT 0.216 39.408 75.795 39.504 ;
      RECT 0.216 40.176 75.795 40.272 ;
      RECT 0.216 40.944 75.795 41.040 ;
      RECT 0.216 41.712 75.795 41.808 ;
      RECT 0.216 42.480 75.795 42.576 ;
      RECT 0.216 43.248 75.795 43.344 ;
      RECT 0.216 44.016 75.795 44.112 ;
    END
  END VSS
  PIN VDD
    DIRECTION INOUT ;
    USE POWER ;
    PORT
      LAYER M4 ;
      RECT 0.216 0.240 75.795 0.336 ;
      RECT 0.216 1.008 75.795 1.104 ;
      RECT 0.216 1.776 75.795 1.872 ;
      RECT 0.216 2.544 75.795 2.640 ;
      RECT 0.216 3.312 75.795 3.408 ;
      RECT 0.216 4.080 75.795 4.176 ;
      RECT 0.216 4.848 75.795 4.944 ;
      RECT 0.216 5.616 75.795 5.712 ;
      RECT 0.216 6.384 75.795 6.480 ;
      RECT 0.216 7.152 75.795 7.248 ;
      RECT 0.216 7.920 75.795 8.016 ;
      RECT 0.216 8.688 75.795 8.784 ;
      RECT 0.216 9.456 75.795 9.552 ;
      RECT 0.216 10.224 75.795 10.320 ;
      RECT 0.216 10.992 75.795 11.088 ;
      RECT 0.216 11.760 75.795 11.856 ;
      RECT 0.216 12.528 75.795 12.624 ;
      RECT 0.216 13.296 75.795 13.392 ;
      RECT 0.216 14.064 75.795 14.160 ;
      RECT 0.216 14.832 75.795 14.928 ;
      RECT 0.216 15.600 75.795 15.696 ;
      RECT 0.216 16.368 75.795 16.464 ;
      RECT 0.216 17.136 75.795 17.232 ;
      RECT 0.216 17.904 75.795 18.000 ;
      RECT 0.216 18.672 75.795 18.768 ;
      RECT 0.216 19.440 75.795 19.536 ;
      RECT 0.216 20.208 75.795 20.304 ;
      RECT 0.216 20.976 75.795 21.072 ;
      RECT 0.216 21.744 75.795 21.840 ;
      RECT 0.216 22.512 75.795 22.608 ;
      RECT 0.216 23.280 75.795 23.376 ;
      RECT 0.216 24.048 75.795 24.144 ;
      RECT 0.216 24.816 75.795 24.912 ;
      RECT 0.216 25.584 75.795 25.680 ;
      RECT 0.216 26.352 75.795 26.448 ;
      RECT 0.216 27.120 75.795 27.216 ;
      RECT 0.216 27.888 75.795 27.984 ;
      RECT 0.216 28.656 75.795 28.752 ;
      RECT 0.216 29.424 75.795 29.520 ;
      RECT 0.216 30.192 75.795 30.288 ;
      RECT 0.216 30.960 75.795 31.056 ;
      RECT 0.216 31.728 75.795 31.824 ;
      RECT 0.216 32.496 75.795 32.592 ;
      RECT 0.216 33.264 75.795 33.360 ;
      RECT 0.216 34.032 75.795 34.128 ;
      RECT 0.216 34.800 75.795 34.896 ;
      RECT 0.216 35.568 75.795 35.664 ;
      RECT 0.216 36.336 75.795 36.432 ;
      RECT 0.216 37.104 75.795 37.200 ;
      RECT 0.216 37.872 75.795 37.968 ;
      RECT 0.216 38.640 75.795 38.736 ;
      RECT 0.216 39.408 75.795 39.504 ;
      RECT 0.216 40.176 75.795 40.272 ;
      RECT 0.216 40.944 75.795 41.040 ;
      RECT 0.216 41.712 75.795 41.808 ;
      RECT 0.216 42.480 75.795 42.576 ;
      RECT 0.216 43.248 75.795 43.344 ;
      RECT 0.216 44.016 75.795 44.112 ;
    END
  END VDD
  OBS
    LAYER M1 ;
    RECT 0 0 76.011 44.615 ;
    LAYER M2 ;
    RECT 0 0 76.011 44.615 ;
    LAYER M3 ;
    RECT 0 0 76.011 44.615 ;
    LAYER M4 ;
    RECT 0 0 76.011 44.615 ;
  END
END fakeram_1rw1r_230w128d_sram

END LIBRARY
